# OpenTallas tools/qwen_missing/link_phy_gen.py: ot_qfd_serdes_112g_x12_phy_s597 hard-macro ABSTRACT (licensed PHY IP; FDI side only)
VERSION 5.7 ;
BUSBITCHARS "[]" ;
DIVIDERCHAR "/" ;
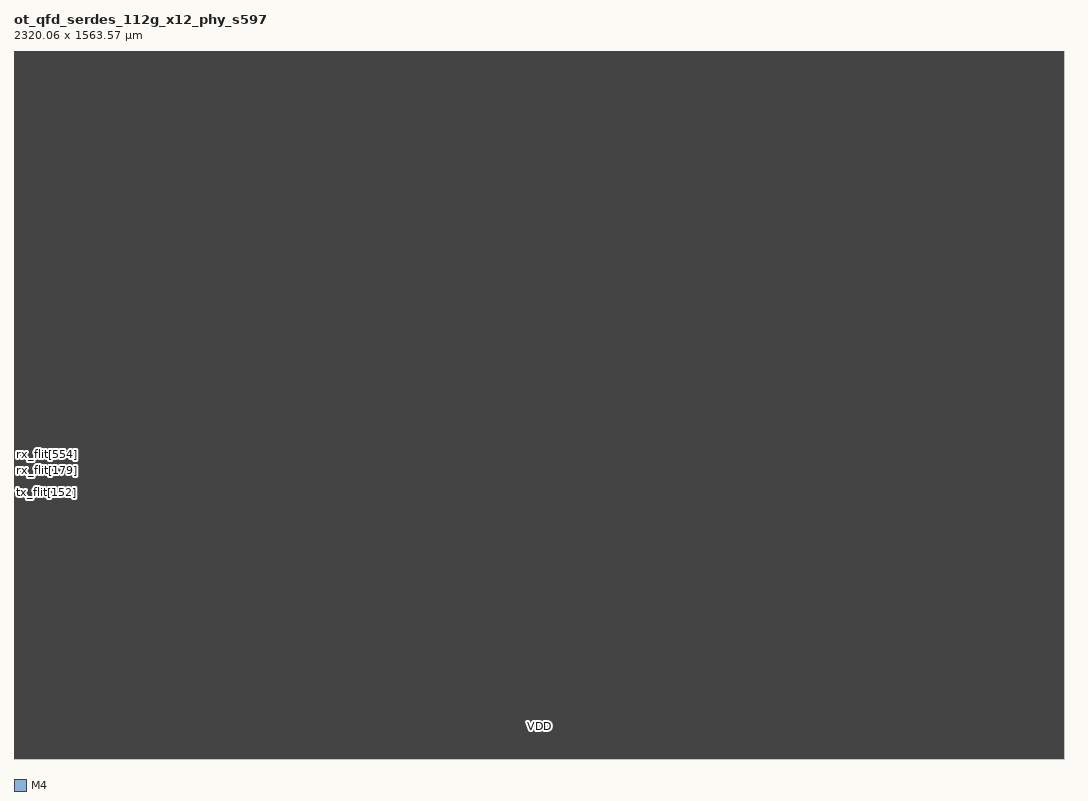
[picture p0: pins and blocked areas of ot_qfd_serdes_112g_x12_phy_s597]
MACRO ot_qfd_serdes_112g_x12_phy_s597
  FOREIGN ot_qfd_serdes_112g_x12_phy_s597 0 0 ;
  SYMMETRY X Y ;
  SIZE 2320.056 BY 1563.570 ;
  CLASS BLOCK ;
  PIN clk
    DIRECTION INPUT ;
    USE CLOCK ;
    SHAPE ABUTMENT ;
    PORT
      LAYER M4 ;
      RECT 0 600.000 0.192 600.024 ;
    END
  END clk
  PIN rst_n
    DIRECTION INPUT ;
    USE SIGNAL ;
    SHAPE ABUTMENT ;
    PORT
      LAYER M4 ;
      RECT 0 600.048 0.192 600.072 ;
    END
  END rst_n
  PIN tx_up
    DIRECTION OUTPUT ;
    USE SIGNAL ;
    SHAPE ABUTMENT ;
    PORT
      LAYER M4 ;
      RECT 0 600.096 0.192 600.120 ;
    END
  END tx_up
  PIN tx_v
    DIRECTION INPUT ;
    USE SIGNAL ;
    SHAPE ABUTMENT ;
    PORT
      LAYER M4 ;
      RECT 0 600.144 0.192 600.168 ;
    END
  END tx_v
  PIN tx_flit[0]
    DIRECTION INPUT ;
    USE SIGNAL ;
    SHAPE ABUTMENT ;
    PORT
      LAYER M4 ;
      RECT 0 600.192 0.192 600.216 ;
    END
  END tx_flit[0]
  PIN tx_flit[1]
    DIRECTION INPUT ;
    USE SIGNAL ;
    SHAPE ABUTMENT ;
    PORT
      LAYER M4 ;
      RECT 0 600.240 0.192 600.264 ;
    END
  END tx_flit[1]
  PIN tx_flit[2]
    DIRECTION INPUT ;
    USE SIGNAL ;
    SHAPE ABUTMENT ;
    PORT
      LAYER M4 ;
      RECT 0 600.288 0.192 600.312 ;
    END
  END tx_flit[2]
  PIN tx_flit[3]
    DIRECTION INPUT ;
    USE SIGNAL ;
    SHAPE ABUTMENT ;
    PORT
      LAYER M4 ;
      RECT 0 600.336 0.192 600.360 ;
    END
  END tx_flit[3]
  PIN tx_flit[4]
    DIRECTION INPUT ;
    USE SIGNAL ;
    SHAPE ABUTMENT ;
    PORT
      LAYER M4 ;
      RECT 0 600.384 0.192 600.408 ;
    END
  END tx_flit[4]
  PIN tx_flit[5]
    DIRECTION INPUT ;
    USE SIGNAL ;
    SHAPE ABUTMENT ;
    PORT
      LAYER M4 ;
      RECT 0 600.432 0.192 600.456 ;
    END
  END tx_flit[5]
  PIN tx_flit[6]
    DIRECTION INPUT ;
    USE SIGNAL ;
    SHAPE ABUTMENT ;
    PORT
      LAYER M4 ;
      RECT 0 600.480 0.192 600.504 ;
    END
  END tx_flit[6]
  PIN tx_flit[7]
    DIRECTION INPUT ;
    USE SIGNAL ;
    SHAPE ABUTMENT ;
    PORT
      LAYER M4 ;
      RECT 0 600.528 0.192 600.552 ;
    END
  END tx_flit[7]
  PIN tx_flit[8]
    DIRECTION INPUT ;
    USE SIGNAL ;
    SHAPE ABUTMENT ;
    PORT
      LAYER M4 ;
      RECT 0 600.576 0.192 600.600 ;
    END
  END tx_flit[8]
  PIN tx_flit[9]
    DIRECTION INPUT ;
    USE SIGNAL ;
    SHAPE ABUTMENT ;
    PORT
      LAYER M4 ;
      RECT 0 600.624 0.192 600.648 ;
    END
  END tx_flit[9]
  PIN tx_flit[10]
    DIRECTION INPUT ;
    USE SIGNAL ;
    SHAPE ABUTMENT ;
    PORT
      LAYER M4 ;
      RECT 0 600.672 0.192 600.696 ;
    END
  END tx_flit[10]
  PIN tx_flit[11]
    DIRECTION INPUT ;
    USE SIGNAL ;
    SHAPE ABUTMENT ;
    PORT
      LAYER M4 ;
      RECT 0 600.720 0.192 600.744 ;
    END
  END tx_flit[11]
  PIN tx_flit[12]
    DIRECTION INPUT ;
    USE SIGNAL ;
    SHAPE ABUTMENT ;
    PORT
      LAYER M4 ;
      RECT 0 600.768 0.192 600.792 ;
    END
  END tx_flit[12]
  PIN tx_flit[13]
    DIRECTION INPUT ;
    USE SIGNAL ;
    SHAPE ABUTMENT ;
    PORT
      LAYER M4 ;
      RECT 0 600.816 0.192 600.840 ;
    END
  END tx_flit[13]
  PIN tx_flit[14]
    DIRECTION INPUT ;
    USE SIGNAL ;
    SHAPE ABUTMENT ;
    PORT
      LAYER M4 ;
      RECT 0 600.864 0.192 600.888 ;
    END
  END tx_flit[14]
  PIN tx_flit[15]
    DIRECTION INPUT ;
    USE SIGNAL ;
    SHAPE ABUTMENT ;
    PORT
      LAYER M4 ;
      RECT 0 600.912 0.192 600.936 ;
    END
  END tx_flit[15]
  PIN tx_flit[16]
    DIRECTION INPUT ;
    USE SIGNAL ;
    SHAPE ABUTMENT ;
    PORT
      LAYER M4 ;
      RECT 0 600.960 0.192 600.984 ;
    END
  END tx_flit[16]
  PIN tx_flit[17]
    DIRECTION INPUT ;
    USE SIGNAL ;
    SHAPE ABUTMENT ;
    PORT
      LAYER M4 ;
      RECT 0 601.008 0.192 601.032 ;
    END
  END tx_flit[17]
  PIN tx_flit[18]
    DIRECTION INPUT ;
    USE SIGNAL ;
    SHAPE ABUTMENT ;
    PORT
      LAYER M4 ;
      RECT 0 601.056 0.192 601.080 ;
    END
  END tx_flit[18]
  PIN tx_flit[19]
    DIRECTION INPUT ;
    USE SIGNAL ;
    SHAPE ABUTMENT ;
    PORT
      LAYER M4 ;
      RECT 0 601.104 0.192 601.128 ;
    END
  END tx_flit[19]
  PIN tx_flit[20]
    DIRECTION INPUT ;
    USE SIGNAL ;
    SHAPE ABUTMENT ;
    PORT
      LAYER M4 ;
      RECT 0 601.152 0.192 601.176 ;
    END
  END tx_flit[20]
  PIN tx_flit[21]
    DIRECTION INPUT ;
    USE SIGNAL ;
    SHAPE ABUTMENT ;
    PORT
      LAYER M4 ;
      RECT 0 601.200 0.192 601.224 ;
    END
  END tx_flit[21]
  PIN tx_flit[22]
    DIRECTION INPUT ;
    USE SIGNAL ;
    SHAPE ABUTMENT ;
    PORT
      LAYER M4 ;
      RECT 0 601.248 0.192 601.272 ;
    END
  END tx_flit[22]
  PIN tx_flit[23]
    DIRECTION INPUT ;
    USE SIGNAL ;
    SHAPE ABUTMENT ;
    PORT
      LAYER M4 ;
      RECT 0 601.296 0.192 601.320 ;
    END
  END tx_flit[23]
  PIN tx_flit[24]
    DIRECTION INPUT ;
    USE SIGNAL ;
    SHAPE ABUTMENT ;
    PORT
      LAYER M4 ;
      RECT 0 601.344 0.192 601.368 ;
    END
  END tx_flit[24]
  PIN tx_flit[25]
    DIRECTION INPUT ;
    USE SIGNAL ;
    SHAPE ABUTMENT ;
    PORT
      LAYER M4 ;
      RECT 0 601.392 0.192 601.416 ;
    END
  END tx_flit[25]
  PIN tx_flit[26]
    DIRECTION INPUT ;
    USE SIGNAL ;
    SHAPE ABUTMENT ;
    PORT
      LAYER M4 ;
      RECT 0 601.440 0.192 601.464 ;
    END
  END tx_flit[26]
  PIN tx_flit[27]
    DIRECTION INPUT ;
    USE SIGNAL ;
    SHAPE ABUTMENT ;
    PORT
      LAYER M4 ;
      RECT 0 601.488 0.192 601.512 ;
    END
  END tx_flit[27]
  PIN tx_flit[28]
    DIRECTION INPUT ;
    USE SIGNAL ;
    SHAPE ABUTMENT ;
    PORT
      LAYER M4 ;
      RECT 0 601.536 0.192 601.560 ;
    END
  END tx_flit[28]
  PIN tx_flit[29]
    DIRECTION INPUT ;
    USE SIGNAL ;
    SHAPE ABUTMENT ;
    PORT
      LAYER M4 ;
      RECT 0 601.584 0.192 601.608 ;
    END
  END tx_flit[29]
  PIN tx_flit[30]
    DIRECTION INPUT ;
    USE SIGNAL ;
    SHAPE ABUTMENT ;
    PORT
      LAYER M4 ;
      RECT 0 601.632 0.192 601.656 ;
    END
  END tx_flit[30]
  PIN tx_flit[31]
    DIRECTION INPUT ;
    USE SIGNAL ;
    SHAPE ABUTMENT ;
    PORT
      LAYER M4 ;
      RECT 0 601.680 0.192 601.704 ;
    END
  END tx_flit[31]
  PIN tx_flit[32]
    DIRECTION INPUT ;
    USE SIGNAL ;
    SHAPE ABUTMENT ;
    PORT
      LAYER M4 ;
      RECT 0 601.728 0.192 601.752 ;
    END
  END tx_flit[32]
  PIN tx_flit[33]
    DIRECTION INPUT ;
    USE SIGNAL ;
    SHAPE ABUTMENT ;
    PORT
      LAYER M4 ;
      RECT 0 601.776 0.192 601.800 ;
    END
  END tx_flit[33]
  PIN tx_flit[34]
    DIRECTION INPUT ;
    USE SIGNAL ;
    SHAPE ABUTMENT ;
    PORT
      LAYER M4 ;
      RECT 0 601.824 0.192 601.848 ;
    END
  END tx_flit[34]
  PIN tx_flit[35]
    DIRECTION INPUT ;
    USE SIGNAL ;
    SHAPE ABUTMENT ;
    PORT
      LAYER M4 ;
      RECT 0 601.872 0.192 601.896 ;
    END
  END tx_flit[35]
  PIN tx_flit[36]
    DIRECTION INPUT ;
    USE SIGNAL ;
    SHAPE ABUTMENT ;
    PORT
      LAYER M4 ;
      RECT 0 601.920 0.192 601.944 ;
    END
  END tx_flit[36]
  PIN tx_flit[37]
    DIRECTION INPUT ;
    USE SIGNAL ;
    SHAPE ABUTMENT ;
    PORT
      LAYER M4 ;
      RECT 0 601.968 0.192 601.992 ;
    END
  END tx_flit[37]
  PIN tx_flit[38]
    DIRECTION INPUT ;
    USE SIGNAL ;
    SHAPE ABUTMENT ;
    PORT
      LAYER M4 ;
      RECT 0 602.016 0.192 602.040 ;
    END
  END tx_flit[38]
  PIN tx_flit[39]
    DIRECTION INPUT ;
    USE SIGNAL ;
    SHAPE ABUTMENT ;
    PORT
      LAYER M4 ;
      RECT 0 602.064 0.192 602.088 ;
    END
  END tx_flit[39]
  PIN tx_flit[40]
    DIRECTION INPUT ;
    USE SIGNAL ;
    SHAPE ABUTMENT ;
    PORT
      LAYER M4 ;
      RECT 0 602.112 0.192 602.136 ;
    END
  END tx_flit[40]
  PIN tx_flit[41]
    DIRECTION INPUT ;
    USE SIGNAL ;
    SHAPE ABUTMENT ;
    PORT
      LAYER M4 ;
      RECT 0 602.160 0.192 602.184 ;
    END
  END tx_flit[41]
  PIN tx_flit[42]
    DIRECTION INPUT ;
    USE SIGNAL ;
    SHAPE ABUTMENT ;
    PORT
      LAYER M4 ;
      RECT 0 602.208 0.192 602.232 ;
    END
  END tx_flit[42]
  PIN tx_flit[43]
    DIRECTION INPUT ;
    USE SIGNAL ;
    SHAPE ABUTMENT ;
    PORT
      LAYER M4 ;
      RECT 0 602.256 0.192 602.280 ;
    END
  END tx_flit[43]
  PIN tx_flit[44]
    DIRECTION INPUT ;
    USE SIGNAL ;
    SHAPE ABUTMENT ;
    PORT
      LAYER M4 ;
      RECT 0 602.304 0.192 602.328 ;
    END
  END tx_flit[44]
  PIN tx_flit[45]
    DIRECTION INPUT ;
    USE SIGNAL ;
    SHAPE ABUTMENT ;
    PORT
      LAYER M4 ;
      RECT 0 602.352 0.192 602.376 ;
    END
  END tx_flit[45]
  PIN tx_flit[46]
    DIRECTION INPUT ;
    USE SIGNAL ;
    SHAPE ABUTMENT ;
    PORT
      LAYER M4 ;
      RECT 0 602.400 0.192 602.424 ;
    END
  END tx_flit[46]
  PIN tx_flit[47]
    DIRECTION INPUT ;
    USE SIGNAL ;
    SHAPE ABUTMENT ;
    PORT
      LAYER M4 ;
      RECT 0 602.448 0.192 602.472 ;
    END
  END tx_flit[47]
  PIN tx_flit[48]
    DIRECTION INPUT ;
    USE SIGNAL ;
    SHAPE ABUTMENT ;
    PORT
      LAYER M4 ;
      RECT 0 602.496 0.192 602.520 ;
    END
  END tx_flit[48]
  PIN tx_flit[49]
    DIRECTION INPUT ;
    USE SIGNAL ;
    SHAPE ABUTMENT ;
    PORT
      LAYER M4 ;
      RECT 0 602.544 0.192 602.568 ;
    END
  END tx_flit[49]
  PIN tx_flit[50]
    DIRECTION INPUT ;
    USE SIGNAL ;
    SHAPE ABUTMENT ;
    PORT
      LAYER M4 ;
      RECT 0 602.592 0.192 602.616 ;
    END
  END tx_flit[50]
  PIN tx_flit[51]
    DIRECTION INPUT ;
    USE SIGNAL ;
    SHAPE ABUTMENT ;
    PORT
      LAYER M4 ;
      RECT 0 602.640 0.192 602.664 ;
    END
  END tx_flit[51]
  PIN tx_flit[52]
    DIRECTION INPUT ;
    USE SIGNAL ;
    SHAPE ABUTMENT ;
    PORT
      LAYER M4 ;
      RECT 0 602.688 0.192 602.712 ;
    END
  END tx_flit[52]
  PIN tx_flit[53]
    DIRECTION INPUT ;
    USE SIGNAL ;
    SHAPE ABUTMENT ;
    PORT
      LAYER M4 ;
      RECT 0 602.736 0.192 602.760 ;
    END
  END tx_flit[53]
  PIN tx_flit[54]
    DIRECTION INPUT ;
    USE SIGNAL ;
    SHAPE ABUTMENT ;
    PORT
      LAYER M4 ;
      RECT 0 602.784 0.192 602.808 ;
    END
  END tx_flit[54]
  PIN tx_flit[55]
    DIRECTION INPUT ;
    USE SIGNAL ;
    SHAPE ABUTMENT ;
    PORT
      LAYER M4 ;
      RECT 0 602.832 0.192 602.856 ;
    END
  END tx_flit[55]
  PIN tx_flit[56]
    DIRECTION INPUT ;
    USE SIGNAL ;
    SHAPE ABUTMENT ;
    PORT
      LAYER M4 ;
      RECT 0 602.880 0.192 602.904 ;
    END
  END tx_flit[56]
  PIN tx_flit[57]
    DIRECTION INPUT ;
    USE SIGNAL ;
    SHAPE ABUTMENT ;
    PORT
      LAYER M4 ;
      RECT 0 602.928 0.192 602.952 ;
    END
  END tx_flit[57]
  PIN tx_flit[58]
    DIRECTION INPUT ;
    USE SIGNAL ;
    SHAPE ABUTMENT ;
    PORT
      LAYER M4 ;
      RECT 0 602.976 0.192 603.000 ;
    END
  END tx_flit[58]
  PIN tx_flit[59]
    DIRECTION INPUT ;
    USE SIGNAL ;
    SHAPE ABUTMENT ;
    PORT
      LAYER M4 ;
      RECT 0 603.024 0.192 603.048 ;
    END
  END tx_flit[59]
  PIN tx_flit[60]
    DIRECTION INPUT ;
    USE SIGNAL ;
    SHAPE ABUTMENT ;
    PORT
      LAYER M4 ;
      RECT 0 603.072 0.192 603.096 ;
    END
  END tx_flit[60]
  PIN tx_flit[61]
    DIRECTION INPUT ;
    USE SIGNAL ;
    SHAPE ABUTMENT ;
    PORT
      LAYER M4 ;
      RECT 0 603.120 0.192 603.144 ;
    END
  END tx_flit[61]
  PIN tx_flit[62]
    DIRECTION INPUT ;
    USE SIGNAL ;
    SHAPE ABUTMENT ;
    PORT
      LAYER M4 ;
      RECT 0 603.168 0.192 603.192 ;
    END
  END tx_flit[62]
  PIN tx_flit[63]
    DIRECTION INPUT ;
    USE SIGNAL ;
    SHAPE ABUTMENT ;
    PORT
      LAYER M4 ;
      RECT 0 603.216 0.192 603.240 ;
    END
  END tx_flit[63]
  PIN tx_flit[64]
    DIRECTION INPUT ;
    USE SIGNAL ;
    SHAPE ABUTMENT ;
    PORT
      LAYER M4 ;
      RECT 0 603.264 0.192 603.288 ;
    END
  END tx_flit[64]
  PIN tx_flit[65]
    DIRECTION INPUT ;
    USE SIGNAL ;
    SHAPE ABUTMENT ;
    PORT
      LAYER M4 ;
      RECT 0 603.312 0.192 603.336 ;
    END
  END tx_flit[65]
  PIN tx_flit[66]
    DIRECTION INPUT ;
    USE SIGNAL ;
    SHAPE ABUTMENT ;
    PORT
      LAYER M4 ;
      RECT 0 603.360 0.192 603.384 ;
    END
  END tx_flit[66]
  PIN tx_flit[67]
    DIRECTION INPUT ;
    USE SIGNAL ;
    SHAPE ABUTMENT ;
    PORT
      LAYER M4 ;
      RECT 0 603.408 0.192 603.432 ;
    END
  END tx_flit[67]
  PIN tx_flit[68]
    DIRECTION INPUT ;
    USE SIGNAL ;
    SHAPE ABUTMENT ;
    PORT
      LAYER M4 ;
      RECT 0 603.456 0.192 603.480 ;
    END
  END tx_flit[68]
  PIN tx_flit[69]
    DIRECTION INPUT ;
    USE SIGNAL ;
    SHAPE ABUTMENT ;
    PORT
      LAYER M4 ;
      RECT 0 603.504 0.192 603.528 ;
    END
  END tx_flit[69]
  PIN tx_flit[70]
    DIRECTION INPUT ;
    USE SIGNAL ;
    SHAPE ABUTMENT ;
    PORT
      LAYER M4 ;
      RECT 0 603.552 0.192 603.576 ;
    END
  END tx_flit[70]
  PIN tx_flit[71]
    DIRECTION INPUT ;
    USE SIGNAL ;
    SHAPE ABUTMENT ;
    PORT
      LAYER M4 ;
      RECT 0 603.600 0.192 603.624 ;
    END
  END tx_flit[71]
  PIN tx_flit[72]
    DIRECTION INPUT ;
    USE SIGNAL ;
    SHAPE ABUTMENT ;
    PORT
      LAYER M4 ;
      RECT 0 603.648 0.192 603.672 ;
    END
  END tx_flit[72]
  PIN tx_flit[73]
    DIRECTION INPUT ;
    USE SIGNAL ;
    SHAPE ABUTMENT ;
    PORT
      LAYER M4 ;
      RECT 0 603.696 0.192 603.720 ;
    END
  END tx_flit[73]
  PIN tx_flit[74]
    DIRECTION INPUT ;
    USE SIGNAL ;
    SHAPE ABUTMENT ;
    PORT
      LAYER M4 ;
      RECT 0 603.744 0.192 603.768 ;
    END
  END tx_flit[74]
  PIN tx_flit[75]
    DIRECTION INPUT ;
    USE SIGNAL ;
    SHAPE ABUTMENT ;
    PORT
      LAYER M4 ;
      RECT 0 603.792 0.192 603.816 ;
    END
  END tx_flit[75]
  PIN tx_flit[76]
    DIRECTION INPUT ;
    USE SIGNAL ;
    SHAPE ABUTMENT ;
    PORT
      LAYER M4 ;
      RECT 0 603.840 0.192 603.864 ;
    END
  END tx_flit[76]
  PIN tx_flit[77]
    DIRECTION INPUT ;
    USE SIGNAL ;
    SHAPE ABUTMENT ;
    PORT
      LAYER M4 ;
      RECT 0 603.888 0.192 603.912 ;
    END
  END tx_flit[77]
  PIN tx_flit[78]
    DIRECTION INPUT ;
    USE SIGNAL ;
    SHAPE ABUTMENT ;
    PORT
      LAYER M4 ;
      RECT 0 603.936 0.192 603.960 ;
    END
  END tx_flit[78]
  PIN tx_flit[79]
    DIRECTION INPUT ;
    USE SIGNAL ;
    SHAPE ABUTMENT ;
    PORT
      LAYER M4 ;
      RECT 0 603.984 0.192 604.008 ;
    END
  END tx_flit[79]
  PIN tx_flit[80]
    DIRECTION INPUT ;
    USE SIGNAL ;
    SHAPE ABUTMENT ;
    PORT
      LAYER M4 ;
      RECT 0 604.032 0.192 604.056 ;
    END
  END tx_flit[80]
  PIN tx_flit[81]
    DIRECTION INPUT ;
    USE SIGNAL ;
    SHAPE ABUTMENT ;
    PORT
      LAYER M4 ;
      RECT 0 604.080 0.192 604.104 ;
    END
  END tx_flit[81]
  PIN tx_flit[82]
    DIRECTION INPUT ;
    USE SIGNAL ;
    SHAPE ABUTMENT ;
    PORT
      LAYER M4 ;
      RECT 0 604.128 0.192 604.152 ;
    END
  END tx_flit[82]
  PIN tx_flit[83]
    DIRECTION INPUT ;
    USE SIGNAL ;
    SHAPE ABUTMENT ;
    PORT
      LAYER M4 ;
      RECT 0 604.176 0.192 604.200 ;
    END
  END tx_flit[83]
  PIN tx_flit[84]
    DIRECTION INPUT ;
    USE SIGNAL ;
    SHAPE ABUTMENT ;
    PORT
      LAYER M4 ;
      RECT 0 604.224 0.192 604.248 ;
    END
  END tx_flit[84]
  PIN tx_flit[85]
    DIRECTION INPUT ;
    USE SIGNAL ;
    SHAPE ABUTMENT ;
    PORT
      LAYER M4 ;
      RECT 0 604.272 0.192 604.296 ;
    END
  END tx_flit[85]
  PIN tx_flit[86]
    DIRECTION INPUT ;
    USE SIGNAL ;
    SHAPE ABUTMENT ;
    PORT
      LAYER M4 ;
      RECT 0 604.320 0.192 604.344 ;
    END
  END tx_flit[86]
  PIN tx_flit[87]
    DIRECTION INPUT ;
    USE SIGNAL ;
    SHAPE ABUTMENT ;
    PORT
      LAYER M4 ;
      RECT 0 604.368 0.192 604.392 ;
    END
  END tx_flit[87]
  PIN tx_flit[88]
    DIRECTION INPUT ;
    USE SIGNAL ;
    SHAPE ABUTMENT ;
    PORT
      LAYER M4 ;
      RECT 0 604.416 0.192 604.440 ;
    END
  END tx_flit[88]
  PIN tx_flit[89]
    DIRECTION INPUT ;
    USE SIGNAL ;
    SHAPE ABUTMENT ;
    PORT
      LAYER M4 ;
      RECT 0 604.464 0.192 604.488 ;
    END
  END tx_flit[89]
  PIN tx_flit[90]
    DIRECTION INPUT ;
    USE SIGNAL ;
    SHAPE ABUTMENT ;
    PORT
      LAYER M4 ;
      RECT 0 604.512 0.192 604.536 ;
    END
  END tx_flit[90]
  PIN tx_flit[91]
    DIRECTION INPUT ;
    USE SIGNAL ;
    SHAPE ABUTMENT ;
    PORT
      LAYER M4 ;
      RECT 0 604.560 0.192 604.584 ;
    END
  END tx_flit[91]
  PIN tx_flit[92]
    DIRECTION INPUT ;
    USE SIGNAL ;
    SHAPE ABUTMENT ;
    PORT
      LAYER M4 ;
      RECT 0 604.608 0.192 604.632 ;
    END
  END tx_flit[92]
  PIN tx_flit[93]
    DIRECTION INPUT ;
    USE SIGNAL ;
    SHAPE ABUTMENT ;
    PORT
      LAYER M4 ;
      RECT 0 604.656 0.192 604.680 ;
    END
  END tx_flit[93]
  PIN tx_flit[94]
    DIRECTION INPUT ;
    USE SIGNAL ;
    SHAPE ABUTMENT ;
    PORT
      LAYER M4 ;
      RECT 0 604.704 0.192 604.728 ;
    END
  END tx_flit[94]
  PIN tx_flit[95]
    DIRECTION INPUT ;
    USE SIGNAL ;
    SHAPE ABUTMENT ;
    PORT
      LAYER M4 ;
      RECT 0 604.752 0.192 604.776 ;
    END
  END tx_flit[95]
  PIN tx_flit[96]
    DIRECTION INPUT ;
    USE SIGNAL ;
    SHAPE ABUTMENT ;
    PORT
      LAYER M4 ;
      RECT 0 604.800 0.192 604.824 ;
    END
  END tx_flit[96]
  PIN tx_flit[97]
    DIRECTION INPUT ;
    USE SIGNAL ;
    SHAPE ABUTMENT ;
    PORT
      LAYER M4 ;
      RECT 0 604.848 0.192 604.872 ;
    END
  END tx_flit[97]
  PIN tx_flit[98]
    DIRECTION INPUT ;
    USE SIGNAL ;
    SHAPE ABUTMENT ;
    PORT
      LAYER M4 ;
      RECT 0 604.896 0.192 604.920 ;
    END
  END tx_flit[98]
  PIN tx_flit[99]
    DIRECTION INPUT ;
    USE SIGNAL ;
    SHAPE ABUTMENT ;
    PORT
      LAYER M4 ;
      RECT 0 604.944 0.192 604.968 ;
    END
  END tx_flit[99]
  PIN tx_flit[100]
    DIRECTION INPUT ;
    USE SIGNAL ;
    SHAPE ABUTMENT ;
    PORT
      LAYER M4 ;
      RECT 0 604.992 0.192 605.016 ;
    END
  END tx_flit[100]
  PIN tx_flit[101]
    DIRECTION INPUT ;
    USE SIGNAL ;
    SHAPE ABUTMENT ;
    PORT
      LAYER M4 ;
      RECT 0 605.040 0.192 605.064 ;
    END
  END tx_flit[101]
  PIN tx_flit[102]
    DIRECTION INPUT ;
    USE SIGNAL ;
    SHAPE ABUTMENT ;
    PORT
      LAYER M4 ;
      RECT 0 605.088 0.192 605.112 ;
    END
  END tx_flit[102]
  PIN tx_flit[103]
    DIRECTION INPUT ;
    USE SIGNAL ;
    SHAPE ABUTMENT ;
    PORT
      LAYER M4 ;
      RECT 0 605.136 0.192 605.160 ;
    END
  END tx_flit[103]
  PIN tx_flit[104]
    DIRECTION INPUT ;
    USE SIGNAL ;
    SHAPE ABUTMENT ;
    PORT
      LAYER M4 ;
      RECT 0 605.184 0.192 605.208 ;
    END
  END tx_flit[104]
  PIN tx_flit[105]
    DIRECTION INPUT ;
    USE SIGNAL ;
    SHAPE ABUTMENT ;
    PORT
      LAYER M4 ;
      RECT 0 605.232 0.192 605.256 ;
    END
  END tx_flit[105]
  PIN tx_flit[106]
    DIRECTION INPUT ;
    USE SIGNAL ;
    SHAPE ABUTMENT ;
    PORT
      LAYER M4 ;
      RECT 0 605.280 0.192 605.304 ;
    END
  END tx_flit[106]
  PIN tx_flit[107]
    DIRECTION INPUT ;
    USE SIGNAL ;
    SHAPE ABUTMENT ;
    PORT
      LAYER M4 ;
      RECT 0 605.328 0.192 605.352 ;
    END
  END tx_flit[107]
  PIN tx_flit[108]
    DIRECTION INPUT ;
    USE SIGNAL ;
    SHAPE ABUTMENT ;
    PORT
      LAYER M4 ;
      RECT 0 605.376 0.192 605.400 ;
    END
  END tx_flit[108]
  PIN tx_flit[109]
    DIRECTION INPUT ;
    USE SIGNAL ;
    SHAPE ABUTMENT ;
    PORT
      LAYER M4 ;
      RECT 0 605.424 0.192 605.448 ;
    END
  END tx_flit[109]
  PIN tx_flit[110]
    DIRECTION INPUT ;
    USE SIGNAL ;
    SHAPE ABUTMENT ;
    PORT
      LAYER M4 ;
      RECT 0 605.472 0.192 605.496 ;
    END
  END tx_flit[110]
  PIN tx_flit[111]
    DIRECTION INPUT ;
    USE SIGNAL ;
    SHAPE ABUTMENT ;
    PORT
      LAYER M4 ;
      RECT 0 605.520 0.192 605.544 ;
    END
  END tx_flit[111]
  PIN tx_flit[112]
    DIRECTION INPUT ;
    USE SIGNAL ;
    SHAPE ABUTMENT ;
    PORT
      LAYER M4 ;
      RECT 0 605.568 0.192 605.592 ;
    END
  END tx_flit[112]
  PIN tx_flit[113]
    DIRECTION INPUT ;
    USE SIGNAL ;
    SHAPE ABUTMENT ;
    PORT
      LAYER M4 ;
      RECT 0 605.616 0.192 605.640 ;
    END
  END tx_flit[113]
  PIN tx_flit[114]
    DIRECTION INPUT ;
    USE SIGNAL ;
    SHAPE ABUTMENT ;
    PORT
      LAYER M4 ;
      RECT 0 605.664 0.192 605.688 ;
    END
  END tx_flit[114]
  PIN tx_flit[115]
    DIRECTION INPUT ;
    USE SIGNAL ;
    SHAPE ABUTMENT ;
    PORT
      LAYER M4 ;
      RECT 0 605.712 0.192 605.736 ;
    END
  END tx_flit[115]
  PIN tx_flit[116]
    DIRECTION INPUT ;
    USE SIGNAL ;
    SHAPE ABUTMENT ;
    PORT
      LAYER M4 ;
      RECT 0 605.760 0.192 605.784 ;
    END
  END tx_flit[116]
  PIN tx_flit[117]
    DIRECTION INPUT ;
    USE SIGNAL ;
    SHAPE ABUTMENT ;
    PORT
      LAYER M4 ;
      RECT 0 605.808 0.192 605.832 ;
    END
  END tx_flit[117]
  PIN tx_flit[118]
    DIRECTION INPUT ;
    USE SIGNAL ;
    SHAPE ABUTMENT ;
    PORT
      LAYER M4 ;
      RECT 0 605.856 0.192 605.880 ;
    END
  END tx_flit[118]
  PIN tx_flit[119]
    DIRECTION INPUT ;
    USE SIGNAL ;
    SHAPE ABUTMENT ;
    PORT
      LAYER M4 ;
      RECT 0 605.904 0.192 605.928 ;
    END
  END tx_flit[119]
  PIN tx_flit[120]
    DIRECTION INPUT ;
    USE SIGNAL ;
    SHAPE ABUTMENT ;
    PORT
      LAYER M4 ;
      RECT 0 605.952 0.192 605.976 ;
    END
  END tx_flit[120]
  PIN tx_flit[121]
    DIRECTION INPUT ;
    USE SIGNAL ;
    SHAPE ABUTMENT ;
    PORT
      LAYER M4 ;
      RECT 0 606.000 0.192 606.024 ;
    END
  END tx_flit[121]
  PIN tx_flit[122]
    DIRECTION INPUT ;
    USE SIGNAL ;
    SHAPE ABUTMENT ;
    PORT
      LAYER M4 ;
      RECT 0 606.048 0.192 606.072 ;
    END
  END tx_flit[122]
  PIN tx_flit[123]
    DIRECTION INPUT ;
    USE SIGNAL ;
    SHAPE ABUTMENT ;
    PORT
      LAYER M4 ;
      RECT 0 606.096 0.192 606.120 ;
    END
  END tx_flit[123]
  PIN tx_flit[124]
    DIRECTION INPUT ;
    USE SIGNAL ;
    SHAPE ABUTMENT ;
    PORT
      LAYER M4 ;
      RECT 0 606.144 0.192 606.168 ;
    END
  END tx_flit[124]
  PIN tx_flit[125]
    DIRECTION INPUT ;
    USE SIGNAL ;
    SHAPE ABUTMENT ;
    PORT
      LAYER M4 ;
      RECT 0 606.192 0.192 606.216 ;
    END
  END tx_flit[125]
  PIN tx_flit[126]
    DIRECTION INPUT ;
    USE SIGNAL ;
    SHAPE ABUTMENT ;
    PORT
      LAYER M4 ;
      RECT 0 606.240 0.192 606.264 ;
    END
  END tx_flit[126]
  PIN tx_flit[127]
    DIRECTION INPUT ;
    USE SIGNAL ;
    SHAPE ABUTMENT ;
    PORT
      LAYER M4 ;
      RECT 0 606.288 0.192 606.312 ;
    END
  END tx_flit[127]
  PIN tx_flit[128]
    DIRECTION INPUT ;
    USE SIGNAL ;
    SHAPE ABUTMENT ;
    PORT
      LAYER M4 ;
      RECT 0 606.336 0.192 606.360 ;
    END
  END tx_flit[128]
  PIN tx_flit[129]
    DIRECTION INPUT ;
    USE SIGNAL ;
    SHAPE ABUTMENT ;
    PORT
      LAYER M4 ;
      RECT 0 606.384 0.192 606.408 ;
    END
  END tx_flit[129]
  PIN tx_flit[130]
    DIRECTION INPUT ;
    USE SIGNAL ;
    SHAPE ABUTMENT ;
    PORT
      LAYER M4 ;
      RECT 0 606.432 0.192 606.456 ;
    END
  END tx_flit[130]
  PIN tx_flit[131]
    DIRECTION INPUT ;
    USE SIGNAL ;
    SHAPE ABUTMENT ;
    PORT
      LAYER M4 ;
      RECT 0 606.480 0.192 606.504 ;
    END
  END tx_flit[131]
  PIN tx_flit[132]
    DIRECTION INPUT ;
    USE SIGNAL ;
    SHAPE ABUTMENT ;
    PORT
      LAYER M4 ;
      RECT 0 606.528 0.192 606.552 ;
    END
  END tx_flit[132]
  PIN tx_flit[133]
    DIRECTION INPUT ;
    USE SIGNAL ;
    SHAPE ABUTMENT ;
    PORT
      LAYER M4 ;
      RECT 0 606.576 0.192 606.600 ;
    END
  END tx_flit[133]
  PIN tx_flit[134]
    DIRECTION INPUT ;
    USE SIGNAL ;
    SHAPE ABUTMENT ;
    PORT
      LAYER M4 ;
      RECT 0 606.624 0.192 606.648 ;
    END
  END tx_flit[134]
  PIN tx_flit[135]
    DIRECTION INPUT ;
    USE SIGNAL ;
    SHAPE ABUTMENT ;
    PORT
      LAYER M4 ;
      RECT 0 606.672 0.192 606.696 ;
    END
  END tx_flit[135]
  PIN tx_flit[136]
    DIRECTION INPUT ;
    USE SIGNAL ;
    SHAPE ABUTMENT ;
    PORT
      LAYER M4 ;
      RECT 0 606.720 0.192 606.744 ;
    END
  END tx_flit[136]
  PIN tx_flit[137]
    DIRECTION INPUT ;
    USE SIGNAL ;
    SHAPE ABUTMENT ;
    PORT
      LAYER M4 ;
      RECT 0 606.768 0.192 606.792 ;
    END
  END tx_flit[137]
  PIN tx_flit[138]
    DIRECTION INPUT ;
    USE SIGNAL ;
    SHAPE ABUTMENT ;
    PORT
      LAYER M4 ;
      RECT 0 606.816 0.192 606.840 ;
    END
  END tx_flit[138]
  PIN tx_flit[139]
    DIRECTION INPUT ;
    USE SIGNAL ;
    SHAPE ABUTMENT ;
    PORT
      LAYER M4 ;
      RECT 0 606.864 0.192 606.888 ;
    END
  END tx_flit[139]
  PIN tx_flit[140]
    DIRECTION INPUT ;
    USE SIGNAL ;
    SHAPE ABUTMENT ;
    PORT
      LAYER M4 ;
      RECT 0 606.912 0.192 606.936 ;
    END
  END tx_flit[140]
  PIN tx_flit[141]
    DIRECTION INPUT ;
    USE SIGNAL ;
    SHAPE ABUTMENT ;
    PORT
      LAYER M4 ;
      RECT 0 606.960 0.192 606.984 ;
    END
  END tx_flit[141]
  PIN tx_flit[142]
    DIRECTION INPUT ;
    USE SIGNAL ;
    SHAPE ABUTMENT ;
    PORT
      LAYER M4 ;
      RECT 0 607.008 0.192 607.032 ;
    END
  END tx_flit[142]
  PIN tx_flit[143]
    DIRECTION INPUT ;
    USE SIGNAL ;
    SHAPE ABUTMENT ;
    PORT
      LAYER M4 ;
      RECT 0 607.056 0.192 607.080 ;
    END
  END tx_flit[143]
  PIN tx_flit[144]
    DIRECTION INPUT ;
    USE SIGNAL ;
    SHAPE ABUTMENT ;
    PORT
      LAYER M4 ;
      RECT 0 607.104 0.192 607.128 ;
    END
  END tx_flit[144]
  PIN tx_flit[145]
    DIRECTION INPUT ;
    USE SIGNAL ;
    SHAPE ABUTMENT ;
    PORT
      LAYER M4 ;
      RECT 0 607.152 0.192 607.176 ;
    END
  END tx_flit[145]
  PIN tx_flit[146]
    DIRECTION INPUT ;
    USE SIGNAL ;
    SHAPE ABUTMENT ;
    PORT
      LAYER M4 ;
      RECT 0 607.200 0.192 607.224 ;
    END
  END tx_flit[146]
  PIN tx_flit[147]
    DIRECTION INPUT ;
    USE SIGNAL ;
    SHAPE ABUTMENT ;
    PORT
      LAYER M4 ;
      RECT 0 607.248 0.192 607.272 ;
    END
  END tx_flit[147]
  PIN tx_flit[148]
    DIRECTION INPUT ;
    USE SIGNAL ;
    SHAPE ABUTMENT ;
    PORT
      LAYER M4 ;
      RECT 0 607.296 0.192 607.320 ;
    END
  END tx_flit[148]
  PIN tx_flit[149]
    DIRECTION INPUT ;
    USE SIGNAL ;
    SHAPE ABUTMENT ;
    PORT
      LAYER M4 ;
      RECT 0 607.344 0.192 607.368 ;
    END
  END tx_flit[149]
  PIN tx_flit[150]
    DIRECTION INPUT ;
    USE SIGNAL ;
    SHAPE ABUTMENT ;
    PORT
      LAYER M4 ;
      RECT 0 607.392 0.192 607.416 ;
    END
  END tx_flit[150]
  PIN tx_flit[151]
    DIRECTION INPUT ;
    USE SIGNAL ;
    SHAPE ABUTMENT ;
    PORT
      LAYER M4 ;
      RECT 0 607.440 0.192 607.464 ;
    END
  END tx_flit[151]
  PIN tx_flit[152]
    DIRECTION INPUT ;
    USE SIGNAL ;
    SHAPE ABUTMENT ;
    PORT
      LAYER M4 ;
      RECT 0 607.488 0.192 607.512 ;
    END
  END tx_flit[152]
  PIN tx_flit[153]
    DIRECTION INPUT ;
    USE SIGNAL ;
    SHAPE ABUTMENT ;
    PORT
      LAYER M4 ;
      RECT 0 607.536 0.192 607.560 ;
    END
  END tx_flit[153]
  PIN tx_flit[154]
    DIRECTION INPUT ;
    USE SIGNAL ;
    SHAPE ABUTMENT ;
    PORT
      LAYER M4 ;
      RECT 0 607.584 0.192 607.608 ;
    END
  END tx_flit[154]
  PIN tx_flit[155]
    DIRECTION INPUT ;
    USE SIGNAL ;
    SHAPE ABUTMENT ;
    PORT
      LAYER M4 ;
      RECT 0 607.632 0.192 607.656 ;
    END
  END tx_flit[155]
  PIN tx_flit[156]
    DIRECTION INPUT ;
    USE SIGNAL ;
    SHAPE ABUTMENT ;
    PORT
      LAYER M4 ;
      RECT 0 607.680 0.192 607.704 ;
    END
  END tx_flit[156]
  PIN tx_flit[157]
    DIRECTION INPUT ;
    USE SIGNAL ;
    SHAPE ABUTMENT ;
    PORT
      LAYER M4 ;
      RECT 0 607.728 0.192 607.752 ;
    END
  END tx_flit[157]
  PIN tx_flit[158]
    DIRECTION INPUT ;
    USE SIGNAL ;
    SHAPE ABUTMENT ;
    PORT
      LAYER M4 ;
      RECT 0 607.776 0.192 607.800 ;
    END
  END tx_flit[158]
  PIN tx_flit[159]
    DIRECTION INPUT ;
    USE SIGNAL ;
    SHAPE ABUTMENT ;
    PORT
      LAYER M4 ;
      RECT 0 607.824 0.192 607.848 ;
    END
  END tx_flit[159]
  PIN tx_flit[160]
    DIRECTION INPUT ;
    USE SIGNAL ;
    SHAPE ABUTMENT ;
    PORT
      LAYER M4 ;
      RECT 0 607.872 0.192 607.896 ;
    END
  END tx_flit[160]
  PIN tx_flit[161]
    DIRECTION INPUT ;
    USE SIGNAL ;
    SHAPE ABUTMENT ;
    PORT
      LAYER M4 ;
      RECT 0 607.920 0.192 607.944 ;
    END
  END tx_flit[161]
  PIN tx_flit[162]
    DIRECTION INPUT ;
    USE SIGNAL ;
    SHAPE ABUTMENT ;
    PORT
      LAYER M4 ;
      RECT 0 607.968 0.192 607.992 ;
    END
  END tx_flit[162]
  PIN tx_flit[163]
    DIRECTION INPUT ;
    USE SIGNAL ;
    SHAPE ABUTMENT ;
    PORT
      LAYER M4 ;
      RECT 0 608.016 0.192 608.040 ;
    END
  END tx_flit[163]
  PIN tx_flit[164]
    DIRECTION INPUT ;
    USE SIGNAL ;
    SHAPE ABUTMENT ;
    PORT
      LAYER M4 ;
      RECT 0 608.064 0.192 608.088 ;
    END
  END tx_flit[164]
  PIN tx_flit[165]
    DIRECTION INPUT ;
    USE SIGNAL ;
    SHAPE ABUTMENT ;
    PORT
      LAYER M4 ;
      RECT 0 608.112 0.192 608.136 ;
    END
  END tx_flit[165]
  PIN tx_flit[166]
    DIRECTION INPUT ;
    USE SIGNAL ;
    SHAPE ABUTMENT ;
    PORT
      LAYER M4 ;
      RECT 0 608.160 0.192 608.184 ;
    END
  END tx_flit[166]
  PIN tx_flit[167]
    DIRECTION INPUT ;
    USE SIGNAL ;
    SHAPE ABUTMENT ;
    PORT
      LAYER M4 ;
      RECT 0 608.208 0.192 608.232 ;
    END
  END tx_flit[167]
  PIN tx_flit[168]
    DIRECTION INPUT ;
    USE SIGNAL ;
    SHAPE ABUTMENT ;
    PORT
      LAYER M4 ;
      RECT 0 608.256 0.192 608.280 ;
    END
  END tx_flit[168]
  PIN tx_flit[169]
    DIRECTION INPUT ;
    USE SIGNAL ;
    SHAPE ABUTMENT ;
    PORT
      LAYER M4 ;
      RECT 0 608.304 0.192 608.328 ;
    END
  END tx_flit[169]
  PIN tx_flit[170]
    DIRECTION INPUT ;
    USE SIGNAL ;
    SHAPE ABUTMENT ;
    PORT
      LAYER M4 ;
      RECT 0 608.352 0.192 608.376 ;
    END
  END tx_flit[170]
  PIN tx_flit[171]
    DIRECTION INPUT ;
    USE SIGNAL ;
    SHAPE ABUTMENT ;
    PORT
      LAYER M4 ;
      RECT 0 608.400 0.192 608.424 ;
    END
  END tx_flit[171]
  PIN tx_flit[172]
    DIRECTION INPUT ;
    USE SIGNAL ;
    SHAPE ABUTMENT ;
    PORT
      LAYER M4 ;
      RECT 0 608.448 0.192 608.472 ;
    END
  END tx_flit[172]
  PIN tx_flit[173]
    DIRECTION INPUT ;
    USE SIGNAL ;
    SHAPE ABUTMENT ;
    PORT
      LAYER M4 ;
      RECT 0 608.496 0.192 608.520 ;
    END
  END tx_flit[173]
  PIN tx_flit[174]
    DIRECTION INPUT ;
    USE SIGNAL ;
    SHAPE ABUTMENT ;
    PORT
      LAYER M4 ;
      RECT 0 608.544 0.192 608.568 ;
    END
  END tx_flit[174]
  PIN tx_flit[175]
    DIRECTION INPUT ;
    USE SIGNAL ;
    SHAPE ABUTMENT ;
    PORT
      LAYER M4 ;
      RECT 0 608.592 0.192 608.616 ;
    END
  END tx_flit[175]
  PIN tx_flit[176]
    DIRECTION INPUT ;
    USE SIGNAL ;
    SHAPE ABUTMENT ;
    PORT
      LAYER M4 ;
      RECT 0 608.640 0.192 608.664 ;
    END
  END tx_flit[176]
  PIN tx_flit[177]
    DIRECTION INPUT ;
    USE SIGNAL ;
    SHAPE ABUTMENT ;
    PORT
      LAYER M4 ;
      RECT 0 608.688 0.192 608.712 ;
    END
  END tx_flit[177]
  PIN tx_flit[178]
    DIRECTION INPUT ;
    USE SIGNAL ;
    SHAPE ABUTMENT ;
    PORT
      LAYER M4 ;
      RECT 0 608.736 0.192 608.760 ;
    END
  END tx_flit[178]
  PIN tx_flit[179]
    DIRECTION INPUT ;
    USE SIGNAL ;
    SHAPE ABUTMENT ;
    PORT
      LAYER M4 ;
      RECT 0 608.784 0.192 608.808 ;
    END
  END tx_flit[179]
  PIN tx_flit[180]
    DIRECTION INPUT ;
    USE SIGNAL ;
    SHAPE ABUTMENT ;
    PORT
      LAYER M4 ;
      RECT 0 608.832 0.192 608.856 ;
    END
  END tx_flit[180]
  PIN tx_flit[181]
    DIRECTION INPUT ;
    USE SIGNAL ;
    SHAPE ABUTMENT ;
    PORT
      LAYER M4 ;
      RECT 0 608.880 0.192 608.904 ;
    END
  END tx_flit[181]
  PIN tx_flit[182]
    DIRECTION INPUT ;
    USE SIGNAL ;
    SHAPE ABUTMENT ;
    PORT
      LAYER M4 ;
      RECT 0 608.928 0.192 608.952 ;
    END
  END tx_flit[182]
  PIN tx_flit[183]
    DIRECTION INPUT ;
    USE SIGNAL ;
    SHAPE ABUTMENT ;
    PORT
      LAYER M4 ;
      RECT 0 608.976 0.192 609.000 ;
    END
  END tx_flit[183]
  PIN tx_flit[184]
    DIRECTION INPUT ;
    USE SIGNAL ;
    SHAPE ABUTMENT ;
    PORT
      LAYER M4 ;
      RECT 0 609.024 0.192 609.048 ;
    END
  END tx_flit[184]
  PIN tx_flit[185]
    DIRECTION INPUT ;
    USE SIGNAL ;
    SHAPE ABUTMENT ;
    PORT
      LAYER M4 ;
      RECT 0 609.072 0.192 609.096 ;
    END
  END tx_flit[185]
  PIN tx_flit[186]
    DIRECTION INPUT ;
    USE SIGNAL ;
    SHAPE ABUTMENT ;
    PORT
      LAYER M4 ;
      RECT 0 609.120 0.192 609.144 ;
    END
  END tx_flit[186]
  PIN tx_flit[187]
    DIRECTION INPUT ;
    USE SIGNAL ;
    SHAPE ABUTMENT ;
    PORT
      LAYER M4 ;
      RECT 0 609.168 0.192 609.192 ;
    END
  END tx_flit[187]
  PIN tx_flit[188]
    DIRECTION INPUT ;
    USE SIGNAL ;
    SHAPE ABUTMENT ;
    PORT
      LAYER M4 ;
      RECT 0 609.216 0.192 609.240 ;
    END
  END tx_flit[188]
  PIN tx_flit[189]
    DIRECTION INPUT ;
    USE SIGNAL ;
    SHAPE ABUTMENT ;
    PORT
      LAYER M4 ;
      RECT 0 609.264 0.192 609.288 ;
    END
  END tx_flit[189]
  PIN tx_flit[190]
    DIRECTION INPUT ;
    USE SIGNAL ;
    SHAPE ABUTMENT ;
    PORT
      LAYER M4 ;
      RECT 0 609.312 0.192 609.336 ;
    END
  END tx_flit[190]
  PIN tx_flit[191]
    DIRECTION INPUT ;
    USE SIGNAL ;
    SHAPE ABUTMENT ;
    PORT
      LAYER M4 ;
      RECT 0 609.360 0.192 609.384 ;
    END
  END tx_flit[191]
  PIN tx_flit[192]
    DIRECTION INPUT ;
    USE SIGNAL ;
    SHAPE ABUTMENT ;
    PORT
      LAYER M4 ;
      RECT 0 609.408 0.192 609.432 ;
    END
  END tx_flit[192]
  PIN tx_flit[193]
    DIRECTION INPUT ;
    USE SIGNAL ;
    SHAPE ABUTMENT ;
    PORT
      LAYER M4 ;
      RECT 0 609.456 0.192 609.480 ;
    END
  END tx_flit[193]
  PIN tx_flit[194]
    DIRECTION INPUT ;
    USE SIGNAL ;
    SHAPE ABUTMENT ;
    PORT
      LAYER M4 ;
      RECT 0 609.504 0.192 609.528 ;
    END
  END tx_flit[194]
  PIN tx_flit[195]
    DIRECTION INPUT ;
    USE SIGNAL ;
    SHAPE ABUTMENT ;
    PORT
      LAYER M4 ;
      RECT 0 609.552 0.192 609.576 ;
    END
  END tx_flit[195]
  PIN tx_flit[196]
    DIRECTION INPUT ;
    USE SIGNAL ;
    SHAPE ABUTMENT ;
    PORT
      LAYER M4 ;
      RECT 0 609.600 0.192 609.624 ;
    END
  END tx_flit[196]
  PIN tx_flit[197]
    DIRECTION INPUT ;
    USE SIGNAL ;
    SHAPE ABUTMENT ;
    PORT
      LAYER M4 ;
      RECT 0 609.648 0.192 609.672 ;
    END
  END tx_flit[197]
  PIN tx_flit[198]
    DIRECTION INPUT ;
    USE SIGNAL ;
    SHAPE ABUTMENT ;
    PORT
      LAYER M4 ;
      RECT 0 609.696 0.192 609.720 ;
    END
  END tx_flit[198]
  PIN tx_flit[199]
    DIRECTION INPUT ;
    USE SIGNAL ;
    SHAPE ABUTMENT ;
    PORT
      LAYER M4 ;
      RECT 0 609.744 0.192 609.768 ;
    END
  END tx_flit[199]
  PIN tx_flit[200]
    DIRECTION INPUT ;
    USE SIGNAL ;
    SHAPE ABUTMENT ;
    PORT
      LAYER M4 ;
      RECT 0 609.792 0.192 609.816 ;
    END
  END tx_flit[200]
  PIN tx_flit[201]
    DIRECTION INPUT ;
    USE SIGNAL ;
    SHAPE ABUTMENT ;
    PORT
      LAYER M4 ;
      RECT 0 609.840 0.192 609.864 ;
    END
  END tx_flit[201]
  PIN tx_flit[202]
    DIRECTION INPUT ;
    USE SIGNAL ;
    SHAPE ABUTMENT ;
    PORT
      LAYER M4 ;
      RECT 0 609.888 0.192 609.912 ;
    END
  END tx_flit[202]
  PIN tx_flit[203]
    DIRECTION INPUT ;
    USE SIGNAL ;
    SHAPE ABUTMENT ;
    PORT
      LAYER M4 ;
      RECT 0 609.936 0.192 609.960 ;
    END
  END tx_flit[203]
  PIN tx_flit[204]
    DIRECTION INPUT ;
    USE SIGNAL ;
    SHAPE ABUTMENT ;
    PORT
      LAYER M4 ;
      RECT 0 609.984 0.192 610.008 ;
    END
  END tx_flit[204]
  PIN tx_flit[205]
    DIRECTION INPUT ;
    USE SIGNAL ;
    SHAPE ABUTMENT ;
    PORT
      LAYER M4 ;
      RECT 0 610.032 0.192 610.056 ;
    END
  END tx_flit[205]
  PIN tx_flit[206]
    DIRECTION INPUT ;
    USE SIGNAL ;
    SHAPE ABUTMENT ;
    PORT
      LAYER M4 ;
      RECT 0 610.080 0.192 610.104 ;
    END
  END tx_flit[206]
  PIN tx_flit[207]
    DIRECTION INPUT ;
    USE SIGNAL ;
    SHAPE ABUTMENT ;
    PORT
      LAYER M4 ;
      RECT 0 610.128 0.192 610.152 ;
    END
  END tx_flit[207]
  PIN tx_flit[208]
    DIRECTION INPUT ;
    USE SIGNAL ;
    SHAPE ABUTMENT ;
    PORT
      LAYER M4 ;
      RECT 0 610.176 0.192 610.200 ;
    END
  END tx_flit[208]
  PIN tx_flit[209]
    DIRECTION INPUT ;
    USE SIGNAL ;
    SHAPE ABUTMENT ;
    PORT
      LAYER M4 ;
      RECT 0 610.224 0.192 610.248 ;
    END
  END tx_flit[209]
  PIN tx_flit[210]
    DIRECTION INPUT ;
    USE SIGNAL ;
    SHAPE ABUTMENT ;
    PORT
      LAYER M4 ;
      RECT 0 610.272 0.192 610.296 ;
    END
  END tx_flit[210]
  PIN tx_flit[211]
    DIRECTION INPUT ;
    USE SIGNAL ;
    SHAPE ABUTMENT ;
    PORT
      LAYER M4 ;
      RECT 0 610.320 0.192 610.344 ;
    END
  END tx_flit[211]
  PIN tx_flit[212]
    DIRECTION INPUT ;
    USE SIGNAL ;
    SHAPE ABUTMENT ;
    PORT
      LAYER M4 ;
      RECT 0 610.368 0.192 610.392 ;
    END
  END tx_flit[212]
  PIN tx_flit[213]
    DIRECTION INPUT ;
    USE SIGNAL ;
    SHAPE ABUTMENT ;
    PORT
      LAYER M4 ;
      RECT 0 610.416 0.192 610.440 ;
    END
  END tx_flit[213]
  PIN tx_flit[214]
    DIRECTION INPUT ;
    USE SIGNAL ;
    SHAPE ABUTMENT ;
    PORT
      LAYER M4 ;
      RECT 0 610.464 0.192 610.488 ;
    END
  END tx_flit[214]
  PIN tx_flit[215]
    DIRECTION INPUT ;
    USE SIGNAL ;
    SHAPE ABUTMENT ;
    PORT
      LAYER M4 ;
      RECT 0 610.512 0.192 610.536 ;
    END
  END tx_flit[215]
  PIN tx_flit[216]
    DIRECTION INPUT ;
    USE SIGNAL ;
    SHAPE ABUTMENT ;
    PORT
      LAYER M4 ;
      RECT 0 610.560 0.192 610.584 ;
    END
  END tx_flit[216]
  PIN tx_flit[217]
    DIRECTION INPUT ;
    USE SIGNAL ;
    SHAPE ABUTMENT ;
    PORT
      LAYER M4 ;
      RECT 0 610.608 0.192 610.632 ;
    END
  END tx_flit[217]
  PIN tx_flit[218]
    DIRECTION INPUT ;
    USE SIGNAL ;
    SHAPE ABUTMENT ;
    PORT
      LAYER M4 ;
      RECT 0 610.656 0.192 610.680 ;
    END
  END tx_flit[218]
  PIN tx_flit[219]
    DIRECTION INPUT ;
    USE SIGNAL ;
    SHAPE ABUTMENT ;
    PORT
      LAYER M4 ;
      RECT 0 610.704 0.192 610.728 ;
    END
  END tx_flit[219]
  PIN tx_flit[220]
    DIRECTION INPUT ;
    USE SIGNAL ;
    SHAPE ABUTMENT ;
    PORT
      LAYER M4 ;
      RECT 0 610.752 0.192 610.776 ;
    END
  END tx_flit[220]
  PIN tx_flit[221]
    DIRECTION INPUT ;
    USE SIGNAL ;
    SHAPE ABUTMENT ;
    PORT
      LAYER M4 ;
      RECT 0 610.800 0.192 610.824 ;
    END
  END tx_flit[221]
  PIN tx_flit[222]
    DIRECTION INPUT ;
    USE SIGNAL ;
    SHAPE ABUTMENT ;
    PORT
      LAYER M4 ;
      RECT 0 610.848 0.192 610.872 ;
    END
  END tx_flit[222]
  PIN tx_flit[223]
    DIRECTION INPUT ;
    USE SIGNAL ;
    SHAPE ABUTMENT ;
    PORT
      LAYER M4 ;
      RECT 0 610.896 0.192 610.920 ;
    END
  END tx_flit[223]
  PIN tx_flit[224]
    DIRECTION INPUT ;
    USE SIGNAL ;
    SHAPE ABUTMENT ;
    PORT
      LAYER M4 ;
      RECT 0 610.944 0.192 610.968 ;
    END
  END tx_flit[224]
  PIN tx_flit[225]
    DIRECTION INPUT ;
    USE SIGNAL ;
    SHAPE ABUTMENT ;
    PORT
      LAYER M4 ;
      RECT 0 610.992 0.192 611.016 ;
    END
  END tx_flit[225]
  PIN tx_flit[226]
    DIRECTION INPUT ;
    USE SIGNAL ;
    SHAPE ABUTMENT ;
    PORT
      LAYER M4 ;
      RECT 0 611.040 0.192 611.064 ;
    END
  END tx_flit[226]
  PIN tx_flit[227]
    DIRECTION INPUT ;
    USE SIGNAL ;
    SHAPE ABUTMENT ;
    PORT
      LAYER M4 ;
      RECT 0 611.088 0.192 611.112 ;
    END
  END tx_flit[227]
  PIN tx_flit[228]
    DIRECTION INPUT ;
    USE SIGNAL ;
    SHAPE ABUTMENT ;
    PORT
      LAYER M4 ;
      RECT 0 611.136 0.192 611.160 ;
    END
  END tx_flit[228]
  PIN tx_flit[229]
    DIRECTION INPUT ;
    USE SIGNAL ;
    SHAPE ABUTMENT ;
    PORT
      LAYER M4 ;
      RECT 0 611.184 0.192 611.208 ;
    END
  END tx_flit[229]
  PIN tx_flit[230]
    DIRECTION INPUT ;
    USE SIGNAL ;
    SHAPE ABUTMENT ;
    PORT
      LAYER M4 ;
      RECT 0 611.232 0.192 611.256 ;
    END
  END tx_flit[230]
  PIN tx_flit[231]
    DIRECTION INPUT ;
    USE SIGNAL ;
    SHAPE ABUTMENT ;
    PORT
      LAYER M4 ;
      RECT 0 611.280 0.192 611.304 ;
    END
  END tx_flit[231]
  PIN tx_flit[232]
    DIRECTION INPUT ;
    USE SIGNAL ;
    SHAPE ABUTMENT ;
    PORT
      LAYER M4 ;
      RECT 0 611.328 0.192 611.352 ;
    END
  END tx_flit[232]
  PIN tx_flit[233]
    DIRECTION INPUT ;
    USE SIGNAL ;
    SHAPE ABUTMENT ;
    PORT
      LAYER M4 ;
      RECT 0 611.376 0.192 611.400 ;
    END
  END tx_flit[233]
  PIN tx_flit[234]
    DIRECTION INPUT ;
    USE SIGNAL ;
    SHAPE ABUTMENT ;
    PORT
      LAYER M4 ;
      RECT 0 611.424 0.192 611.448 ;
    END
  END tx_flit[234]
  PIN tx_flit[235]
    DIRECTION INPUT ;
    USE SIGNAL ;
    SHAPE ABUTMENT ;
    PORT
      LAYER M4 ;
      RECT 0 611.472 0.192 611.496 ;
    END
  END tx_flit[235]
  PIN tx_flit[236]
    DIRECTION INPUT ;
    USE SIGNAL ;
    SHAPE ABUTMENT ;
    PORT
      LAYER M4 ;
      RECT 0 611.520 0.192 611.544 ;
    END
  END tx_flit[236]
  PIN tx_flit[237]
    DIRECTION INPUT ;
    USE SIGNAL ;
    SHAPE ABUTMENT ;
    PORT
      LAYER M4 ;
      RECT 0 611.568 0.192 611.592 ;
    END
  END tx_flit[237]
  PIN tx_flit[238]
    DIRECTION INPUT ;
    USE SIGNAL ;
    SHAPE ABUTMENT ;
    PORT
      LAYER M4 ;
      RECT 0 611.616 0.192 611.640 ;
    END
  END tx_flit[238]
  PIN tx_flit[239]
    DIRECTION INPUT ;
    USE SIGNAL ;
    SHAPE ABUTMENT ;
    PORT
      LAYER M4 ;
      RECT 0 611.664 0.192 611.688 ;
    END
  END tx_flit[239]
  PIN tx_flit[240]
    DIRECTION INPUT ;
    USE SIGNAL ;
    SHAPE ABUTMENT ;
    PORT
      LAYER M4 ;
      RECT 0 611.712 0.192 611.736 ;
    END
  END tx_flit[240]
  PIN tx_flit[241]
    DIRECTION INPUT ;
    USE SIGNAL ;
    SHAPE ABUTMENT ;
    PORT
      LAYER M4 ;
      RECT 0 611.760 0.192 611.784 ;
    END
  END tx_flit[241]
  PIN tx_flit[242]
    DIRECTION INPUT ;
    USE SIGNAL ;
    SHAPE ABUTMENT ;
    PORT
      LAYER M4 ;
      RECT 0 611.808 0.192 611.832 ;
    END
  END tx_flit[242]
  PIN tx_flit[243]
    DIRECTION INPUT ;
    USE SIGNAL ;
    SHAPE ABUTMENT ;
    PORT
      LAYER M4 ;
      RECT 0 611.856 0.192 611.880 ;
    END
  END tx_flit[243]
  PIN tx_flit[244]
    DIRECTION INPUT ;
    USE SIGNAL ;
    SHAPE ABUTMENT ;
    PORT
      LAYER M4 ;
      RECT 0 611.904 0.192 611.928 ;
    END
  END tx_flit[244]
  PIN tx_flit[245]
    DIRECTION INPUT ;
    USE SIGNAL ;
    SHAPE ABUTMENT ;
    PORT
      LAYER M4 ;
      RECT 0 611.952 0.192 611.976 ;
    END
  END tx_flit[245]
  PIN tx_flit[246]
    DIRECTION INPUT ;
    USE SIGNAL ;
    SHAPE ABUTMENT ;
    PORT
      LAYER M4 ;
      RECT 0 612.000 0.192 612.024 ;
    END
  END tx_flit[246]
  PIN tx_flit[247]
    DIRECTION INPUT ;
    USE SIGNAL ;
    SHAPE ABUTMENT ;
    PORT
      LAYER M4 ;
      RECT 0 612.048 0.192 612.072 ;
    END
  END tx_flit[247]
  PIN tx_flit[248]
    DIRECTION INPUT ;
    USE SIGNAL ;
    SHAPE ABUTMENT ;
    PORT
      LAYER M4 ;
      RECT 0 612.096 0.192 612.120 ;
    END
  END tx_flit[248]
  PIN tx_flit[249]
    DIRECTION INPUT ;
    USE SIGNAL ;
    SHAPE ABUTMENT ;
    PORT
      LAYER M4 ;
      RECT 0 612.144 0.192 612.168 ;
    END
  END tx_flit[249]
  PIN tx_flit[250]
    DIRECTION INPUT ;
    USE SIGNAL ;
    SHAPE ABUTMENT ;
    PORT
      LAYER M4 ;
      RECT 0 612.192 0.192 612.216 ;
    END
  END tx_flit[250]
  PIN tx_flit[251]
    DIRECTION INPUT ;
    USE SIGNAL ;
    SHAPE ABUTMENT ;
    PORT
      LAYER M4 ;
      RECT 0 612.240 0.192 612.264 ;
    END
  END tx_flit[251]
  PIN tx_flit[252]
    DIRECTION INPUT ;
    USE SIGNAL ;
    SHAPE ABUTMENT ;
    PORT
      LAYER M4 ;
      RECT 0 612.288 0.192 612.312 ;
    END
  END tx_flit[252]
  PIN tx_flit[253]
    DIRECTION INPUT ;
    USE SIGNAL ;
    SHAPE ABUTMENT ;
    PORT
      LAYER M4 ;
      RECT 0 612.336 0.192 612.360 ;
    END
  END tx_flit[253]
  PIN tx_flit[254]
    DIRECTION INPUT ;
    USE SIGNAL ;
    SHAPE ABUTMENT ;
    PORT
      LAYER M4 ;
      RECT 0 612.384 0.192 612.408 ;
    END
  END tx_flit[254]
  PIN tx_flit[255]
    DIRECTION INPUT ;
    USE SIGNAL ;
    SHAPE ABUTMENT ;
    PORT
      LAYER M4 ;
      RECT 0 612.432 0.192 612.456 ;
    END
  END tx_flit[255]
  PIN tx_flit[256]
    DIRECTION INPUT ;
    USE SIGNAL ;
    SHAPE ABUTMENT ;
    PORT
      LAYER M4 ;
      RECT 0 612.480 0.192 612.504 ;
    END
  END tx_flit[256]
  PIN tx_flit[257]
    DIRECTION INPUT ;
    USE SIGNAL ;
    SHAPE ABUTMENT ;
    PORT
      LAYER M4 ;
      RECT 0 612.528 0.192 612.552 ;
    END
  END tx_flit[257]
  PIN tx_flit[258]
    DIRECTION INPUT ;
    USE SIGNAL ;
    SHAPE ABUTMENT ;
    PORT
      LAYER M4 ;
      RECT 0 612.576 0.192 612.600 ;
    END
  END tx_flit[258]
  PIN tx_flit[259]
    DIRECTION INPUT ;
    USE SIGNAL ;
    SHAPE ABUTMENT ;
    PORT
      LAYER M4 ;
      RECT 0 612.624 0.192 612.648 ;
    END
  END tx_flit[259]
  PIN tx_flit[260]
    DIRECTION INPUT ;
    USE SIGNAL ;
    SHAPE ABUTMENT ;
    PORT
      LAYER M4 ;
      RECT 0 612.672 0.192 612.696 ;
    END
  END tx_flit[260]
  PIN tx_flit[261]
    DIRECTION INPUT ;
    USE SIGNAL ;
    SHAPE ABUTMENT ;
    PORT
      LAYER M4 ;
      RECT 0 612.720 0.192 612.744 ;
    END
  END tx_flit[261]
  PIN tx_flit[262]
    DIRECTION INPUT ;
    USE SIGNAL ;
    SHAPE ABUTMENT ;
    PORT
      LAYER M4 ;
      RECT 0 612.768 0.192 612.792 ;
    END
  END tx_flit[262]
  PIN tx_flit[263]
    DIRECTION INPUT ;
    USE SIGNAL ;
    SHAPE ABUTMENT ;
    PORT
      LAYER M4 ;
      RECT 0 612.816 0.192 612.840 ;
    END
  END tx_flit[263]
  PIN tx_flit[264]
    DIRECTION INPUT ;
    USE SIGNAL ;
    SHAPE ABUTMENT ;
    PORT
      LAYER M4 ;
      RECT 0 612.864 0.192 612.888 ;
    END
  END tx_flit[264]
  PIN tx_flit[265]
    DIRECTION INPUT ;
    USE SIGNAL ;
    SHAPE ABUTMENT ;
    PORT
      LAYER M4 ;
      RECT 0 612.912 0.192 612.936 ;
    END
  END tx_flit[265]
  PIN tx_flit[266]
    DIRECTION INPUT ;
    USE SIGNAL ;
    SHAPE ABUTMENT ;
    PORT
      LAYER M4 ;
      RECT 0 612.960 0.192 612.984 ;
    END
  END tx_flit[266]
  PIN tx_flit[267]
    DIRECTION INPUT ;
    USE SIGNAL ;
    SHAPE ABUTMENT ;
    PORT
      LAYER M4 ;
      RECT 0 613.008 0.192 613.032 ;
    END
  END tx_flit[267]
  PIN tx_flit[268]
    DIRECTION INPUT ;
    USE SIGNAL ;
    SHAPE ABUTMENT ;
    PORT
      LAYER M4 ;
      RECT 0 613.056 0.192 613.080 ;
    END
  END tx_flit[268]
  PIN tx_flit[269]
    DIRECTION INPUT ;
    USE SIGNAL ;
    SHAPE ABUTMENT ;
    PORT
      LAYER M4 ;
      RECT 0 613.104 0.192 613.128 ;
    END
  END tx_flit[269]
  PIN tx_flit[270]
    DIRECTION INPUT ;
    USE SIGNAL ;
    SHAPE ABUTMENT ;
    PORT
      LAYER M4 ;
      RECT 0 613.152 0.192 613.176 ;
    END
  END tx_flit[270]
  PIN tx_flit[271]
    DIRECTION INPUT ;
    USE SIGNAL ;
    SHAPE ABUTMENT ;
    PORT
      LAYER M4 ;
      RECT 0 613.200 0.192 613.224 ;
    END
  END tx_flit[271]
  PIN tx_flit[272]
    DIRECTION INPUT ;
    USE SIGNAL ;
    SHAPE ABUTMENT ;
    PORT
      LAYER M4 ;
      RECT 0 613.248 0.192 613.272 ;
    END
  END tx_flit[272]
  PIN tx_flit[273]
    DIRECTION INPUT ;
    USE SIGNAL ;
    SHAPE ABUTMENT ;
    PORT
      LAYER M4 ;
      RECT 0 613.296 0.192 613.320 ;
    END
  END tx_flit[273]
  PIN tx_flit[274]
    DIRECTION INPUT ;
    USE SIGNAL ;
    SHAPE ABUTMENT ;
    PORT
      LAYER M4 ;
      RECT 0 613.344 0.192 613.368 ;
    END
  END tx_flit[274]
  PIN tx_flit[275]
    DIRECTION INPUT ;
    USE SIGNAL ;
    SHAPE ABUTMENT ;
    PORT
      LAYER M4 ;
      RECT 0 613.392 0.192 613.416 ;
    END
  END tx_flit[275]
  PIN tx_flit[276]
    DIRECTION INPUT ;
    USE SIGNAL ;
    SHAPE ABUTMENT ;
    PORT
      LAYER M4 ;
      RECT 0 613.440 0.192 613.464 ;
    END
  END tx_flit[276]
  PIN tx_flit[277]
    DIRECTION INPUT ;
    USE SIGNAL ;
    SHAPE ABUTMENT ;
    PORT
      LAYER M4 ;
      RECT 0 613.488 0.192 613.512 ;
    END
  END tx_flit[277]
  PIN tx_flit[278]
    DIRECTION INPUT ;
    USE SIGNAL ;
    SHAPE ABUTMENT ;
    PORT
      LAYER M4 ;
      RECT 0 613.536 0.192 613.560 ;
    END
  END tx_flit[278]
  PIN tx_flit[279]
    DIRECTION INPUT ;
    USE SIGNAL ;
    SHAPE ABUTMENT ;
    PORT
      LAYER M4 ;
      RECT 0 613.584 0.192 613.608 ;
    END
  END tx_flit[279]
  PIN tx_flit[280]
    DIRECTION INPUT ;
    USE SIGNAL ;
    SHAPE ABUTMENT ;
    PORT
      LAYER M4 ;
      RECT 0 613.632 0.192 613.656 ;
    END
  END tx_flit[280]
  PIN tx_flit[281]
    DIRECTION INPUT ;
    USE SIGNAL ;
    SHAPE ABUTMENT ;
    PORT
      LAYER M4 ;
      RECT 0 613.680 0.192 613.704 ;
    END
  END tx_flit[281]
  PIN tx_flit[282]
    DIRECTION INPUT ;
    USE SIGNAL ;
    SHAPE ABUTMENT ;
    PORT
      LAYER M4 ;
      RECT 0 613.728 0.192 613.752 ;
    END
  END tx_flit[282]
  PIN tx_flit[283]
    DIRECTION INPUT ;
    USE SIGNAL ;
    SHAPE ABUTMENT ;
    PORT
      LAYER M4 ;
      RECT 0 613.776 0.192 613.800 ;
    END
  END tx_flit[283]
  PIN tx_flit[284]
    DIRECTION INPUT ;
    USE SIGNAL ;
    SHAPE ABUTMENT ;
    PORT
      LAYER M4 ;
      RECT 0 613.824 0.192 613.848 ;
    END
  END tx_flit[284]
  PIN tx_flit[285]
    DIRECTION INPUT ;
    USE SIGNAL ;
    SHAPE ABUTMENT ;
    PORT
      LAYER M4 ;
      RECT 0 613.872 0.192 613.896 ;
    END
  END tx_flit[285]
  PIN tx_flit[286]
    DIRECTION INPUT ;
    USE SIGNAL ;
    SHAPE ABUTMENT ;
    PORT
      LAYER M4 ;
      RECT 0 613.920 0.192 613.944 ;
    END
  END tx_flit[286]
  PIN tx_flit[287]
    DIRECTION INPUT ;
    USE SIGNAL ;
    SHAPE ABUTMENT ;
    PORT
      LAYER M4 ;
      RECT 0 613.968 0.192 613.992 ;
    END
  END tx_flit[287]
  PIN tx_flit[288]
    DIRECTION INPUT ;
    USE SIGNAL ;
    SHAPE ABUTMENT ;
    PORT
      LAYER M4 ;
      RECT 0 614.016 0.192 614.040 ;
    END
  END tx_flit[288]
  PIN tx_flit[289]
    DIRECTION INPUT ;
    USE SIGNAL ;
    SHAPE ABUTMENT ;
    PORT
      LAYER M4 ;
      RECT 0 614.064 0.192 614.088 ;
    END
  END tx_flit[289]
  PIN tx_flit[290]
    DIRECTION INPUT ;
    USE SIGNAL ;
    SHAPE ABUTMENT ;
    PORT
      LAYER M4 ;
      RECT 0 614.112 0.192 614.136 ;
    END
  END tx_flit[290]
  PIN tx_flit[291]
    DIRECTION INPUT ;
    USE SIGNAL ;
    SHAPE ABUTMENT ;
    PORT
      LAYER M4 ;
      RECT 0 614.160 0.192 614.184 ;
    END
  END tx_flit[291]
  PIN tx_flit[292]
    DIRECTION INPUT ;
    USE SIGNAL ;
    SHAPE ABUTMENT ;
    PORT
      LAYER M4 ;
      RECT 0 614.208 0.192 614.232 ;
    END
  END tx_flit[292]
  PIN tx_flit[293]
    DIRECTION INPUT ;
    USE SIGNAL ;
    SHAPE ABUTMENT ;
    PORT
      LAYER M4 ;
      RECT 0 614.256 0.192 614.280 ;
    END
  END tx_flit[293]
  PIN tx_flit[294]
    DIRECTION INPUT ;
    USE SIGNAL ;
    SHAPE ABUTMENT ;
    PORT
      LAYER M4 ;
      RECT 0 614.304 0.192 614.328 ;
    END
  END tx_flit[294]
  PIN tx_flit[295]
    DIRECTION INPUT ;
    USE SIGNAL ;
    SHAPE ABUTMENT ;
    PORT
      LAYER M4 ;
      RECT 0 614.352 0.192 614.376 ;
    END
  END tx_flit[295]
  PIN tx_flit[296]
    DIRECTION INPUT ;
    USE SIGNAL ;
    SHAPE ABUTMENT ;
    PORT
      LAYER M4 ;
      RECT 0 614.400 0.192 614.424 ;
    END
  END tx_flit[296]
  PIN tx_flit[297]
    DIRECTION INPUT ;
    USE SIGNAL ;
    SHAPE ABUTMENT ;
    PORT
      LAYER M4 ;
      RECT 0 614.448 0.192 614.472 ;
    END
  END tx_flit[297]
  PIN tx_flit[298]
    DIRECTION INPUT ;
    USE SIGNAL ;
    SHAPE ABUTMENT ;
    PORT
      LAYER M4 ;
      RECT 0 614.496 0.192 614.520 ;
    END
  END tx_flit[298]
  PIN tx_flit[299]
    DIRECTION INPUT ;
    USE SIGNAL ;
    SHAPE ABUTMENT ;
    PORT
      LAYER M4 ;
      RECT 0 614.544 0.192 614.568 ;
    END
  END tx_flit[299]
  PIN tx_flit[300]
    DIRECTION INPUT ;
    USE SIGNAL ;
    SHAPE ABUTMENT ;
    PORT
      LAYER M4 ;
      RECT 0 614.592 0.192 614.616 ;
    END
  END tx_flit[300]
  PIN tx_flit[301]
    DIRECTION INPUT ;
    USE SIGNAL ;
    SHAPE ABUTMENT ;
    PORT
      LAYER M4 ;
      RECT 0 614.640 0.192 614.664 ;
    END
  END tx_flit[301]
  PIN tx_flit[302]
    DIRECTION INPUT ;
    USE SIGNAL ;
    SHAPE ABUTMENT ;
    PORT
      LAYER M4 ;
      RECT 0 614.688 0.192 614.712 ;
    END
  END tx_flit[302]
  PIN tx_flit[303]
    DIRECTION INPUT ;
    USE SIGNAL ;
    SHAPE ABUTMENT ;
    PORT
      LAYER M4 ;
      RECT 0 614.736 0.192 614.760 ;
    END
  END tx_flit[303]
  PIN tx_flit[304]
    DIRECTION INPUT ;
    USE SIGNAL ;
    SHAPE ABUTMENT ;
    PORT
      LAYER M4 ;
      RECT 0 614.784 0.192 614.808 ;
    END
  END tx_flit[304]
  PIN tx_flit[305]
    DIRECTION INPUT ;
    USE SIGNAL ;
    SHAPE ABUTMENT ;
    PORT
      LAYER M4 ;
      RECT 0 614.832 0.192 614.856 ;
    END
  END tx_flit[305]
  PIN tx_flit[306]
    DIRECTION INPUT ;
    USE SIGNAL ;
    SHAPE ABUTMENT ;
    PORT
      LAYER M4 ;
      RECT 0 614.880 0.192 614.904 ;
    END
  END tx_flit[306]
  PIN tx_flit[307]
    DIRECTION INPUT ;
    USE SIGNAL ;
    SHAPE ABUTMENT ;
    PORT
      LAYER M4 ;
      RECT 0 614.928 0.192 614.952 ;
    END
  END tx_flit[307]
  PIN tx_flit[308]
    DIRECTION INPUT ;
    USE SIGNAL ;
    SHAPE ABUTMENT ;
    PORT
      LAYER M4 ;
      RECT 0 614.976 0.192 615.000 ;
    END
  END tx_flit[308]
  PIN tx_flit[309]
    DIRECTION INPUT ;
    USE SIGNAL ;
    SHAPE ABUTMENT ;
    PORT
      LAYER M4 ;
      RECT 0 615.024 0.192 615.048 ;
    END
  END tx_flit[309]
  PIN tx_flit[310]
    DIRECTION INPUT ;
    USE SIGNAL ;
    SHAPE ABUTMENT ;
    PORT
      LAYER M4 ;
      RECT 0 615.072 0.192 615.096 ;
    END
  END tx_flit[310]
  PIN tx_flit[311]
    DIRECTION INPUT ;
    USE SIGNAL ;
    SHAPE ABUTMENT ;
    PORT
      LAYER M4 ;
      RECT 0 615.120 0.192 615.144 ;
    END
  END tx_flit[311]
  PIN tx_flit[312]
    DIRECTION INPUT ;
    USE SIGNAL ;
    SHAPE ABUTMENT ;
    PORT
      LAYER M4 ;
      RECT 0 615.168 0.192 615.192 ;
    END
  END tx_flit[312]
  PIN tx_flit[313]
    DIRECTION INPUT ;
    USE SIGNAL ;
    SHAPE ABUTMENT ;
    PORT
      LAYER M4 ;
      RECT 0 615.216 0.192 615.240 ;
    END
  END tx_flit[313]
  PIN tx_flit[314]
    DIRECTION INPUT ;
    USE SIGNAL ;
    SHAPE ABUTMENT ;
    PORT
      LAYER M4 ;
      RECT 0 615.264 0.192 615.288 ;
    END
  END tx_flit[314]
  PIN tx_flit[315]
    DIRECTION INPUT ;
    USE SIGNAL ;
    SHAPE ABUTMENT ;
    PORT
      LAYER M4 ;
      RECT 0 615.312 0.192 615.336 ;
    END
  END tx_flit[315]
  PIN tx_flit[316]
    DIRECTION INPUT ;
    USE SIGNAL ;
    SHAPE ABUTMENT ;
    PORT
      LAYER M4 ;
      RECT 0 615.360 0.192 615.384 ;
    END
  END tx_flit[316]
  PIN tx_flit[317]
    DIRECTION INPUT ;
    USE SIGNAL ;
    SHAPE ABUTMENT ;
    PORT
      LAYER M4 ;
      RECT 0 615.408 0.192 615.432 ;
    END
  END tx_flit[317]
  PIN tx_flit[318]
    DIRECTION INPUT ;
    USE SIGNAL ;
    SHAPE ABUTMENT ;
    PORT
      LAYER M4 ;
      RECT 0 615.456 0.192 615.480 ;
    END
  END tx_flit[318]
  PIN tx_flit[319]
    DIRECTION INPUT ;
    USE SIGNAL ;
    SHAPE ABUTMENT ;
    PORT
      LAYER M4 ;
      RECT 0 615.504 0.192 615.528 ;
    END
  END tx_flit[319]
  PIN tx_flit[320]
    DIRECTION INPUT ;
    USE SIGNAL ;
    SHAPE ABUTMENT ;
    PORT
      LAYER M4 ;
      RECT 0 615.552 0.192 615.576 ;
    END
  END tx_flit[320]
  PIN tx_flit[321]
    DIRECTION INPUT ;
    USE SIGNAL ;
    SHAPE ABUTMENT ;
    PORT
      LAYER M4 ;
      RECT 0 615.600 0.192 615.624 ;
    END
  END tx_flit[321]
  PIN tx_flit[322]
    DIRECTION INPUT ;
    USE SIGNAL ;
    SHAPE ABUTMENT ;
    PORT
      LAYER M4 ;
      RECT 0 615.648 0.192 615.672 ;
    END
  END tx_flit[322]
  PIN tx_flit[323]
    DIRECTION INPUT ;
    USE SIGNAL ;
    SHAPE ABUTMENT ;
    PORT
      LAYER M4 ;
      RECT 0 615.696 0.192 615.720 ;
    END
  END tx_flit[323]
  PIN tx_flit[324]
    DIRECTION INPUT ;
    USE SIGNAL ;
    SHAPE ABUTMENT ;
    PORT
      LAYER M4 ;
      RECT 0 615.744 0.192 615.768 ;
    END
  END tx_flit[324]
  PIN tx_flit[325]
    DIRECTION INPUT ;
    USE SIGNAL ;
    SHAPE ABUTMENT ;
    PORT
      LAYER M4 ;
      RECT 0 615.792 0.192 615.816 ;
    END
  END tx_flit[325]
  PIN tx_flit[326]
    DIRECTION INPUT ;
    USE SIGNAL ;
    SHAPE ABUTMENT ;
    PORT
      LAYER M4 ;
      RECT 0 615.840 0.192 615.864 ;
    END
  END tx_flit[326]
  PIN tx_flit[327]
    DIRECTION INPUT ;
    USE SIGNAL ;
    SHAPE ABUTMENT ;
    PORT
      LAYER M4 ;
      RECT 0 615.888 0.192 615.912 ;
    END
  END tx_flit[327]
  PIN tx_flit[328]
    DIRECTION INPUT ;
    USE SIGNAL ;
    SHAPE ABUTMENT ;
    PORT
      LAYER M4 ;
      RECT 0 615.936 0.192 615.960 ;
    END
  END tx_flit[328]
  PIN tx_flit[329]
    DIRECTION INPUT ;
    USE SIGNAL ;
    SHAPE ABUTMENT ;
    PORT
      LAYER M4 ;
      RECT 0 615.984 0.192 616.008 ;
    END
  END tx_flit[329]
  PIN tx_flit[330]
    DIRECTION INPUT ;
    USE SIGNAL ;
    SHAPE ABUTMENT ;
    PORT
      LAYER M4 ;
      RECT 0 616.032 0.192 616.056 ;
    END
  END tx_flit[330]
  PIN tx_flit[331]
    DIRECTION INPUT ;
    USE SIGNAL ;
    SHAPE ABUTMENT ;
    PORT
      LAYER M4 ;
      RECT 0 616.080 0.192 616.104 ;
    END
  END tx_flit[331]
  PIN tx_flit[332]
    DIRECTION INPUT ;
    USE SIGNAL ;
    SHAPE ABUTMENT ;
    PORT
      LAYER M4 ;
      RECT 0 616.128 0.192 616.152 ;
    END
  END tx_flit[332]
  PIN tx_flit[333]
    DIRECTION INPUT ;
    USE SIGNAL ;
    SHAPE ABUTMENT ;
    PORT
      LAYER M4 ;
      RECT 0 616.176 0.192 616.200 ;
    END
  END tx_flit[333]
  PIN tx_flit[334]
    DIRECTION INPUT ;
    USE SIGNAL ;
    SHAPE ABUTMENT ;
    PORT
      LAYER M4 ;
      RECT 0 616.224 0.192 616.248 ;
    END
  END tx_flit[334]
  PIN tx_flit[335]
    DIRECTION INPUT ;
    USE SIGNAL ;
    SHAPE ABUTMENT ;
    PORT
      LAYER M4 ;
      RECT 0 616.272 0.192 616.296 ;
    END
  END tx_flit[335]
  PIN tx_flit[336]
    DIRECTION INPUT ;
    USE SIGNAL ;
    SHAPE ABUTMENT ;
    PORT
      LAYER M4 ;
      RECT 0 616.320 0.192 616.344 ;
    END
  END tx_flit[336]
  PIN tx_flit[337]
    DIRECTION INPUT ;
    USE SIGNAL ;
    SHAPE ABUTMENT ;
    PORT
      LAYER M4 ;
      RECT 0 616.368 0.192 616.392 ;
    END
  END tx_flit[337]
  PIN tx_flit[338]
    DIRECTION INPUT ;
    USE SIGNAL ;
    SHAPE ABUTMENT ;
    PORT
      LAYER M4 ;
      RECT 0 616.416 0.192 616.440 ;
    END
  END tx_flit[338]
  PIN tx_flit[339]
    DIRECTION INPUT ;
    USE SIGNAL ;
    SHAPE ABUTMENT ;
    PORT
      LAYER M4 ;
      RECT 0 616.464 0.192 616.488 ;
    END
  END tx_flit[339]
  PIN tx_flit[340]
    DIRECTION INPUT ;
    USE SIGNAL ;
    SHAPE ABUTMENT ;
    PORT
      LAYER M4 ;
      RECT 0 616.512 0.192 616.536 ;
    END
  END tx_flit[340]
  PIN tx_flit[341]
    DIRECTION INPUT ;
    USE SIGNAL ;
    SHAPE ABUTMENT ;
    PORT
      LAYER M4 ;
      RECT 0 616.560 0.192 616.584 ;
    END
  END tx_flit[341]
  PIN tx_flit[342]
    DIRECTION INPUT ;
    USE SIGNAL ;
    SHAPE ABUTMENT ;
    PORT
      LAYER M4 ;
      RECT 0 616.608 0.192 616.632 ;
    END
  END tx_flit[342]
  PIN tx_flit[343]
    DIRECTION INPUT ;
    USE SIGNAL ;
    SHAPE ABUTMENT ;
    PORT
      LAYER M4 ;
      RECT 0 616.656 0.192 616.680 ;
    END
  END tx_flit[343]
  PIN tx_flit[344]
    DIRECTION INPUT ;
    USE SIGNAL ;
    SHAPE ABUTMENT ;
    PORT
      LAYER M4 ;
      RECT 0 616.704 0.192 616.728 ;
    END
  END tx_flit[344]
  PIN tx_flit[345]
    DIRECTION INPUT ;
    USE SIGNAL ;
    SHAPE ABUTMENT ;
    PORT
      LAYER M4 ;
      RECT 0 616.752 0.192 616.776 ;
    END
  END tx_flit[345]
  PIN tx_flit[346]
    DIRECTION INPUT ;
    USE SIGNAL ;
    SHAPE ABUTMENT ;
    PORT
      LAYER M4 ;
      RECT 0 616.800 0.192 616.824 ;
    END
  END tx_flit[346]
  PIN tx_flit[347]
    DIRECTION INPUT ;
    USE SIGNAL ;
    SHAPE ABUTMENT ;
    PORT
      LAYER M4 ;
      RECT 0 616.848 0.192 616.872 ;
    END
  END tx_flit[347]
  PIN tx_flit[348]
    DIRECTION INPUT ;
    USE SIGNAL ;
    SHAPE ABUTMENT ;
    PORT
      LAYER M4 ;
      RECT 0 616.896 0.192 616.920 ;
    END
  END tx_flit[348]
  PIN tx_flit[349]
    DIRECTION INPUT ;
    USE SIGNAL ;
    SHAPE ABUTMENT ;
    PORT
      LAYER M4 ;
      RECT 0 616.944 0.192 616.968 ;
    END
  END tx_flit[349]
  PIN tx_flit[350]
    DIRECTION INPUT ;
    USE SIGNAL ;
    SHAPE ABUTMENT ;
    PORT
      LAYER M4 ;
      RECT 0 616.992 0.192 617.016 ;
    END
  END tx_flit[350]
  PIN tx_flit[351]
    DIRECTION INPUT ;
    USE SIGNAL ;
    SHAPE ABUTMENT ;
    PORT
      LAYER M4 ;
      RECT 0 617.040 0.192 617.064 ;
    END
  END tx_flit[351]
  PIN tx_flit[352]
    DIRECTION INPUT ;
    USE SIGNAL ;
    SHAPE ABUTMENT ;
    PORT
      LAYER M4 ;
      RECT 0 617.088 0.192 617.112 ;
    END
  END tx_flit[352]
  PIN tx_flit[353]
    DIRECTION INPUT ;
    USE SIGNAL ;
    SHAPE ABUTMENT ;
    PORT
      LAYER M4 ;
      RECT 0 617.136 0.192 617.160 ;
    END
  END tx_flit[353]
  PIN tx_flit[354]
    DIRECTION INPUT ;
    USE SIGNAL ;
    SHAPE ABUTMENT ;
    PORT
      LAYER M4 ;
      RECT 0 617.184 0.192 617.208 ;
    END
  END tx_flit[354]
  PIN tx_flit[355]
    DIRECTION INPUT ;
    USE SIGNAL ;
    SHAPE ABUTMENT ;
    PORT
      LAYER M4 ;
      RECT 0 617.232 0.192 617.256 ;
    END
  END tx_flit[355]
  PIN tx_flit[356]
    DIRECTION INPUT ;
    USE SIGNAL ;
    SHAPE ABUTMENT ;
    PORT
      LAYER M4 ;
      RECT 0 617.280 0.192 617.304 ;
    END
  END tx_flit[356]
  PIN tx_flit[357]
    DIRECTION INPUT ;
    USE SIGNAL ;
    SHAPE ABUTMENT ;
    PORT
      LAYER M4 ;
      RECT 0 617.328 0.192 617.352 ;
    END
  END tx_flit[357]
  PIN tx_flit[358]
    DIRECTION INPUT ;
    USE SIGNAL ;
    SHAPE ABUTMENT ;
    PORT
      LAYER M4 ;
      RECT 0 617.376 0.192 617.400 ;
    END
  END tx_flit[358]
  PIN tx_flit[359]
    DIRECTION INPUT ;
    USE SIGNAL ;
    SHAPE ABUTMENT ;
    PORT
      LAYER M4 ;
      RECT 0 617.424 0.192 617.448 ;
    END
  END tx_flit[359]
  PIN tx_flit[360]
    DIRECTION INPUT ;
    USE SIGNAL ;
    SHAPE ABUTMENT ;
    PORT
      LAYER M4 ;
      RECT 0 617.472 0.192 617.496 ;
    END
  END tx_flit[360]
  PIN tx_flit[361]
    DIRECTION INPUT ;
    USE SIGNAL ;
    SHAPE ABUTMENT ;
    PORT
      LAYER M4 ;
      RECT 0 617.520 0.192 617.544 ;
    END
  END tx_flit[361]
  PIN tx_flit[362]
    DIRECTION INPUT ;
    USE SIGNAL ;
    SHAPE ABUTMENT ;
    PORT
      LAYER M4 ;
      RECT 0 617.568 0.192 617.592 ;
    END
  END tx_flit[362]
  PIN tx_flit[363]
    DIRECTION INPUT ;
    USE SIGNAL ;
    SHAPE ABUTMENT ;
    PORT
      LAYER M4 ;
      RECT 0 617.616 0.192 617.640 ;
    END
  END tx_flit[363]
  PIN tx_flit[364]
    DIRECTION INPUT ;
    USE SIGNAL ;
    SHAPE ABUTMENT ;
    PORT
      LAYER M4 ;
      RECT 0 617.664 0.192 617.688 ;
    END
  END tx_flit[364]
  PIN tx_flit[365]
    DIRECTION INPUT ;
    USE SIGNAL ;
    SHAPE ABUTMENT ;
    PORT
      LAYER M4 ;
      RECT 0 617.712 0.192 617.736 ;
    END
  END tx_flit[365]
  PIN tx_flit[366]
    DIRECTION INPUT ;
    USE SIGNAL ;
    SHAPE ABUTMENT ;
    PORT
      LAYER M4 ;
      RECT 0 617.760 0.192 617.784 ;
    END
  END tx_flit[366]
  PIN tx_flit[367]
    DIRECTION INPUT ;
    USE SIGNAL ;
    SHAPE ABUTMENT ;
    PORT
      LAYER M4 ;
      RECT 0 617.808 0.192 617.832 ;
    END
  END tx_flit[367]
  PIN tx_flit[368]
    DIRECTION INPUT ;
    USE SIGNAL ;
    SHAPE ABUTMENT ;
    PORT
      LAYER M4 ;
      RECT 0 617.856 0.192 617.880 ;
    END
  END tx_flit[368]
  PIN tx_flit[369]
    DIRECTION INPUT ;
    USE SIGNAL ;
    SHAPE ABUTMENT ;
    PORT
      LAYER M4 ;
      RECT 0 617.904 0.192 617.928 ;
    END
  END tx_flit[369]
  PIN tx_flit[370]
    DIRECTION INPUT ;
    USE SIGNAL ;
    SHAPE ABUTMENT ;
    PORT
      LAYER M4 ;
      RECT 0 617.952 0.192 617.976 ;
    END
  END tx_flit[370]
  PIN tx_flit[371]
    DIRECTION INPUT ;
    USE SIGNAL ;
    SHAPE ABUTMENT ;
    PORT
      LAYER M4 ;
      RECT 0 618.000 0.192 618.024 ;
    END
  END tx_flit[371]
  PIN tx_flit[372]
    DIRECTION INPUT ;
    USE SIGNAL ;
    SHAPE ABUTMENT ;
    PORT
      LAYER M4 ;
      RECT 0 618.048 0.192 618.072 ;
    END
  END tx_flit[372]
  PIN tx_flit[373]
    DIRECTION INPUT ;
    USE SIGNAL ;
    SHAPE ABUTMENT ;
    PORT
      LAYER M4 ;
      RECT 0 618.096 0.192 618.120 ;
    END
  END tx_flit[373]
  PIN tx_flit[374]
    DIRECTION INPUT ;
    USE SIGNAL ;
    SHAPE ABUTMENT ;
    PORT
      LAYER M4 ;
      RECT 0 618.144 0.192 618.168 ;
    END
  END tx_flit[374]
  PIN tx_flit[375]
    DIRECTION INPUT ;
    USE SIGNAL ;
    SHAPE ABUTMENT ;
    PORT
      LAYER M4 ;
      RECT 0 618.192 0.192 618.216 ;
    END
  END tx_flit[375]
  PIN tx_flit[376]
    DIRECTION INPUT ;
    USE SIGNAL ;
    SHAPE ABUTMENT ;
    PORT
      LAYER M4 ;
      RECT 0 618.240 0.192 618.264 ;
    END
  END tx_flit[376]
  PIN tx_flit[377]
    DIRECTION INPUT ;
    USE SIGNAL ;
    SHAPE ABUTMENT ;
    PORT
      LAYER M4 ;
      RECT 0 618.288 0.192 618.312 ;
    END
  END tx_flit[377]
  PIN tx_flit[378]
    DIRECTION INPUT ;
    USE SIGNAL ;
    SHAPE ABUTMENT ;
    PORT
      LAYER M4 ;
      RECT 0 618.336 0.192 618.360 ;
    END
  END tx_flit[378]
  PIN tx_flit[379]
    DIRECTION INPUT ;
    USE SIGNAL ;
    SHAPE ABUTMENT ;
    PORT
      LAYER M4 ;
      RECT 0 618.384 0.192 618.408 ;
    END
  END tx_flit[379]
  PIN tx_flit[380]
    DIRECTION INPUT ;
    USE SIGNAL ;
    SHAPE ABUTMENT ;
    PORT
      LAYER M4 ;
      RECT 0 618.432 0.192 618.456 ;
    END
  END tx_flit[380]
  PIN tx_flit[381]
    DIRECTION INPUT ;
    USE SIGNAL ;
    SHAPE ABUTMENT ;
    PORT
      LAYER M4 ;
      RECT 0 618.480 0.192 618.504 ;
    END
  END tx_flit[381]
  PIN tx_flit[382]
    DIRECTION INPUT ;
    USE SIGNAL ;
    SHAPE ABUTMENT ;
    PORT
      LAYER M4 ;
      RECT 0 618.528 0.192 618.552 ;
    END
  END tx_flit[382]
  PIN tx_flit[383]
    DIRECTION INPUT ;
    USE SIGNAL ;
    SHAPE ABUTMENT ;
    PORT
      LAYER M4 ;
      RECT 0 618.576 0.192 618.600 ;
    END
  END tx_flit[383]
  PIN tx_flit[384]
    DIRECTION INPUT ;
    USE SIGNAL ;
    SHAPE ABUTMENT ;
    PORT
      LAYER M4 ;
      RECT 0 618.624 0.192 618.648 ;
    END
  END tx_flit[384]
  PIN tx_flit[385]
    DIRECTION INPUT ;
    USE SIGNAL ;
    SHAPE ABUTMENT ;
    PORT
      LAYER M4 ;
      RECT 0 618.672 0.192 618.696 ;
    END
  END tx_flit[385]
  PIN tx_flit[386]
    DIRECTION INPUT ;
    USE SIGNAL ;
    SHAPE ABUTMENT ;
    PORT
      LAYER M4 ;
      RECT 0 618.720 0.192 618.744 ;
    END
  END tx_flit[386]
  PIN tx_flit[387]
    DIRECTION INPUT ;
    USE SIGNAL ;
    SHAPE ABUTMENT ;
    PORT
      LAYER M4 ;
      RECT 0 618.768 0.192 618.792 ;
    END
  END tx_flit[387]
  PIN tx_flit[388]
    DIRECTION INPUT ;
    USE SIGNAL ;
    SHAPE ABUTMENT ;
    PORT
      LAYER M4 ;
      RECT 0 618.816 0.192 618.840 ;
    END
  END tx_flit[388]
  PIN tx_flit[389]
    DIRECTION INPUT ;
    USE SIGNAL ;
    SHAPE ABUTMENT ;
    PORT
      LAYER M4 ;
      RECT 0 618.864 0.192 618.888 ;
    END
  END tx_flit[389]
  PIN tx_flit[390]
    DIRECTION INPUT ;
    USE SIGNAL ;
    SHAPE ABUTMENT ;
    PORT
      LAYER M4 ;
      RECT 0 618.912 0.192 618.936 ;
    END
  END tx_flit[390]
  PIN tx_flit[391]
    DIRECTION INPUT ;
    USE SIGNAL ;
    SHAPE ABUTMENT ;
    PORT
      LAYER M4 ;
      RECT 0 618.960 0.192 618.984 ;
    END
  END tx_flit[391]
  PIN tx_flit[392]
    DIRECTION INPUT ;
    USE SIGNAL ;
    SHAPE ABUTMENT ;
    PORT
      LAYER M4 ;
      RECT 0 619.008 0.192 619.032 ;
    END
  END tx_flit[392]
  PIN tx_flit[393]
    DIRECTION INPUT ;
    USE SIGNAL ;
    SHAPE ABUTMENT ;
    PORT
      LAYER M4 ;
      RECT 0 619.056 0.192 619.080 ;
    END
  END tx_flit[393]
  PIN tx_flit[394]
    DIRECTION INPUT ;
    USE SIGNAL ;
    SHAPE ABUTMENT ;
    PORT
      LAYER M4 ;
      RECT 0 619.104 0.192 619.128 ;
    END
  END tx_flit[394]
  PIN tx_flit[395]
    DIRECTION INPUT ;
    USE SIGNAL ;
    SHAPE ABUTMENT ;
    PORT
      LAYER M4 ;
      RECT 0 619.152 0.192 619.176 ;
    END
  END tx_flit[395]
  PIN tx_flit[396]
    DIRECTION INPUT ;
    USE SIGNAL ;
    SHAPE ABUTMENT ;
    PORT
      LAYER M4 ;
      RECT 0 619.200 0.192 619.224 ;
    END
  END tx_flit[396]
  PIN tx_flit[397]
    DIRECTION INPUT ;
    USE SIGNAL ;
    SHAPE ABUTMENT ;
    PORT
      LAYER M4 ;
      RECT 0 619.248 0.192 619.272 ;
    END
  END tx_flit[397]
  PIN tx_flit[398]
    DIRECTION INPUT ;
    USE SIGNAL ;
    SHAPE ABUTMENT ;
    PORT
      LAYER M4 ;
      RECT 0 619.296 0.192 619.320 ;
    END
  END tx_flit[398]
  PIN tx_flit[399]
    DIRECTION INPUT ;
    USE SIGNAL ;
    SHAPE ABUTMENT ;
    PORT
      LAYER M4 ;
      RECT 0 619.344 0.192 619.368 ;
    END
  END tx_flit[399]
  PIN tx_flit[400]
    DIRECTION INPUT ;
    USE SIGNAL ;
    SHAPE ABUTMENT ;
    PORT
      LAYER M4 ;
      RECT 0 619.392 0.192 619.416 ;
    END
  END tx_flit[400]
  PIN tx_flit[401]
    DIRECTION INPUT ;
    USE SIGNAL ;
    SHAPE ABUTMENT ;
    PORT
      LAYER M4 ;
      RECT 0 619.440 0.192 619.464 ;
    END
  END tx_flit[401]
  PIN tx_flit[402]
    DIRECTION INPUT ;
    USE SIGNAL ;
    SHAPE ABUTMENT ;
    PORT
      LAYER M4 ;
      RECT 0 619.488 0.192 619.512 ;
    END
  END tx_flit[402]
  PIN tx_flit[403]
    DIRECTION INPUT ;
    USE SIGNAL ;
    SHAPE ABUTMENT ;
    PORT
      LAYER M4 ;
      RECT 0 619.536 0.192 619.560 ;
    END
  END tx_flit[403]
  PIN tx_flit[404]
    DIRECTION INPUT ;
    USE SIGNAL ;
    SHAPE ABUTMENT ;
    PORT
      LAYER M4 ;
      RECT 0 619.584 0.192 619.608 ;
    END
  END tx_flit[404]
  PIN tx_flit[405]
    DIRECTION INPUT ;
    USE SIGNAL ;
    SHAPE ABUTMENT ;
    PORT
      LAYER M4 ;
      RECT 0 619.632 0.192 619.656 ;
    END
  END tx_flit[405]
  PIN tx_flit[406]
    DIRECTION INPUT ;
    USE SIGNAL ;
    SHAPE ABUTMENT ;
    PORT
      LAYER M4 ;
      RECT 0 619.680 0.192 619.704 ;
    END
  END tx_flit[406]
  PIN tx_flit[407]
    DIRECTION INPUT ;
    USE SIGNAL ;
    SHAPE ABUTMENT ;
    PORT
      LAYER M4 ;
      RECT 0 619.728 0.192 619.752 ;
    END
  END tx_flit[407]
  PIN tx_flit[408]
    DIRECTION INPUT ;
    USE SIGNAL ;
    SHAPE ABUTMENT ;
    PORT
      LAYER M4 ;
      RECT 0 619.776 0.192 619.800 ;
    END
  END tx_flit[408]
  PIN tx_flit[409]
    DIRECTION INPUT ;
    USE SIGNAL ;
    SHAPE ABUTMENT ;
    PORT
      LAYER M4 ;
      RECT 0 619.824 0.192 619.848 ;
    END
  END tx_flit[409]
  PIN tx_flit[410]
    DIRECTION INPUT ;
    USE SIGNAL ;
    SHAPE ABUTMENT ;
    PORT
      LAYER M4 ;
      RECT 0 619.872 0.192 619.896 ;
    END
  END tx_flit[410]
  PIN tx_flit[411]
    DIRECTION INPUT ;
    USE SIGNAL ;
    SHAPE ABUTMENT ;
    PORT
      LAYER M4 ;
      RECT 0 619.920 0.192 619.944 ;
    END
  END tx_flit[411]
  PIN tx_flit[412]
    DIRECTION INPUT ;
    USE SIGNAL ;
    SHAPE ABUTMENT ;
    PORT
      LAYER M4 ;
      RECT 0 619.968 0.192 619.992 ;
    END
  END tx_flit[412]
  PIN tx_flit[413]
    DIRECTION INPUT ;
    USE SIGNAL ;
    SHAPE ABUTMENT ;
    PORT
      LAYER M4 ;
      RECT 0 620.016 0.192 620.040 ;
    END
  END tx_flit[413]
  PIN tx_flit[414]
    DIRECTION INPUT ;
    USE SIGNAL ;
    SHAPE ABUTMENT ;
    PORT
      LAYER M4 ;
      RECT 0 620.064 0.192 620.088 ;
    END
  END tx_flit[414]
  PIN tx_flit[415]
    DIRECTION INPUT ;
    USE SIGNAL ;
    SHAPE ABUTMENT ;
    PORT
      LAYER M4 ;
      RECT 0 620.112 0.192 620.136 ;
    END
  END tx_flit[415]
  PIN tx_flit[416]
    DIRECTION INPUT ;
    USE SIGNAL ;
    SHAPE ABUTMENT ;
    PORT
      LAYER M4 ;
      RECT 0 620.160 0.192 620.184 ;
    END
  END tx_flit[416]
  PIN tx_flit[417]
    DIRECTION INPUT ;
    USE SIGNAL ;
    SHAPE ABUTMENT ;
    PORT
      LAYER M4 ;
      RECT 0 620.208 0.192 620.232 ;
    END
  END tx_flit[417]
  PIN tx_flit[418]
    DIRECTION INPUT ;
    USE SIGNAL ;
    SHAPE ABUTMENT ;
    PORT
      LAYER M4 ;
      RECT 0 620.256 0.192 620.280 ;
    END
  END tx_flit[418]
  PIN tx_flit[419]
    DIRECTION INPUT ;
    USE SIGNAL ;
    SHAPE ABUTMENT ;
    PORT
      LAYER M4 ;
      RECT 0 620.304 0.192 620.328 ;
    END
  END tx_flit[419]
  PIN tx_flit[420]
    DIRECTION INPUT ;
    USE SIGNAL ;
    SHAPE ABUTMENT ;
    PORT
      LAYER M4 ;
      RECT 0 620.352 0.192 620.376 ;
    END
  END tx_flit[420]
  PIN tx_flit[421]
    DIRECTION INPUT ;
    USE SIGNAL ;
    SHAPE ABUTMENT ;
    PORT
      LAYER M4 ;
      RECT 0 620.400 0.192 620.424 ;
    END
  END tx_flit[421]
  PIN tx_flit[422]
    DIRECTION INPUT ;
    USE SIGNAL ;
    SHAPE ABUTMENT ;
    PORT
      LAYER M4 ;
      RECT 0 620.448 0.192 620.472 ;
    END
  END tx_flit[422]
  PIN tx_flit[423]
    DIRECTION INPUT ;
    USE SIGNAL ;
    SHAPE ABUTMENT ;
    PORT
      LAYER M4 ;
      RECT 0 620.496 0.192 620.520 ;
    END
  END tx_flit[423]
  PIN tx_flit[424]
    DIRECTION INPUT ;
    USE SIGNAL ;
    SHAPE ABUTMENT ;
    PORT
      LAYER M4 ;
      RECT 0 620.544 0.192 620.568 ;
    END
  END tx_flit[424]
  PIN tx_flit[425]
    DIRECTION INPUT ;
    USE SIGNAL ;
    SHAPE ABUTMENT ;
    PORT
      LAYER M4 ;
      RECT 0 620.592 0.192 620.616 ;
    END
  END tx_flit[425]
  PIN tx_flit[426]
    DIRECTION INPUT ;
    USE SIGNAL ;
    SHAPE ABUTMENT ;
    PORT
      LAYER M4 ;
      RECT 0 620.640 0.192 620.664 ;
    END
  END tx_flit[426]
  PIN tx_flit[427]
    DIRECTION INPUT ;
    USE SIGNAL ;
    SHAPE ABUTMENT ;
    PORT
      LAYER M4 ;
      RECT 0 620.688 0.192 620.712 ;
    END
  END tx_flit[427]
  PIN tx_flit[428]
    DIRECTION INPUT ;
    USE SIGNAL ;
    SHAPE ABUTMENT ;
    PORT
      LAYER M4 ;
      RECT 0 620.736 0.192 620.760 ;
    END
  END tx_flit[428]
  PIN tx_flit[429]
    DIRECTION INPUT ;
    USE SIGNAL ;
    SHAPE ABUTMENT ;
    PORT
      LAYER M4 ;
      RECT 0 620.784 0.192 620.808 ;
    END
  END tx_flit[429]
  PIN tx_flit[430]
    DIRECTION INPUT ;
    USE SIGNAL ;
    SHAPE ABUTMENT ;
    PORT
      LAYER M4 ;
      RECT 0 620.832 0.192 620.856 ;
    END
  END tx_flit[430]
  PIN tx_flit[431]
    DIRECTION INPUT ;
    USE SIGNAL ;
    SHAPE ABUTMENT ;
    PORT
      LAYER M4 ;
      RECT 0 620.880 0.192 620.904 ;
    END
  END tx_flit[431]
  PIN tx_flit[432]
    DIRECTION INPUT ;
    USE SIGNAL ;
    SHAPE ABUTMENT ;
    PORT
      LAYER M4 ;
      RECT 0 620.928 0.192 620.952 ;
    END
  END tx_flit[432]
  PIN tx_flit[433]
    DIRECTION INPUT ;
    USE SIGNAL ;
    SHAPE ABUTMENT ;
    PORT
      LAYER M4 ;
      RECT 0 620.976 0.192 621.000 ;
    END
  END tx_flit[433]
  PIN tx_flit[434]
    DIRECTION INPUT ;
    USE SIGNAL ;
    SHAPE ABUTMENT ;
    PORT
      LAYER M4 ;
      RECT 0 621.024 0.192 621.048 ;
    END
  END tx_flit[434]
  PIN tx_flit[435]
    DIRECTION INPUT ;
    USE SIGNAL ;
    SHAPE ABUTMENT ;
    PORT
      LAYER M4 ;
      RECT 0 621.072 0.192 621.096 ;
    END
  END tx_flit[435]
  PIN tx_flit[436]
    DIRECTION INPUT ;
    USE SIGNAL ;
    SHAPE ABUTMENT ;
    PORT
      LAYER M4 ;
      RECT 0 621.120 0.192 621.144 ;
    END
  END tx_flit[436]
  PIN tx_flit[437]
    DIRECTION INPUT ;
    USE SIGNAL ;
    SHAPE ABUTMENT ;
    PORT
      LAYER M4 ;
      RECT 0 621.168 0.192 621.192 ;
    END
  END tx_flit[437]
  PIN tx_flit[438]
    DIRECTION INPUT ;
    USE SIGNAL ;
    SHAPE ABUTMENT ;
    PORT
      LAYER M4 ;
      RECT 0 621.216 0.192 621.240 ;
    END
  END tx_flit[438]
  PIN tx_flit[439]
    DIRECTION INPUT ;
    USE SIGNAL ;
    SHAPE ABUTMENT ;
    PORT
      LAYER M4 ;
      RECT 0 621.264 0.192 621.288 ;
    END
  END tx_flit[439]
  PIN tx_flit[440]
    DIRECTION INPUT ;
    USE SIGNAL ;
    SHAPE ABUTMENT ;
    PORT
      LAYER M4 ;
      RECT 0 621.312 0.192 621.336 ;
    END
  END tx_flit[440]
  PIN tx_flit[441]
    DIRECTION INPUT ;
    USE SIGNAL ;
    SHAPE ABUTMENT ;
    PORT
      LAYER M4 ;
      RECT 0 621.360 0.192 621.384 ;
    END
  END tx_flit[441]
  PIN tx_flit[442]
    DIRECTION INPUT ;
    USE SIGNAL ;
    SHAPE ABUTMENT ;
    PORT
      LAYER M4 ;
      RECT 0 621.408 0.192 621.432 ;
    END
  END tx_flit[442]
  PIN tx_flit[443]
    DIRECTION INPUT ;
    USE SIGNAL ;
    SHAPE ABUTMENT ;
    PORT
      LAYER M4 ;
      RECT 0 621.456 0.192 621.480 ;
    END
  END tx_flit[443]
  PIN tx_flit[444]
    DIRECTION INPUT ;
    USE SIGNAL ;
    SHAPE ABUTMENT ;
    PORT
      LAYER M4 ;
      RECT 0 621.504 0.192 621.528 ;
    END
  END tx_flit[444]
  PIN tx_flit[445]
    DIRECTION INPUT ;
    USE SIGNAL ;
    SHAPE ABUTMENT ;
    PORT
      LAYER M4 ;
      RECT 0 621.552 0.192 621.576 ;
    END
  END tx_flit[445]
  PIN tx_flit[446]
    DIRECTION INPUT ;
    USE SIGNAL ;
    SHAPE ABUTMENT ;
    PORT
      LAYER M4 ;
      RECT 0 621.600 0.192 621.624 ;
    END
  END tx_flit[446]
  PIN tx_flit[447]
    DIRECTION INPUT ;
    USE SIGNAL ;
    SHAPE ABUTMENT ;
    PORT
      LAYER M4 ;
      RECT 0 621.648 0.192 621.672 ;
    END
  END tx_flit[447]
  PIN tx_flit[448]
    DIRECTION INPUT ;
    USE SIGNAL ;
    SHAPE ABUTMENT ;
    PORT
      LAYER M4 ;
      RECT 0 621.696 0.192 621.720 ;
    END
  END tx_flit[448]
  PIN tx_flit[449]
    DIRECTION INPUT ;
    USE SIGNAL ;
    SHAPE ABUTMENT ;
    PORT
      LAYER M4 ;
      RECT 0 621.744 0.192 621.768 ;
    END
  END tx_flit[449]
  PIN tx_flit[450]
    DIRECTION INPUT ;
    USE SIGNAL ;
    SHAPE ABUTMENT ;
    PORT
      LAYER M4 ;
      RECT 0 621.792 0.192 621.816 ;
    END
  END tx_flit[450]
  PIN tx_flit[451]
    DIRECTION INPUT ;
    USE SIGNAL ;
    SHAPE ABUTMENT ;
    PORT
      LAYER M4 ;
      RECT 0 621.840 0.192 621.864 ;
    END
  END tx_flit[451]
  PIN tx_flit[452]
    DIRECTION INPUT ;
    USE SIGNAL ;
    SHAPE ABUTMENT ;
    PORT
      LAYER M4 ;
      RECT 0 621.888 0.192 621.912 ;
    END
  END tx_flit[452]
  PIN tx_flit[453]
    DIRECTION INPUT ;
    USE SIGNAL ;
    SHAPE ABUTMENT ;
    PORT
      LAYER M4 ;
      RECT 0 621.936 0.192 621.960 ;
    END
  END tx_flit[453]
  PIN tx_flit[454]
    DIRECTION INPUT ;
    USE SIGNAL ;
    SHAPE ABUTMENT ;
    PORT
      LAYER M4 ;
      RECT 0 621.984 0.192 622.008 ;
    END
  END tx_flit[454]
  PIN tx_flit[455]
    DIRECTION INPUT ;
    USE SIGNAL ;
    SHAPE ABUTMENT ;
    PORT
      LAYER M4 ;
      RECT 0 622.032 0.192 622.056 ;
    END
  END tx_flit[455]
  PIN tx_flit[456]
    DIRECTION INPUT ;
    USE SIGNAL ;
    SHAPE ABUTMENT ;
    PORT
      LAYER M4 ;
      RECT 0 622.080 0.192 622.104 ;
    END
  END tx_flit[456]
  PIN tx_flit[457]
    DIRECTION INPUT ;
    USE SIGNAL ;
    SHAPE ABUTMENT ;
    PORT
      LAYER M4 ;
      RECT 0 622.128 0.192 622.152 ;
    END
  END tx_flit[457]
  PIN tx_flit[458]
    DIRECTION INPUT ;
    USE SIGNAL ;
    SHAPE ABUTMENT ;
    PORT
      LAYER M4 ;
      RECT 0 622.176 0.192 622.200 ;
    END
  END tx_flit[458]
  PIN tx_flit[459]
    DIRECTION INPUT ;
    USE SIGNAL ;
    SHAPE ABUTMENT ;
    PORT
      LAYER M4 ;
      RECT 0 622.224 0.192 622.248 ;
    END
  END tx_flit[459]
  PIN tx_flit[460]
    DIRECTION INPUT ;
    USE SIGNAL ;
    SHAPE ABUTMENT ;
    PORT
      LAYER M4 ;
      RECT 0 622.272 0.192 622.296 ;
    END
  END tx_flit[460]
  PIN tx_flit[461]
    DIRECTION INPUT ;
    USE SIGNAL ;
    SHAPE ABUTMENT ;
    PORT
      LAYER M4 ;
      RECT 0 622.320 0.192 622.344 ;
    END
  END tx_flit[461]
  PIN tx_flit[462]
    DIRECTION INPUT ;
    USE SIGNAL ;
    SHAPE ABUTMENT ;
    PORT
      LAYER M4 ;
      RECT 0 622.368 0.192 622.392 ;
    END
  END tx_flit[462]
  PIN tx_flit[463]
    DIRECTION INPUT ;
    USE SIGNAL ;
    SHAPE ABUTMENT ;
    PORT
      LAYER M4 ;
      RECT 0 622.416 0.192 622.440 ;
    END
  END tx_flit[463]
  PIN tx_flit[464]
    DIRECTION INPUT ;
    USE SIGNAL ;
    SHAPE ABUTMENT ;
    PORT
      LAYER M4 ;
      RECT 0 622.464 0.192 622.488 ;
    END
  END tx_flit[464]
  PIN tx_flit[465]
    DIRECTION INPUT ;
    USE SIGNAL ;
    SHAPE ABUTMENT ;
    PORT
      LAYER M4 ;
      RECT 0 622.512 0.192 622.536 ;
    END
  END tx_flit[465]
  PIN tx_flit[466]
    DIRECTION INPUT ;
    USE SIGNAL ;
    SHAPE ABUTMENT ;
    PORT
      LAYER M4 ;
      RECT 0 622.560 0.192 622.584 ;
    END
  END tx_flit[466]
  PIN tx_flit[467]
    DIRECTION INPUT ;
    USE SIGNAL ;
    SHAPE ABUTMENT ;
    PORT
      LAYER M4 ;
      RECT 0 622.608 0.192 622.632 ;
    END
  END tx_flit[467]
  PIN tx_flit[468]
    DIRECTION INPUT ;
    USE SIGNAL ;
    SHAPE ABUTMENT ;
    PORT
      LAYER M4 ;
      RECT 0 622.656 0.192 622.680 ;
    END
  END tx_flit[468]
  PIN tx_flit[469]
    DIRECTION INPUT ;
    USE SIGNAL ;
    SHAPE ABUTMENT ;
    PORT
      LAYER M4 ;
      RECT 0 622.704 0.192 622.728 ;
    END
  END tx_flit[469]
  PIN tx_flit[470]
    DIRECTION INPUT ;
    USE SIGNAL ;
    SHAPE ABUTMENT ;
    PORT
      LAYER M4 ;
      RECT 0 622.752 0.192 622.776 ;
    END
  END tx_flit[470]
  PIN tx_flit[471]
    DIRECTION INPUT ;
    USE SIGNAL ;
    SHAPE ABUTMENT ;
    PORT
      LAYER M4 ;
      RECT 0 622.800 0.192 622.824 ;
    END
  END tx_flit[471]
  PIN tx_flit[472]
    DIRECTION INPUT ;
    USE SIGNAL ;
    SHAPE ABUTMENT ;
    PORT
      LAYER M4 ;
      RECT 0 622.848 0.192 622.872 ;
    END
  END tx_flit[472]
  PIN tx_flit[473]
    DIRECTION INPUT ;
    USE SIGNAL ;
    SHAPE ABUTMENT ;
    PORT
      LAYER M4 ;
      RECT 0 622.896 0.192 622.920 ;
    END
  END tx_flit[473]
  PIN tx_flit[474]
    DIRECTION INPUT ;
    USE SIGNAL ;
    SHAPE ABUTMENT ;
    PORT
      LAYER M4 ;
      RECT 0 622.944 0.192 622.968 ;
    END
  END tx_flit[474]
  PIN tx_flit[475]
    DIRECTION INPUT ;
    USE SIGNAL ;
    SHAPE ABUTMENT ;
    PORT
      LAYER M4 ;
      RECT 0 622.992 0.192 623.016 ;
    END
  END tx_flit[475]
  PIN tx_flit[476]
    DIRECTION INPUT ;
    USE SIGNAL ;
    SHAPE ABUTMENT ;
    PORT
      LAYER M4 ;
      RECT 0 623.040 0.192 623.064 ;
    END
  END tx_flit[476]
  PIN tx_flit[477]
    DIRECTION INPUT ;
    USE SIGNAL ;
    SHAPE ABUTMENT ;
    PORT
      LAYER M4 ;
      RECT 0 623.088 0.192 623.112 ;
    END
  END tx_flit[477]
  PIN tx_flit[478]
    DIRECTION INPUT ;
    USE SIGNAL ;
    SHAPE ABUTMENT ;
    PORT
      LAYER M4 ;
      RECT 0 623.136 0.192 623.160 ;
    END
  END tx_flit[478]
  PIN tx_flit[479]
    DIRECTION INPUT ;
    USE SIGNAL ;
    SHAPE ABUTMENT ;
    PORT
      LAYER M4 ;
      RECT 0 623.184 0.192 623.208 ;
    END
  END tx_flit[479]
  PIN tx_flit[480]
    DIRECTION INPUT ;
    USE SIGNAL ;
    SHAPE ABUTMENT ;
    PORT
      LAYER M4 ;
      RECT 0 623.232 0.192 623.256 ;
    END
  END tx_flit[480]
  PIN tx_flit[481]
    DIRECTION INPUT ;
    USE SIGNAL ;
    SHAPE ABUTMENT ;
    PORT
      LAYER M4 ;
      RECT 0 623.280 0.192 623.304 ;
    END
  END tx_flit[481]
  PIN tx_flit[482]
    DIRECTION INPUT ;
    USE SIGNAL ;
    SHAPE ABUTMENT ;
    PORT
      LAYER M4 ;
      RECT 0 623.328 0.192 623.352 ;
    END
  END tx_flit[482]
  PIN tx_flit[483]
    DIRECTION INPUT ;
    USE SIGNAL ;
    SHAPE ABUTMENT ;
    PORT
      LAYER M4 ;
      RECT 0 623.376 0.192 623.400 ;
    END
  END tx_flit[483]
  PIN tx_flit[484]
    DIRECTION INPUT ;
    USE SIGNAL ;
    SHAPE ABUTMENT ;
    PORT
      LAYER M4 ;
      RECT 0 623.424 0.192 623.448 ;
    END
  END tx_flit[484]
  PIN tx_flit[485]
    DIRECTION INPUT ;
    USE SIGNAL ;
    SHAPE ABUTMENT ;
    PORT
      LAYER M4 ;
      RECT 0 623.472 0.192 623.496 ;
    END
  END tx_flit[485]
  PIN tx_flit[486]
    DIRECTION INPUT ;
    USE SIGNAL ;
    SHAPE ABUTMENT ;
    PORT
      LAYER M4 ;
      RECT 0 623.520 0.192 623.544 ;
    END
  END tx_flit[486]
  PIN tx_flit[487]
    DIRECTION INPUT ;
    USE SIGNAL ;
    SHAPE ABUTMENT ;
    PORT
      LAYER M4 ;
      RECT 0 623.568 0.192 623.592 ;
    END
  END tx_flit[487]
  PIN tx_flit[488]
    DIRECTION INPUT ;
    USE SIGNAL ;
    SHAPE ABUTMENT ;
    PORT
      LAYER M4 ;
      RECT 0 623.616 0.192 623.640 ;
    END
  END tx_flit[488]
  PIN tx_flit[489]
    DIRECTION INPUT ;
    USE SIGNAL ;
    SHAPE ABUTMENT ;
    PORT
      LAYER M4 ;
      RECT 0 623.664 0.192 623.688 ;
    END
  END tx_flit[489]
  PIN tx_flit[490]
    DIRECTION INPUT ;
    USE SIGNAL ;
    SHAPE ABUTMENT ;
    PORT
      LAYER M4 ;
      RECT 0 623.712 0.192 623.736 ;
    END
  END tx_flit[490]
  PIN tx_flit[491]
    DIRECTION INPUT ;
    USE SIGNAL ;
    SHAPE ABUTMENT ;
    PORT
      LAYER M4 ;
      RECT 0 623.760 0.192 623.784 ;
    END
  END tx_flit[491]
  PIN tx_flit[492]
    DIRECTION INPUT ;
    USE SIGNAL ;
    SHAPE ABUTMENT ;
    PORT
      LAYER M4 ;
      RECT 0 623.808 0.192 623.832 ;
    END
  END tx_flit[492]
  PIN tx_flit[493]
    DIRECTION INPUT ;
    USE SIGNAL ;
    SHAPE ABUTMENT ;
    PORT
      LAYER M4 ;
      RECT 0 623.856 0.192 623.880 ;
    END
  END tx_flit[493]
  PIN tx_flit[494]
    DIRECTION INPUT ;
    USE SIGNAL ;
    SHAPE ABUTMENT ;
    PORT
      LAYER M4 ;
      RECT 0 623.904 0.192 623.928 ;
    END
  END tx_flit[494]
  PIN tx_flit[495]
    DIRECTION INPUT ;
    USE SIGNAL ;
    SHAPE ABUTMENT ;
    PORT
      LAYER M4 ;
      RECT 0 623.952 0.192 623.976 ;
    END
  END tx_flit[495]
  PIN tx_flit[496]
    DIRECTION INPUT ;
    USE SIGNAL ;
    SHAPE ABUTMENT ;
    PORT
      LAYER M4 ;
      RECT 0 624.000 0.192 624.024 ;
    END
  END tx_flit[496]
  PIN tx_flit[497]
    DIRECTION INPUT ;
    USE SIGNAL ;
    SHAPE ABUTMENT ;
    PORT
      LAYER M4 ;
      RECT 0 624.048 0.192 624.072 ;
    END
  END tx_flit[497]
  PIN tx_flit[498]
    DIRECTION INPUT ;
    USE SIGNAL ;
    SHAPE ABUTMENT ;
    PORT
      LAYER M4 ;
      RECT 0 624.096 0.192 624.120 ;
    END
  END tx_flit[498]
  PIN tx_flit[499]
    DIRECTION INPUT ;
    USE SIGNAL ;
    SHAPE ABUTMENT ;
    PORT
      LAYER M4 ;
      RECT 0 624.144 0.192 624.168 ;
    END
  END tx_flit[499]
  PIN tx_flit[500]
    DIRECTION INPUT ;
    USE SIGNAL ;
    SHAPE ABUTMENT ;
    PORT
      LAYER M4 ;
      RECT 0 624.192 0.192 624.216 ;
    END
  END tx_flit[500]
  PIN tx_flit[501]
    DIRECTION INPUT ;
    USE SIGNAL ;
    SHAPE ABUTMENT ;
    PORT
      LAYER M4 ;
      RECT 0 624.240 0.192 624.264 ;
    END
  END tx_flit[501]
  PIN tx_flit[502]
    DIRECTION INPUT ;
    USE SIGNAL ;
    SHAPE ABUTMENT ;
    PORT
      LAYER M4 ;
      RECT 0 624.288 0.192 624.312 ;
    END
  END tx_flit[502]
  PIN tx_flit[503]
    DIRECTION INPUT ;
    USE SIGNAL ;
    SHAPE ABUTMENT ;
    PORT
      LAYER M4 ;
      RECT 0 624.336 0.192 624.360 ;
    END
  END tx_flit[503]
  PIN tx_flit[504]
    DIRECTION INPUT ;
    USE SIGNAL ;
    SHAPE ABUTMENT ;
    PORT
      LAYER M4 ;
      RECT 0 624.384 0.192 624.408 ;
    END
  END tx_flit[504]
  PIN tx_flit[505]
    DIRECTION INPUT ;
    USE SIGNAL ;
    SHAPE ABUTMENT ;
    PORT
      LAYER M4 ;
      RECT 0 624.432 0.192 624.456 ;
    END
  END tx_flit[505]
  PIN tx_flit[506]
    DIRECTION INPUT ;
    USE SIGNAL ;
    SHAPE ABUTMENT ;
    PORT
      LAYER M4 ;
      RECT 0 624.480 0.192 624.504 ;
    END
  END tx_flit[506]
  PIN tx_flit[507]
    DIRECTION INPUT ;
    USE SIGNAL ;
    SHAPE ABUTMENT ;
    PORT
      LAYER M4 ;
      RECT 0 624.528 0.192 624.552 ;
    END
  END tx_flit[507]
  PIN tx_flit[508]
    DIRECTION INPUT ;
    USE SIGNAL ;
    SHAPE ABUTMENT ;
    PORT
      LAYER M4 ;
      RECT 0 624.576 0.192 624.600 ;
    END
  END tx_flit[508]
  PIN tx_flit[509]
    DIRECTION INPUT ;
    USE SIGNAL ;
    SHAPE ABUTMENT ;
    PORT
      LAYER M4 ;
      RECT 0 624.624 0.192 624.648 ;
    END
  END tx_flit[509]
  PIN tx_flit[510]
    DIRECTION INPUT ;
    USE SIGNAL ;
    SHAPE ABUTMENT ;
    PORT
      LAYER M4 ;
      RECT 0 624.672 0.192 624.696 ;
    END
  END tx_flit[510]
  PIN tx_flit[511]
    DIRECTION INPUT ;
    USE SIGNAL ;
    SHAPE ABUTMENT ;
    PORT
      LAYER M4 ;
      RECT 0 624.720 0.192 624.744 ;
    END
  END tx_flit[511]
  PIN tx_flit[512]
    DIRECTION INPUT ;
    USE SIGNAL ;
    SHAPE ABUTMENT ;
    PORT
      LAYER M4 ;
      RECT 0 624.768 0.192 624.792 ;
    END
  END tx_flit[512]
  PIN tx_flit[513]
    DIRECTION INPUT ;
    USE SIGNAL ;
    SHAPE ABUTMENT ;
    PORT
      LAYER M4 ;
      RECT 0 624.816 0.192 624.840 ;
    END
  END tx_flit[513]
  PIN tx_flit[514]
    DIRECTION INPUT ;
    USE SIGNAL ;
    SHAPE ABUTMENT ;
    PORT
      LAYER M4 ;
      RECT 0 624.864 0.192 624.888 ;
    END
  END tx_flit[514]
  PIN tx_flit[515]
    DIRECTION INPUT ;
    USE SIGNAL ;
    SHAPE ABUTMENT ;
    PORT
      LAYER M4 ;
      RECT 0 624.912 0.192 624.936 ;
    END
  END tx_flit[515]
  PIN tx_flit[516]
    DIRECTION INPUT ;
    USE SIGNAL ;
    SHAPE ABUTMENT ;
    PORT
      LAYER M4 ;
      RECT 0 624.960 0.192 624.984 ;
    END
  END tx_flit[516]
  PIN tx_flit[517]
    DIRECTION INPUT ;
    USE SIGNAL ;
    SHAPE ABUTMENT ;
    PORT
      LAYER M4 ;
      RECT 0 625.008 0.192 625.032 ;
    END
  END tx_flit[517]
  PIN tx_flit[518]
    DIRECTION INPUT ;
    USE SIGNAL ;
    SHAPE ABUTMENT ;
    PORT
      LAYER M4 ;
      RECT 0 625.056 0.192 625.080 ;
    END
  END tx_flit[518]
  PIN tx_flit[519]
    DIRECTION INPUT ;
    USE SIGNAL ;
    SHAPE ABUTMENT ;
    PORT
      LAYER M4 ;
      RECT 0 625.104 0.192 625.128 ;
    END
  END tx_flit[519]
  PIN tx_flit[520]
    DIRECTION INPUT ;
    USE SIGNAL ;
    SHAPE ABUTMENT ;
    PORT
      LAYER M4 ;
      RECT 0 625.152 0.192 625.176 ;
    END
  END tx_flit[520]
  PIN tx_flit[521]
    DIRECTION INPUT ;
    USE SIGNAL ;
    SHAPE ABUTMENT ;
    PORT
      LAYER M4 ;
      RECT 0 625.200 0.192 625.224 ;
    END
  END tx_flit[521]
  PIN tx_flit[522]
    DIRECTION INPUT ;
    USE SIGNAL ;
    SHAPE ABUTMENT ;
    PORT
      LAYER M4 ;
      RECT 0 625.248 0.192 625.272 ;
    END
  END tx_flit[522]
  PIN tx_flit[523]
    DIRECTION INPUT ;
    USE SIGNAL ;
    SHAPE ABUTMENT ;
    PORT
      LAYER M4 ;
      RECT 0 625.296 0.192 625.320 ;
    END
  END tx_flit[523]
  PIN tx_flit[524]
    DIRECTION INPUT ;
    USE SIGNAL ;
    SHAPE ABUTMENT ;
    PORT
      LAYER M4 ;
      RECT 0 625.344 0.192 625.368 ;
    END
  END tx_flit[524]
  PIN tx_flit[525]
    DIRECTION INPUT ;
    USE SIGNAL ;
    SHAPE ABUTMENT ;
    PORT
      LAYER M4 ;
      RECT 0 625.392 0.192 625.416 ;
    END
  END tx_flit[525]
  PIN tx_flit[526]
    DIRECTION INPUT ;
    USE SIGNAL ;
    SHAPE ABUTMENT ;
    PORT
      LAYER M4 ;
      RECT 0 625.440 0.192 625.464 ;
    END
  END tx_flit[526]
  PIN tx_flit[527]
    DIRECTION INPUT ;
    USE SIGNAL ;
    SHAPE ABUTMENT ;
    PORT
      LAYER M4 ;
      RECT 0 625.488 0.192 625.512 ;
    END
  END tx_flit[527]
  PIN tx_flit[528]
    DIRECTION INPUT ;
    USE SIGNAL ;
    SHAPE ABUTMENT ;
    PORT
      LAYER M4 ;
      RECT 0 625.536 0.192 625.560 ;
    END
  END tx_flit[528]
  PIN tx_flit[529]
    DIRECTION INPUT ;
    USE SIGNAL ;
    SHAPE ABUTMENT ;
    PORT
      LAYER M4 ;
      RECT 0 625.584 0.192 625.608 ;
    END
  END tx_flit[529]
  PIN tx_flit[530]
    DIRECTION INPUT ;
    USE SIGNAL ;
    SHAPE ABUTMENT ;
    PORT
      LAYER M4 ;
      RECT 0 625.632 0.192 625.656 ;
    END
  END tx_flit[530]
  PIN tx_flit[531]
    DIRECTION INPUT ;
    USE SIGNAL ;
    SHAPE ABUTMENT ;
    PORT
      LAYER M4 ;
      RECT 0 625.680 0.192 625.704 ;
    END
  END tx_flit[531]
  PIN tx_flit[532]
    DIRECTION INPUT ;
    USE SIGNAL ;
    SHAPE ABUTMENT ;
    PORT
      LAYER M4 ;
      RECT 0 625.728 0.192 625.752 ;
    END
  END tx_flit[532]
  PIN tx_flit[533]
    DIRECTION INPUT ;
    USE SIGNAL ;
    SHAPE ABUTMENT ;
    PORT
      LAYER M4 ;
      RECT 0 625.776 0.192 625.800 ;
    END
  END tx_flit[533]
  PIN tx_flit[534]
    DIRECTION INPUT ;
    USE SIGNAL ;
    SHAPE ABUTMENT ;
    PORT
      LAYER M4 ;
      RECT 0 625.824 0.192 625.848 ;
    END
  END tx_flit[534]
  PIN tx_flit[535]
    DIRECTION INPUT ;
    USE SIGNAL ;
    SHAPE ABUTMENT ;
    PORT
      LAYER M4 ;
      RECT 0 625.872 0.192 625.896 ;
    END
  END tx_flit[535]
  PIN tx_flit[536]
    DIRECTION INPUT ;
    USE SIGNAL ;
    SHAPE ABUTMENT ;
    PORT
      LAYER M4 ;
      RECT 0 625.920 0.192 625.944 ;
    END
  END tx_flit[536]
  PIN tx_flit[537]
    DIRECTION INPUT ;
    USE SIGNAL ;
    SHAPE ABUTMENT ;
    PORT
      LAYER M4 ;
      RECT 0 625.968 0.192 625.992 ;
    END
  END tx_flit[537]
  PIN tx_flit[538]
    DIRECTION INPUT ;
    USE SIGNAL ;
    SHAPE ABUTMENT ;
    PORT
      LAYER M4 ;
      RECT 0 626.016 0.192 626.040 ;
    END
  END tx_flit[538]
  PIN tx_flit[539]
    DIRECTION INPUT ;
    USE SIGNAL ;
    SHAPE ABUTMENT ;
    PORT
      LAYER M4 ;
      RECT 0 626.064 0.192 626.088 ;
    END
  END tx_flit[539]
  PIN tx_flit[540]
    DIRECTION INPUT ;
    USE SIGNAL ;
    SHAPE ABUTMENT ;
    PORT
      LAYER M4 ;
      RECT 0 626.112 0.192 626.136 ;
    END
  END tx_flit[540]
  PIN tx_flit[541]
    DIRECTION INPUT ;
    USE SIGNAL ;
    SHAPE ABUTMENT ;
    PORT
      LAYER M4 ;
      RECT 0 626.160 0.192 626.184 ;
    END
  END tx_flit[541]
  PIN tx_flit[542]
    DIRECTION INPUT ;
    USE SIGNAL ;
    SHAPE ABUTMENT ;
    PORT
      LAYER M4 ;
      RECT 0 626.208 0.192 626.232 ;
    END
  END tx_flit[542]
  PIN tx_flit[543]
    DIRECTION INPUT ;
    USE SIGNAL ;
    SHAPE ABUTMENT ;
    PORT
      LAYER M4 ;
      RECT 0 626.256 0.192 626.280 ;
    END
  END tx_flit[543]
  PIN tx_flit[544]
    DIRECTION INPUT ;
    USE SIGNAL ;
    SHAPE ABUTMENT ;
    PORT
      LAYER M4 ;
      RECT 0 626.304 0.192 626.328 ;
    END
  END tx_flit[544]
  PIN tx_flit[545]
    DIRECTION INPUT ;
    USE SIGNAL ;
    SHAPE ABUTMENT ;
    PORT
      LAYER M4 ;
      RECT 0 626.352 0.192 626.376 ;
    END
  END tx_flit[545]
  PIN tx_flit[546]
    DIRECTION INPUT ;
    USE SIGNAL ;
    SHAPE ABUTMENT ;
    PORT
      LAYER M4 ;
      RECT 0 626.400 0.192 626.424 ;
    END
  END tx_flit[546]
  PIN tx_flit[547]
    DIRECTION INPUT ;
    USE SIGNAL ;
    SHAPE ABUTMENT ;
    PORT
      LAYER M4 ;
      RECT 0 626.448 0.192 626.472 ;
    END
  END tx_flit[547]
  PIN tx_flit[548]
    DIRECTION INPUT ;
    USE SIGNAL ;
    SHAPE ABUTMENT ;
    PORT
      LAYER M4 ;
      RECT 0 626.496 0.192 626.520 ;
    END
  END tx_flit[548]
  PIN tx_flit[549]
    DIRECTION INPUT ;
    USE SIGNAL ;
    SHAPE ABUTMENT ;
    PORT
      LAYER M4 ;
      RECT 0 626.544 0.192 626.568 ;
    END
  END tx_flit[549]
  PIN tx_flit[550]
    DIRECTION INPUT ;
    USE SIGNAL ;
    SHAPE ABUTMENT ;
    PORT
      LAYER M4 ;
      RECT 0 626.592 0.192 626.616 ;
    END
  END tx_flit[550]
  PIN tx_flit[551]
    DIRECTION INPUT ;
    USE SIGNAL ;
    SHAPE ABUTMENT ;
    PORT
      LAYER M4 ;
      RECT 0 626.640 0.192 626.664 ;
    END
  END tx_flit[551]
  PIN tx_flit[552]
    DIRECTION INPUT ;
    USE SIGNAL ;
    SHAPE ABUTMENT ;
    PORT
      LAYER M4 ;
      RECT 0 626.688 0.192 626.712 ;
    END
  END tx_flit[552]
  PIN tx_flit[553]
    DIRECTION INPUT ;
    USE SIGNAL ;
    SHAPE ABUTMENT ;
    PORT
      LAYER M4 ;
      RECT 0 626.736 0.192 626.760 ;
    END
  END tx_flit[553]
  PIN tx_flit[554]
    DIRECTION INPUT ;
    USE SIGNAL ;
    SHAPE ABUTMENT ;
    PORT
      LAYER M4 ;
      RECT 0 626.784 0.192 626.808 ;
    END
  END tx_flit[554]
  PIN tx_flit[555]
    DIRECTION INPUT ;
    USE SIGNAL ;
    SHAPE ABUTMENT ;
    PORT
      LAYER M4 ;
      RECT 0 626.832 0.192 626.856 ;
    END
  END tx_flit[555]
  PIN tx_flit[556]
    DIRECTION INPUT ;
    USE SIGNAL ;
    SHAPE ABUTMENT ;
    PORT
      LAYER M4 ;
      RECT 0 626.880 0.192 626.904 ;
    END
  END tx_flit[556]
  PIN tx_flit[557]
    DIRECTION INPUT ;
    USE SIGNAL ;
    SHAPE ABUTMENT ;
    PORT
      LAYER M4 ;
      RECT 0 626.928 0.192 626.952 ;
    END
  END tx_flit[557]
  PIN tx_flit[558]
    DIRECTION INPUT ;
    USE SIGNAL ;
    SHAPE ABUTMENT ;
    PORT
      LAYER M4 ;
      RECT 0 626.976 0.192 627.000 ;
    END
  END tx_flit[558]
  PIN tx_flit[559]
    DIRECTION INPUT ;
    USE SIGNAL ;
    SHAPE ABUTMENT ;
    PORT
      LAYER M4 ;
      RECT 0 627.024 0.192 627.048 ;
    END
  END tx_flit[559]
  PIN tx_flit[560]
    DIRECTION INPUT ;
    USE SIGNAL ;
    SHAPE ABUTMENT ;
    PORT
      LAYER M4 ;
      RECT 0 627.072 0.192 627.096 ;
    END
  END tx_flit[560]
  PIN tx_flit[561]
    DIRECTION INPUT ;
    USE SIGNAL ;
    SHAPE ABUTMENT ;
    PORT
      LAYER M4 ;
      RECT 0 627.120 0.192 627.144 ;
    END
  END tx_flit[561]
  PIN tx_flit[562]
    DIRECTION INPUT ;
    USE SIGNAL ;
    SHAPE ABUTMENT ;
    PORT
      LAYER M4 ;
      RECT 0 627.168 0.192 627.192 ;
    END
  END tx_flit[562]
  PIN tx_flit[563]
    DIRECTION INPUT ;
    USE SIGNAL ;
    SHAPE ABUTMENT ;
    PORT
      LAYER M4 ;
      RECT 0 627.216 0.192 627.240 ;
    END
  END tx_flit[563]
  PIN tx_flit[564]
    DIRECTION INPUT ;
    USE SIGNAL ;
    SHAPE ABUTMENT ;
    PORT
      LAYER M4 ;
      RECT 0 627.264 0.192 627.288 ;
    END
  END tx_flit[564]
  PIN tx_flit[565]
    DIRECTION INPUT ;
    USE SIGNAL ;
    SHAPE ABUTMENT ;
    PORT
      LAYER M4 ;
      RECT 0 627.312 0.192 627.336 ;
    END
  END tx_flit[565]
  PIN tx_flit[566]
    DIRECTION INPUT ;
    USE SIGNAL ;
    SHAPE ABUTMENT ;
    PORT
      LAYER M4 ;
      RECT 0 627.360 0.192 627.384 ;
    END
  END tx_flit[566]
  PIN tx_flit[567]
    DIRECTION INPUT ;
    USE SIGNAL ;
    SHAPE ABUTMENT ;
    PORT
      LAYER M4 ;
      RECT 0 627.408 0.192 627.432 ;
    END
  END tx_flit[567]
  PIN tx_flit[568]
    DIRECTION INPUT ;
    USE SIGNAL ;
    SHAPE ABUTMENT ;
    PORT
      LAYER M4 ;
      RECT 0 627.456 0.192 627.480 ;
    END
  END tx_flit[568]
  PIN tx_flit[569]
    DIRECTION INPUT ;
    USE SIGNAL ;
    SHAPE ABUTMENT ;
    PORT
      LAYER M4 ;
      RECT 0 627.504 0.192 627.528 ;
    END
  END tx_flit[569]
  PIN tx_flit[570]
    DIRECTION INPUT ;
    USE SIGNAL ;
    SHAPE ABUTMENT ;
    PORT
      LAYER M4 ;
      RECT 0 627.552 0.192 627.576 ;
    END
  END tx_flit[570]
  PIN tx_flit[571]
    DIRECTION INPUT ;
    USE SIGNAL ;
    SHAPE ABUTMENT ;
    PORT
      LAYER M4 ;
      RECT 0 627.600 0.192 627.624 ;
    END
  END tx_flit[571]
  PIN tx_flit[572]
    DIRECTION INPUT ;
    USE SIGNAL ;
    SHAPE ABUTMENT ;
    PORT
      LAYER M4 ;
      RECT 0 627.648 0.192 627.672 ;
    END
  END tx_flit[572]
  PIN tx_flit[573]
    DIRECTION INPUT ;
    USE SIGNAL ;
    SHAPE ABUTMENT ;
    PORT
      LAYER M4 ;
      RECT 0 627.696 0.192 627.720 ;
    END
  END tx_flit[573]
  PIN tx_flit[574]
    DIRECTION INPUT ;
    USE SIGNAL ;
    SHAPE ABUTMENT ;
    PORT
      LAYER M4 ;
      RECT 0 627.744 0.192 627.768 ;
    END
  END tx_flit[574]
  PIN tx_flit[575]
    DIRECTION INPUT ;
    USE SIGNAL ;
    SHAPE ABUTMENT ;
    PORT
      LAYER M4 ;
      RECT 0 627.792 0.192 627.816 ;
    END
  END tx_flit[575]
  PIN tx_flit[576]
    DIRECTION INPUT ;
    USE SIGNAL ;
    SHAPE ABUTMENT ;
    PORT
      LAYER M4 ;
      RECT 0 627.840 0.192 627.864 ;
    END
  END tx_flit[576]
  PIN tx_flit[577]
    DIRECTION INPUT ;
    USE SIGNAL ;
    SHAPE ABUTMENT ;
    PORT
      LAYER M4 ;
      RECT 0 627.888 0.192 627.912 ;
    END
  END tx_flit[577]
  PIN tx_flit[578]
    DIRECTION INPUT ;
    USE SIGNAL ;
    SHAPE ABUTMENT ;
    PORT
      LAYER M4 ;
      RECT 0 627.936 0.192 627.960 ;
    END
  END tx_flit[578]
  PIN tx_flit[579]
    DIRECTION INPUT ;
    USE SIGNAL ;
    SHAPE ABUTMENT ;
    PORT
      LAYER M4 ;
      RECT 0 627.984 0.192 628.008 ;
    END
  END tx_flit[579]
  PIN tx_flit[580]
    DIRECTION INPUT ;
    USE SIGNAL ;
    SHAPE ABUTMENT ;
    PORT
      LAYER M4 ;
      RECT 0 628.032 0.192 628.056 ;
    END
  END tx_flit[580]
  PIN tx_flit[581]
    DIRECTION INPUT ;
    USE SIGNAL ;
    SHAPE ABUTMENT ;
    PORT
      LAYER M4 ;
      RECT 0 628.080 0.192 628.104 ;
    END
  END tx_flit[581]
  PIN tx_flit[582]
    DIRECTION INPUT ;
    USE SIGNAL ;
    SHAPE ABUTMENT ;
    PORT
      LAYER M4 ;
      RECT 0 628.128 0.192 628.152 ;
    END
  END tx_flit[582]
  PIN tx_flit[583]
    DIRECTION INPUT ;
    USE SIGNAL ;
    SHAPE ABUTMENT ;
    PORT
      LAYER M4 ;
      RECT 0 628.176 0.192 628.200 ;
    END
  END tx_flit[583]
  PIN tx_flit[584]
    DIRECTION INPUT ;
    USE SIGNAL ;
    SHAPE ABUTMENT ;
    PORT
      LAYER M4 ;
      RECT 0 628.224 0.192 628.248 ;
    END
  END tx_flit[584]
  PIN tx_flit[585]
    DIRECTION INPUT ;
    USE SIGNAL ;
    SHAPE ABUTMENT ;
    PORT
      LAYER M4 ;
      RECT 0 628.272 0.192 628.296 ;
    END
  END tx_flit[585]
  PIN tx_flit[586]
    DIRECTION INPUT ;
    USE SIGNAL ;
    SHAPE ABUTMENT ;
    PORT
      LAYER M4 ;
      RECT 0 628.320 0.192 628.344 ;
    END
  END tx_flit[586]
  PIN tx_flit[587]
    DIRECTION INPUT ;
    USE SIGNAL ;
    SHAPE ABUTMENT ;
    PORT
      LAYER M4 ;
      RECT 0 628.368 0.192 628.392 ;
    END
  END tx_flit[587]
  PIN tx_flit[588]
    DIRECTION INPUT ;
    USE SIGNAL ;
    SHAPE ABUTMENT ;
    PORT
      LAYER M4 ;
      RECT 0 628.416 0.192 628.440 ;
    END
  END tx_flit[588]
  PIN tx_flit[589]
    DIRECTION INPUT ;
    USE SIGNAL ;
    SHAPE ABUTMENT ;
    PORT
      LAYER M4 ;
      RECT 0 628.464 0.192 628.488 ;
    END
  END tx_flit[589]
  PIN tx_flit[590]
    DIRECTION INPUT ;
    USE SIGNAL ;
    SHAPE ABUTMENT ;
    PORT
      LAYER M4 ;
      RECT 0 628.512 0.192 628.536 ;
    END
  END tx_flit[590]
  PIN tx_flit[591]
    DIRECTION INPUT ;
    USE SIGNAL ;
    SHAPE ABUTMENT ;
    PORT
      LAYER M4 ;
      RECT 0 628.560 0.192 628.584 ;
    END
  END tx_flit[591]
  PIN tx_flit[592]
    DIRECTION INPUT ;
    USE SIGNAL ;
    SHAPE ABUTMENT ;
    PORT
      LAYER M4 ;
      RECT 0 628.608 0.192 628.632 ;
    END
  END tx_flit[592]
  PIN tx_flit[593]
    DIRECTION INPUT ;
    USE SIGNAL ;
    SHAPE ABUTMENT ;
    PORT
      LAYER M4 ;
      RECT 0 628.656 0.192 628.680 ;
    END
  END tx_flit[593]
  PIN tx_flit[594]
    DIRECTION INPUT ;
    USE SIGNAL ;
    SHAPE ABUTMENT ;
    PORT
      LAYER M4 ;
      RECT 0 628.704 0.192 628.728 ;
    END
  END tx_flit[594]
  PIN tx_flit[595]
    DIRECTION INPUT ;
    USE SIGNAL ;
    SHAPE ABUTMENT ;
    PORT
      LAYER M4 ;
      RECT 0 628.752 0.192 628.776 ;
    END
  END tx_flit[595]
  PIN tx_flit[596]
    DIRECTION INPUT ;
    USE SIGNAL ;
    SHAPE ABUTMENT ;
    PORT
      LAYER M4 ;
      RECT 0 628.800 0.192 628.824 ;
    END
  END tx_flit[596]
  PIN rx_v
    DIRECTION OUTPUT ;
    USE SIGNAL ;
    SHAPE ABUTMENT ;
    PORT
      LAYER M4 ;
      RECT 0 628.848 0.192 628.872 ;
    END
  END rx_v
  PIN rx_flit[0]
    DIRECTION OUTPUT ;
    USE SIGNAL ;
    SHAPE ABUTMENT ;
    PORT
      LAYER M4 ;
      RECT 0 628.896 0.192 628.920 ;
    END
  END rx_flit[0]
  PIN rx_flit[1]
    DIRECTION OUTPUT ;
    USE SIGNAL ;
    SHAPE ABUTMENT ;
    PORT
      LAYER M4 ;
      RECT 0 628.944 0.192 628.968 ;
    END
  END rx_flit[1]
  PIN rx_flit[2]
    DIRECTION OUTPUT ;
    USE SIGNAL ;
    SHAPE ABUTMENT ;
    PORT
      LAYER M4 ;
      RECT 0 628.992 0.192 629.016 ;
    END
  END rx_flit[2]
  PIN rx_flit[3]
    DIRECTION OUTPUT ;
    USE SIGNAL ;
    SHAPE ABUTMENT ;
    PORT
      LAYER M4 ;
      RECT 0 629.040 0.192 629.064 ;
    END
  END rx_flit[3]
  PIN rx_flit[4]
    DIRECTION OUTPUT ;
    USE SIGNAL ;
    SHAPE ABUTMENT ;
    PORT
      LAYER M4 ;
      RECT 0 629.088 0.192 629.112 ;
    END
  END rx_flit[4]
  PIN rx_flit[5]
    DIRECTION OUTPUT ;
    USE SIGNAL ;
    SHAPE ABUTMENT ;
    PORT
      LAYER M4 ;
      RECT 0 629.136 0.192 629.160 ;
    END
  END rx_flit[5]
  PIN rx_flit[6]
    DIRECTION OUTPUT ;
    USE SIGNAL ;
    SHAPE ABUTMENT ;
    PORT
      LAYER M4 ;
      RECT 0 629.184 0.192 629.208 ;
    END
  END rx_flit[6]
  PIN rx_flit[7]
    DIRECTION OUTPUT ;
    USE SIGNAL ;
    SHAPE ABUTMENT ;
    PORT
      LAYER M4 ;
      RECT 0 629.232 0.192 629.256 ;
    END
  END rx_flit[7]
  PIN rx_flit[8]
    DIRECTION OUTPUT ;
    USE SIGNAL ;
    SHAPE ABUTMENT ;
    PORT
      LAYER M4 ;
      RECT 0 629.280 0.192 629.304 ;
    END
  END rx_flit[8]
  PIN rx_flit[9]
    DIRECTION OUTPUT ;
    USE SIGNAL ;
    SHAPE ABUTMENT ;
    PORT
      LAYER M4 ;
      RECT 0 629.328 0.192 629.352 ;
    END
  END rx_flit[9]
  PIN rx_flit[10]
    DIRECTION OUTPUT ;
    USE SIGNAL ;
    SHAPE ABUTMENT ;
    PORT
      LAYER M4 ;
      RECT 0 629.376 0.192 629.400 ;
    END
  END rx_flit[10]
  PIN rx_flit[11]
    DIRECTION OUTPUT ;
    USE SIGNAL ;
    SHAPE ABUTMENT ;
    PORT
      LAYER M4 ;
      RECT 0 629.424 0.192 629.448 ;
    END
  END rx_flit[11]
  PIN rx_flit[12]
    DIRECTION OUTPUT ;
    USE SIGNAL ;
    SHAPE ABUTMENT ;
    PORT
      LAYER M4 ;
      RECT 0 629.472 0.192 629.496 ;
    END
  END rx_flit[12]
  PIN rx_flit[13]
    DIRECTION OUTPUT ;
    USE SIGNAL ;
    SHAPE ABUTMENT ;
    PORT
      LAYER M4 ;
      RECT 0 629.520 0.192 629.544 ;
    END
  END rx_flit[13]
  PIN rx_flit[14]
    DIRECTION OUTPUT ;
    USE SIGNAL ;
    SHAPE ABUTMENT ;
    PORT
      LAYER M4 ;
      RECT 0 629.568 0.192 629.592 ;
    END
  END rx_flit[14]
  PIN rx_flit[15]
    DIRECTION OUTPUT ;
    USE SIGNAL ;
    SHAPE ABUTMENT ;
    PORT
      LAYER M4 ;
      RECT 0 629.616 0.192 629.640 ;
    END
  END rx_flit[15]
  PIN rx_flit[16]
    DIRECTION OUTPUT ;
    USE SIGNAL ;
    SHAPE ABUTMENT ;
    PORT
      LAYER M4 ;
      RECT 0 629.664 0.192 629.688 ;
    END
  END rx_flit[16]
  PIN rx_flit[17]
    DIRECTION OUTPUT ;
    USE SIGNAL ;
    SHAPE ABUTMENT ;
    PORT
      LAYER M4 ;
      RECT 0 629.712 0.192 629.736 ;
    END
  END rx_flit[17]
  PIN rx_flit[18]
    DIRECTION OUTPUT ;
    USE SIGNAL ;
    SHAPE ABUTMENT ;
    PORT
      LAYER M4 ;
      RECT 0 629.760 0.192 629.784 ;
    END
  END rx_flit[18]
  PIN rx_flit[19]
    DIRECTION OUTPUT ;
    USE SIGNAL ;
    SHAPE ABUTMENT ;
    PORT
      LAYER M4 ;
      RECT 0 629.808 0.192 629.832 ;
    END
  END rx_flit[19]
  PIN rx_flit[20]
    DIRECTION OUTPUT ;
    USE SIGNAL ;
    SHAPE ABUTMENT ;
    PORT
      LAYER M4 ;
      RECT 0 629.856 0.192 629.880 ;
    END
  END rx_flit[20]
  PIN rx_flit[21]
    DIRECTION OUTPUT ;
    USE SIGNAL ;
    SHAPE ABUTMENT ;
    PORT
      LAYER M4 ;
      RECT 0 629.904 0.192 629.928 ;
    END
  END rx_flit[21]
  PIN rx_flit[22]
    DIRECTION OUTPUT ;
    USE SIGNAL ;
    SHAPE ABUTMENT ;
    PORT
      LAYER M4 ;
      RECT 0 629.952 0.192 629.976 ;
    END
  END rx_flit[22]
  PIN rx_flit[23]
    DIRECTION OUTPUT ;
    USE SIGNAL ;
    SHAPE ABUTMENT ;
    PORT
      LAYER M4 ;
      RECT 0 630.000 0.192 630.024 ;
    END
  END rx_flit[23]
  PIN rx_flit[24]
    DIRECTION OUTPUT ;
    USE SIGNAL ;
    SHAPE ABUTMENT ;
    PORT
      LAYER M4 ;
      RECT 0 630.048 0.192 630.072 ;
    END
  END rx_flit[24]
  PIN rx_flit[25]
    DIRECTION OUTPUT ;
    USE SIGNAL ;
    SHAPE ABUTMENT ;
    PORT
      LAYER M4 ;
      RECT 0 630.096 0.192 630.120 ;
    END
  END rx_flit[25]
  PIN rx_flit[26]
    DIRECTION OUTPUT ;
    USE SIGNAL ;
    SHAPE ABUTMENT ;
    PORT
      LAYER M4 ;
      RECT 0 630.144 0.192 630.168 ;
    END
  END rx_flit[26]
  PIN rx_flit[27]
    DIRECTION OUTPUT ;
    USE SIGNAL ;
    SHAPE ABUTMENT ;
    PORT
      LAYER M4 ;
      RECT 0 630.192 0.192 630.216 ;
    END
  END rx_flit[27]
  PIN rx_flit[28]
    DIRECTION OUTPUT ;
    USE SIGNAL ;
    SHAPE ABUTMENT ;
    PORT
      LAYER M4 ;
      RECT 0 630.240 0.192 630.264 ;
    END
  END rx_flit[28]
  PIN rx_flit[29]
    DIRECTION OUTPUT ;
    USE SIGNAL ;
    SHAPE ABUTMENT ;
    PORT
      LAYER M4 ;
      RECT 0 630.288 0.192 630.312 ;
    END
  END rx_flit[29]
  PIN rx_flit[30]
    DIRECTION OUTPUT ;
    USE SIGNAL ;
    SHAPE ABUTMENT ;
    PORT
      LAYER M4 ;
      RECT 0 630.336 0.192 630.360 ;
    END
  END rx_flit[30]
  PIN rx_flit[31]
    DIRECTION OUTPUT ;
    USE SIGNAL ;
    SHAPE ABUTMENT ;
    PORT
      LAYER M4 ;
      RECT 0 630.384 0.192 630.408 ;
    END
  END rx_flit[31]
  PIN rx_flit[32]
    DIRECTION OUTPUT ;
    USE SIGNAL ;
    SHAPE ABUTMENT ;
    PORT
      LAYER M4 ;
      RECT 0 630.432 0.192 630.456 ;
    END
  END rx_flit[32]
  PIN rx_flit[33]
    DIRECTION OUTPUT ;
    USE SIGNAL ;
    SHAPE ABUTMENT ;
    PORT
      LAYER M4 ;
      RECT 0 630.480 0.192 630.504 ;
    END
  END rx_flit[33]
  PIN rx_flit[34]
    DIRECTION OUTPUT ;
    USE SIGNAL ;
    SHAPE ABUTMENT ;
    PORT
      LAYER M4 ;
      RECT 0 630.528 0.192 630.552 ;
    END
  END rx_flit[34]
  PIN rx_flit[35]
    DIRECTION OUTPUT ;
    USE SIGNAL ;
    SHAPE ABUTMENT ;
    PORT
      LAYER M4 ;
      RECT 0 630.576 0.192 630.600 ;
    END
  END rx_flit[35]
  PIN rx_flit[36]
    DIRECTION OUTPUT ;
    USE SIGNAL ;
    SHAPE ABUTMENT ;
    PORT
      LAYER M4 ;
      RECT 0 630.624 0.192 630.648 ;
    END
  END rx_flit[36]
  PIN rx_flit[37]
    DIRECTION OUTPUT ;
    USE SIGNAL ;
    SHAPE ABUTMENT ;
    PORT
      LAYER M4 ;
      RECT 0 630.672 0.192 630.696 ;
    END
  END rx_flit[37]
  PIN rx_flit[38]
    DIRECTION OUTPUT ;
    USE SIGNAL ;
    SHAPE ABUTMENT ;
    PORT
      LAYER M4 ;
      RECT 0 630.720 0.192 630.744 ;
    END
  END rx_flit[38]
  PIN rx_flit[39]
    DIRECTION OUTPUT ;
    USE SIGNAL ;
    SHAPE ABUTMENT ;
    PORT
      LAYER M4 ;
      RECT 0 630.768 0.192 630.792 ;
    END
  END rx_flit[39]
  PIN rx_flit[40]
    DIRECTION OUTPUT ;
    USE SIGNAL ;
    SHAPE ABUTMENT ;
    PORT
      LAYER M4 ;
      RECT 0 630.816 0.192 630.840 ;
    END
  END rx_flit[40]
  PIN rx_flit[41]
    DIRECTION OUTPUT ;
    USE SIGNAL ;
    SHAPE ABUTMENT ;
    PORT
      LAYER M4 ;
      RECT 0 630.864 0.192 630.888 ;
    END
  END rx_flit[41]
  PIN rx_flit[42]
    DIRECTION OUTPUT ;
    USE SIGNAL ;
    SHAPE ABUTMENT ;
    PORT
      LAYER M4 ;
      RECT 0 630.912 0.192 630.936 ;
    END
  END rx_flit[42]
  PIN rx_flit[43]
    DIRECTION OUTPUT ;
    USE SIGNAL ;
    SHAPE ABUTMENT ;
    PORT
      LAYER M4 ;
      RECT 0 630.960 0.192 630.984 ;
    END
  END rx_flit[43]
  PIN rx_flit[44]
    DIRECTION OUTPUT ;
    USE SIGNAL ;
    SHAPE ABUTMENT ;
    PORT
      LAYER M4 ;
      RECT 0 631.008 0.192 631.032 ;
    END
  END rx_flit[44]
  PIN rx_flit[45]
    DIRECTION OUTPUT ;
    USE SIGNAL ;
    SHAPE ABUTMENT ;
    PORT
      LAYER M4 ;
      RECT 0 631.056 0.192 631.080 ;
    END
  END rx_flit[45]
  PIN rx_flit[46]
    DIRECTION OUTPUT ;
    USE SIGNAL ;
    SHAPE ABUTMENT ;
    PORT
      LAYER M4 ;
      RECT 0 631.104 0.192 631.128 ;
    END
  END rx_flit[46]
  PIN rx_flit[47]
    DIRECTION OUTPUT ;
    USE SIGNAL ;
    SHAPE ABUTMENT ;
    PORT
      LAYER M4 ;
      RECT 0 631.152 0.192 631.176 ;
    END
  END rx_flit[47]
  PIN rx_flit[48]
    DIRECTION OUTPUT ;
    USE SIGNAL ;
    SHAPE ABUTMENT ;
    PORT
      LAYER M4 ;
      RECT 0 631.200 0.192 631.224 ;
    END
  END rx_flit[48]
  PIN rx_flit[49]
    DIRECTION OUTPUT ;
    USE SIGNAL ;
    SHAPE ABUTMENT ;
    PORT
      LAYER M4 ;
      RECT 0 631.248 0.192 631.272 ;
    END
  END rx_flit[49]
  PIN rx_flit[50]
    DIRECTION OUTPUT ;
    USE SIGNAL ;
    SHAPE ABUTMENT ;
    PORT
      LAYER M4 ;
      RECT 0 631.296 0.192 631.320 ;
    END
  END rx_flit[50]
  PIN rx_flit[51]
    DIRECTION OUTPUT ;
    USE SIGNAL ;
    SHAPE ABUTMENT ;
    PORT
      LAYER M4 ;
      RECT 0 631.344 0.192 631.368 ;
    END
  END rx_flit[51]
  PIN rx_flit[52]
    DIRECTION OUTPUT ;
    USE SIGNAL ;
    SHAPE ABUTMENT ;
    PORT
      LAYER M4 ;
      RECT 0 631.392 0.192 631.416 ;
    END
  END rx_flit[52]
  PIN rx_flit[53]
    DIRECTION OUTPUT ;
    USE SIGNAL ;
    SHAPE ABUTMENT ;
    PORT
      LAYER M4 ;
      RECT 0 631.440 0.192 631.464 ;
    END
  END rx_flit[53]
  PIN rx_flit[54]
    DIRECTION OUTPUT ;
    USE SIGNAL ;
    SHAPE ABUTMENT ;
    PORT
      LAYER M4 ;
      RECT 0 631.488 0.192 631.512 ;
    END
  END rx_flit[54]
  PIN rx_flit[55]
    DIRECTION OUTPUT ;
    USE SIGNAL ;
    SHAPE ABUTMENT ;
    PORT
      LAYER M4 ;
      RECT 0 631.536 0.192 631.560 ;
    END
  END rx_flit[55]
  PIN rx_flit[56]
    DIRECTION OUTPUT ;
    USE SIGNAL ;
    SHAPE ABUTMENT ;
    PORT
      LAYER M4 ;
      RECT 0 631.584 0.192 631.608 ;
    END
  END rx_flit[56]
  PIN rx_flit[57]
    DIRECTION OUTPUT ;
    USE SIGNAL ;
    SHAPE ABUTMENT ;
    PORT
      LAYER M4 ;
      RECT 0 631.632 0.192 631.656 ;
    END
  END rx_flit[57]
  PIN rx_flit[58]
    DIRECTION OUTPUT ;
    USE SIGNAL ;
    SHAPE ABUTMENT ;
    PORT
      LAYER M4 ;
      RECT 0 631.680 0.192 631.704 ;
    END
  END rx_flit[58]
  PIN rx_flit[59]
    DIRECTION OUTPUT ;
    USE SIGNAL ;
    SHAPE ABUTMENT ;
    PORT
      LAYER M4 ;
      RECT 0 631.728 0.192 631.752 ;
    END
  END rx_flit[59]
  PIN rx_flit[60]
    DIRECTION OUTPUT ;
    USE SIGNAL ;
    SHAPE ABUTMENT ;
    PORT
      LAYER M4 ;
      RECT 0 631.776 0.192 631.800 ;
    END
  END rx_flit[60]
  PIN rx_flit[61]
    DIRECTION OUTPUT ;
    USE SIGNAL ;
    SHAPE ABUTMENT ;
    PORT
      LAYER M4 ;
      RECT 0 631.824 0.192 631.848 ;
    END
  END rx_flit[61]
  PIN rx_flit[62]
    DIRECTION OUTPUT ;
    USE SIGNAL ;
    SHAPE ABUTMENT ;
    PORT
      LAYER M4 ;
      RECT 0 631.872 0.192 631.896 ;
    END
  END rx_flit[62]
  PIN rx_flit[63]
    DIRECTION OUTPUT ;
    USE SIGNAL ;
    SHAPE ABUTMENT ;
    PORT
      LAYER M4 ;
      RECT 0 631.920 0.192 631.944 ;
    END
  END rx_flit[63]
  PIN rx_flit[64]
    DIRECTION OUTPUT ;
    USE SIGNAL ;
    SHAPE ABUTMENT ;
    PORT
      LAYER M4 ;
      RECT 0 631.968 0.192 631.992 ;
    END
  END rx_flit[64]
  PIN rx_flit[65]
    DIRECTION OUTPUT ;
    USE SIGNAL ;
    SHAPE ABUTMENT ;
    PORT
      LAYER M4 ;
      RECT 0 632.016 0.192 632.040 ;
    END
  END rx_flit[65]
  PIN rx_flit[66]
    DIRECTION OUTPUT ;
    USE SIGNAL ;
    SHAPE ABUTMENT ;
    PORT
      LAYER M4 ;
      RECT 0 632.064 0.192 632.088 ;
    END
  END rx_flit[66]
  PIN rx_flit[67]
    DIRECTION OUTPUT ;
    USE SIGNAL ;
    SHAPE ABUTMENT ;
    PORT
      LAYER M4 ;
      RECT 0 632.112 0.192 632.136 ;
    END
  END rx_flit[67]
  PIN rx_flit[68]
    DIRECTION OUTPUT ;
    USE SIGNAL ;
    SHAPE ABUTMENT ;
    PORT
      LAYER M4 ;
      RECT 0 632.160 0.192 632.184 ;
    END
  END rx_flit[68]
  PIN rx_flit[69]
    DIRECTION OUTPUT ;
    USE SIGNAL ;
    SHAPE ABUTMENT ;
    PORT
      LAYER M4 ;
      RECT 0 632.208 0.192 632.232 ;
    END
  END rx_flit[69]
  PIN rx_flit[70]
    DIRECTION OUTPUT ;
    USE SIGNAL ;
    SHAPE ABUTMENT ;
    PORT
      LAYER M4 ;
      RECT 0 632.256 0.192 632.280 ;
    END
  END rx_flit[70]
  PIN rx_flit[71]
    DIRECTION OUTPUT ;
    USE SIGNAL ;
    SHAPE ABUTMENT ;
    PORT
      LAYER M4 ;
      RECT 0 632.304 0.192 632.328 ;
    END
  END rx_flit[71]
  PIN rx_flit[72]
    DIRECTION OUTPUT ;
    USE SIGNAL ;
    SHAPE ABUTMENT ;
    PORT
      LAYER M4 ;
      RECT 0 632.352 0.192 632.376 ;
    END
  END rx_flit[72]
  PIN rx_flit[73]
    DIRECTION OUTPUT ;
    USE SIGNAL ;
    SHAPE ABUTMENT ;
    PORT
      LAYER M4 ;
      RECT 0 632.400 0.192 632.424 ;
    END
  END rx_flit[73]
  PIN rx_flit[74]
    DIRECTION OUTPUT ;
    USE SIGNAL ;
    SHAPE ABUTMENT ;
    PORT
      LAYER M4 ;
      RECT 0 632.448 0.192 632.472 ;
    END
  END rx_flit[74]
  PIN rx_flit[75]
    DIRECTION OUTPUT ;
    USE SIGNAL ;
    SHAPE ABUTMENT ;
    PORT
      LAYER M4 ;
      RECT 0 632.496 0.192 632.520 ;
    END
  END rx_flit[75]
  PIN rx_flit[76]
    DIRECTION OUTPUT ;
    USE SIGNAL ;
    SHAPE ABUTMENT ;
    PORT
      LAYER M4 ;
      RECT 0 632.544 0.192 632.568 ;
    END
  END rx_flit[76]
  PIN rx_flit[77]
    DIRECTION OUTPUT ;
    USE SIGNAL ;
    SHAPE ABUTMENT ;
    PORT
      LAYER M4 ;
      RECT 0 632.592 0.192 632.616 ;
    END
  END rx_flit[77]
  PIN rx_flit[78]
    DIRECTION OUTPUT ;
    USE SIGNAL ;
    SHAPE ABUTMENT ;
    PORT
      LAYER M4 ;
      RECT 0 632.640 0.192 632.664 ;
    END
  END rx_flit[78]
  PIN rx_flit[79]
    DIRECTION OUTPUT ;
    USE SIGNAL ;
    SHAPE ABUTMENT ;
    PORT
      LAYER M4 ;
      RECT 0 632.688 0.192 632.712 ;
    END
  END rx_flit[79]
  PIN rx_flit[80]
    DIRECTION OUTPUT ;
    USE SIGNAL ;
    SHAPE ABUTMENT ;
    PORT
      LAYER M4 ;
      RECT 0 632.736 0.192 632.760 ;
    END
  END rx_flit[80]
  PIN rx_flit[81]
    DIRECTION OUTPUT ;
    USE SIGNAL ;
    SHAPE ABUTMENT ;
    PORT
      LAYER M4 ;
      RECT 0 632.784 0.192 632.808 ;
    END
  END rx_flit[81]
  PIN rx_flit[82]
    DIRECTION OUTPUT ;
    USE SIGNAL ;
    SHAPE ABUTMENT ;
    PORT
      LAYER M4 ;
      RECT 0 632.832 0.192 632.856 ;
    END
  END rx_flit[82]
  PIN rx_flit[83]
    DIRECTION OUTPUT ;
    USE SIGNAL ;
    SHAPE ABUTMENT ;
    PORT
      LAYER M4 ;
      RECT 0 632.880 0.192 632.904 ;
    END
  END rx_flit[83]
  PIN rx_flit[84]
    DIRECTION OUTPUT ;
    USE SIGNAL ;
    SHAPE ABUTMENT ;
    PORT
      LAYER M4 ;
      RECT 0 632.928 0.192 632.952 ;
    END
  END rx_flit[84]
  PIN rx_flit[85]
    DIRECTION OUTPUT ;
    USE SIGNAL ;
    SHAPE ABUTMENT ;
    PORT
      LAYER M4 ;
      RECT 0 632.976 0.192 633.000 ;
    END
  END rx_flit[85]
  PIN rx_flit[86]
    DIRECTION OUTPUT ;
    USE SIGNAL ;
    SHAPE ABUTMENT ;
    PORT
      LAYER M4 ;
      RECT 0 633.024 0.192 633.048 ;
    END
  END rx_flit[86]
  PIN rx_flit[87]
    DIRECTION OUTPUT ;
    USE SIGNAL ;
    SHAPE ABUTMENT ;
    PORT
      LAYER M4 ;
      RECT 0 633.072 0.192 633.096 ;
    END
  END rx_flit[87]
  PIN rx_flit[88]
    DIRECTION OUTPUT ;
    USE SIGNAL ;
    SHAPE ABUTMENT ;
    PORT
      LAYER M4 ;
      RECT 0 633.120 0.192 633.144 ;
    END
  END rx_flit[88]
  PIN rx_flit[89]
    DIRECTION OUTPUT ;
    USE SIGNAL ;
    SHAPE ABUTMENT ;
    PORT
      LAYER M4 ;
      RECT 0 633.168 0.192 633.192 ;
    END
  END rx_flit[89]
  PIN rx_flit[90]
    DIRECTION OUTPUT ;
    USE SIGNAL ;
    SHAPE ABUTMENT ;
    PORT
      LAYER M4 ;
      RECT 0 633.216 0.192 633.240 ;
    END
  END rx_flit[90]
  PIN rx_flit[91]
    DIRECTION OUTPUT ;
    USE SIGNAL ;
    SHAPE ABUTMENT ;
    PORT
      LAYER M4 ;
      RECT 0 633.264 0.192 633.288 ;
    END
  END rx_flit[91]
  PIN rx_flit[92]
    DIRECTION OUTPUT ;
    USE SIGNAL ;
    SHAPE ABUTMENT ;
    PORT
      LAYER M4 ;
      RECT 0 633.312 0.192 633.336 ;
    END
  END rx_flit[92]
  PIN rx_flit[93]
    DIRECTION OUTPUT ;
    USE SIGNAL ;
    SHAPE ABUTMENT ;
    PORT
      LAYER M4 ;
      RECT 0 633.360 0.192 633.384 ;
    END
  END rx_flit[93]
  PIN rx_flit[94]
    DIRECTION OUTPUT ;
    USE SIGNAL ;
    SHAPE ABUTMENT ;
    PORT
      LAYER M4 ;
      RECT 0 633.408 0.192 633.432 ;
    END
  END rx_flit[94]
  PIN rx_flit[95]
    DIRECTION OUTPUT ;
    USE SIGNAL ;
    SHAPE ABUTMENT ;
    PORT
      LAYER M4 ;
      RECT 0 633.456 0.192 633.480 ;
    END
  END rx_flit[95]
  PIN rx_flit[96]
    DIRECTION OUTPUT ;
    USE SIGNAL ;
    SHAPE ABUTMENT ;
    PORT
      LAYER M4 ;
      RECT 0 633.504 0.192 633.528 ;
    END
  END rx_flit[96]
  PIN rx_flit[97]
    DIRECTION OUTPUT ;
    USE SIGNAL ;
    SHAPE ABUTMENT ;
    PORT
      LAYER M4 ;
      RECT 0 633.552 0.192 633.576 ;
    END
  END rx_flit[97]
  PIN rx_flit[98]
    DIRECTION OUTPUT ;
    USE SIGNAL ;
    SHAPE ABUTMENT ;
    PORT
      LAYER M4 ;
      RECT 0 633.600 0.192 633.624 ;
    END
  END rx_flit[98]
  PIN rx_flit[99]
    DIRECTION OUTPUT ;
    USE SIGNAL ;
    SHAPE ABUTMENT ;
    PORT
      LAYER M4 ;
      RECT 0 633.648 0.192 633.672 ;
    END
  END rx_flit[99]
  PIN rx_flit[100]
    DIRECTION OUTPUT ;
    USE SIGNAL ;
    SHAPE ABUTMENT ;
    PORT
      LAYER M4 ;
      RECT 0 633.696 0.192 633.720 ;
    END
  END rx_flit[100]
  PIN rx_flit[101]
    DIRECTION OUTPUT ;
    USE SIGNAL ;
    SHAPE ABUTMENT ;
    PORT
      LAYER M4 ;
      RECT 0 633.744 0.192 633.768 ;
    END
  END rx_flit[101]
  PIN rx_flit[102]
    DIRECTION OUTPUT ;
    USE SIGNAL ;
    SHAPE ABUTMENT ;
    PORT
      LAYER M4 ;
      RECT 0 633.792 0.192 633.816 ;
    END
  END rx_flit[102]
  PIN rx_flit[103]
    DIRECTION OUTPUT ;
    USE SIGNAL ;
    SHAPE ABUTMENT ;
    PORT
      LAYER M4 ;
      RECT 0 633.840 0.192 633.864 ;
    END
  END rx_flit[103]
  PIN rx_flit[104]
    DIRECTION OUTPUT ;
    USE SIGNAL ;
    SHAPE ABUTMENT ;
    PORT
      LAYER M4 ;
      RECT 0 633.888 0.192 633.912 ;
    END
  END rx_flit[104]
  PIN rx_flit[105]
    DIRECTION OUTPUT ;
    USE SIGNAL ;
    SHAPE ABUTMENT ;
    PORT
      LAYER M4 ;
      RECT 0 633.936 0.192 633.960 ;
    END
  END rx_flit[105]
  PIN rx_flit[106]
    DIRECTION OUTPUT ;
    USE SIGNAL ;
    SHAPE ABUTMENT ;
    PORT
      LAYER M4 ;
      RECT 0 633.984 0.192 634.008 ;
    END
  END rx_flit[106]
  PIN rx_flit[107]
    DIRECTION OUTPUT ;
    USE SIGNAL ;
    SHAPE ABUTMENT ;
    PORT
      LAYER M4 ;
      RECT 0 634.032 0.192 634.056 ;
    END
  END rx_flit[107]
  PIN rx_flit[108]
    DIRECTION OUTPUT ;
    USE SIGNAL ;
    SHAPE ABUTMENT ;
    PORT
      LAYER M4 ;
      RECT 0 634.080 0.192 634.104 ;
    END
  END rx_flit[108]
  PIN rx_flit[109]
    DIRECTION OUTPUT ;
    USE SIGNAL ;
    SHAPE ABUTMENT ;
    PORT
      LAYER M4 ;
      RECT 0 634.128 0.192 634.152 ;
    END
  END rx_flit[109]
  PIN rx_flit[110]
    DIRECTION OUTPUT ;
    USE SIGNAL ;
    SHAPE ABUTMENT ;
    PORT
      LAYER M4 ;
      RECT 0 634.176 0.192 634.200 ;
    END
  END rx_flit[110]
  PIN rx_flit[111]
    DIRECTION OUTPUT ;
    USE SIGNAL ;
    SHAPE ABUTMENT ;
    PORT
      LAYER M4 ;
      RECT 0 634.224 0.192 634.248 ;
    END
  END rx_flit[111]
  PIN rx_flit[112]
    DIRECTION OUTPUT ;
    USE SIGNAL ;
    SHAPE ABUTMENT ;
    PORT
      LAYER M4 ;
      RECT 0 634.272 0.192 634.296 ;
    END
  END rx_flit[112]
  PIN rx_flit[113]
    DIRECTION OUTPUT ;
    USE SIGNAL ;
    SHAPE ABUTMENT ;
    PORT
      LAYER M4 ;
      RECT 0 634.320 0.192 634.344 ;
    END
  END rx_flit[113]
  PIN rx_flit[114]
    DIRECTION OUTPUT ;
    USE SIGNAL ;
    SHAPE ABUTMENT ;
    PORT
      LAYER M4 ;
      RECT 0 634.368 0.192 634.392 ;
    END
  END rx_flit[114]
  PIN rx_flit[115]
    DIRECTION OUTPUT ;
    USE SIGNAL ;
    SHAPE ABUTMENT ;
    PORT
      LAYER M4 ;
      RECT 0 634.416 0.192 634.440 ;
    END
  END rx_flit[115]
  PIN rx_flit[116]
    DIRECTION OUTPUT ;
    USE SIGNAL ;
    SHAPE ABUTMENT ;
    PORT
      LAYER M4 ;
      RECT 0 634.464 0.192 634.488 ;
    END
  END rx_flit[116]
  PIN rx_flit[117]
    DIRECTION OUTPUT ;
    USE SIGNAL ;
    SHAPE ABUTMENT ;
    PORT
      LAYER M4 ;
      RECT 0 634.512 0.192 634.536 ;
    END
  END rx_flit[117]
  PIN rx_flit[118]
    DIRECTION OUTPUT ;
    USE SIGNAL ;
    SHAPE ABUTMENT ;
    PORT
      LAYER M4 ;
      RECT 0 634.560 0.192 634.584 ;
    END
  END rx_flit[118]
  PIN rx_flit[119]
    DIRECTION OUTPUT ;
    USE SIGNAL ;
    SHAPE ABUTMENT ;
    PORT
      LAYER M4 ;
      RECT 0 634.608 0.192 634.632 ;
    END
  END rx_flit[119]
  PIN rx_flit[120]
    DIRECTION OUTPUT ;
    USE SIGNAL ;
    SHAPE ABUTMENT ;
    PORT
      LAYER M4 ;
      RECT 0 634.656 0.192 634.680 ;
    END
  END rx_flit[120]
  PIN rx_flit[121]
    DIRECTION OUTPUT ;
    USE SIGNAL ;
    SHAPE ABUTMENT ;
    PORT
      LAYER M4 ;
      RECT 0 634.704 0.192 634.728 ;
    END
  END rx_flit[121]
  PIN rx_flit[122]
    DIRECTION OUTPUT ;
    USE SIGNAL ;
    SHAPE ABUTMENT ;
    PORT
      LAYER M4 ;
      RECT 0 634.752 0.192 634.776 ;
    END
  END rx_flit[122]
  PIN rx_flit[123]
    DIRECTION OUTPUT ;
    USE SIGNAL ;
    SHAPE ABUTMENT ;
    PORT
      LAYER M4 ;
      RECT 0 634.800 0.192 634.824 ;
    END
  END rx_flit[123]
  PIN rx_flit[124]
    DIRECTION OUTPUT ;
    USE SIGNAL ;
    SHAPE ABUTMENT ;
    PORT
      LAYER M4 ;
      RECT 0 634.848 0.192 634.872 ;
    END
  END rx_flit[124]
  PIN rx_flit[125]
    DIRECTION OUTPUT ;
    USE SIGNAL ;
    SHAPE ABUTMENT ;
    PORT
      LAYER M4 ;
      RECT 0 634.896 0.192 634.920 ;
    END
  END rx_flit[125]
  PIN rx_flit[126]
    DIRECTION OUTPUT ;
    USE SIGNAL ;
    SHAPE ABUTMENT ;
    PORT
      LAYER M4 ;
      RECT 0 634.944 0.192 634.968 ;
    END
  END rx_flit[126]
  PIN rx_flit[127]
    DIRECTION OUTPUT ;
    USE SIGNAL ;
    SHAPE ABUTMENT ;
    PORT
      LAYER M4 ;
      RECT 0 634.992 0.192 635.016 ;
    END
  END rx_flit[127]
  PIN rx_flit[128]
    DIRECTION OUTPUT ;
    USE SIGNAL ;
    SHAPE ABUTMENT ;
    PORT
      LAYER M4 ;
      RECT 0 635.040 0.192 635.064 ;
    END
  END rx_flit[128]
  PIN rx_flit[129]
    DIRECTION OUTPUT ;
    USE SIGNAL ;
    SHAPE ABUTMENT ;
    PORT
      LAYER M4 ;
      RECT 0 635.088 0.192 635.112 ;
    END
  END rx_flit[129]
  PIN rx_flit[130]
    DIRECTION OUTPUT ;
    USE SIGNAL ;
    SHAPE ABUTMENT ;
    PORT
      LAYER M4 ;
      RECT 0 635.136 0.192 635.160 ;
    END
  END rx_flit[130]
  PIN rx_flit[131]
    DIRECTION OUTPUT ;
    USE SIGNAL ;
    SHAPE ABUTMENT ;
    PORT
      LAYER M4 ;
      RECT 0 635.184 0.192 635.208 ;
    END
  END rx_flit[131]
  PIN rx_flit[132]
    DIRECTION OUTPUT ;
    USE SIGNAL ;
    SHAPE ABUTMENT ;
    PORT
      LAYER M4 ;
      RECT 0 635.232 0.192 635.256 ;
    END
  END rx_flit[132]
  PIN rx_flit[133]
    DIRECTION OUTPUT ;
    USE SIGNAL ;
    SHAPE ABUTMENT ;
    PORT
      LAYER M4 ;
      RECT 0 635.280 0.192 635.304 ;
    END
  END rx_flit[133]
  PIN rx_flit[134]
    DIRECTION OUTPUT ;
    USE SIGNAL ;
    SHAPE ABUTMENT ;
    PORT
      LAYER M4 ;
      RECT 0 635.328 0.192 635.352 ;
    END
  END rx_flit[134]
  PIN rx_flit[135]
    DIRECTION OUTPUT ;
    USE SIGNAL ;
    SHAPE ABUTMENT ;
    PORT
      LAYER M4 ;
      RECT 0 635.376 0.192 635.400 ;
    END
  END rx_flit[135]
  PIN rx_flit[136]
    DIRECTION OUTPUT ;
    USE SIGNAL ;
    SHAPE ABUTMENT ;
    PORT
      LAYER M4 ;
      RECT 0 635.424 0.192 635.448 ;
    END
  END rx_flit[136]
  PIN rx_flit[137]
    DIRECTION OUTPUT ;
    USE SIGNAL ;
    SHAPE ABUTMENT ;
    PORT
      LAYER M4 ;
      RECT 0 635.472 0.192 635.496 ;
    END
  END rx_flit[137]
  PIN rx_flit[138]
    DIRECTION OUTPUT ;
    USE SIGNAL ;
    SHAPE ABUTMENT ;
    PORT
      LAYER M4 ;
      RECT 0 635.520 0.192 635.544 ;
    END
  END rx_flit[138]
  PIN rx_flit[139]
    DIRECTION OUTPUT ;
    USE SIGNAL ;
    SHAPE ABUTMENT ;
    PORT
      LAYER M4 ;
      RECT 0 635.568 0.192 635.592 ;
    END
  END rx_flit[139]
  PIN rx_flit[140]
    DIRECTION OUTPUT ;
    USE SIGNAL ;
    SHAPE ABUTMENT ;
    PORT
      LAYER M4 ;
      RECT 0 635.616 0.192 635.640 ;
    END
  END rx_flit[140]
  PIN rx_flit[141]
    DIRECTION OUTPUT ;
    USE SIGNAL ;
    SHAPE ABUTMENT ;
    PORT
      LAYER M4 ;
      RECT 0 635.664 0.192 635.688 ;
    END
  END rx_flit[141]
  PIN rx_flit[142]
    DIRECTION OUTPUT ;
    USE SIGNAL ;
    SHAPE ABUTMENT ;
    PORT
      LAYER M4 ;
      RECT 0 635.712 0.192 635.736 ;
    END
  END rx_flit[142]
  PIN rx_flit[143]
    DIRECTION OUTPUT ;
    USE SIGNAL ;
    SHAPE ABUTMENT ;
    PORT
      LAYER M4 ;
      RECT 0 635.760 0.192 635.784 ;
    END
  END rx_flit[143]
  PIN rx_flit[144]
    DIRECTION OUTPUT ;
    USE SIGNAL ;
    SHAPE ABUTMENT ;
    PORT
      LAYER M4 ;
      RECT 0 635.808 0.192 635.832 ;
    END
  END rx_flit[144]
  PIN rx_flit[145]
    DIRECTION OUTPUT ;
    USE SIGNAL ;
    SHAPE ABUTMENT ;
    PORT
      LAYER M4 ;
      RECT 0 635.856 0.192 635.880 ;
    END
  END rx_flit[145]
  PIN rx_flit[146]
    DIRECTION OUTPUT ;
    USE SIGNAL ;
    SHAPE ABUTMENT ;
    PORT
      LAYER M4 ;
      RECT 0 635.904 0.192 635.928 ;
    END
  END rx_flit[146]
  PIN rx_flit[147]
    DIRECTION OUTPUT ;
    USE SIGNAL ;
    SHAPE ABUTMENT ;
    PORT
      LAYER M4 ;
      RECT 0 635.952 0.192 635.976 ;
    END
  END rx_flit[147]
  PIN rx_flit[148]
    DIRECTION OUTPUT ;
    USE SIGNAL ;
    SHAPE ABUTMENT ;
    PORT
      LAYER M4 ;
      RECT 0 636.000 0.192 636.024 ;
    END
  END rx_flit[148]
  PIN rx_flit[149]
    DIRECTION OUTPUT ;
    USE SIGNAL ;
    SHAPE ABUTMENT ;
    PORT
      LAYER M4 ;
      RECT 0 636.048 0.192 636.072 ;
    END
  END rx_flit[149]
  PIN rx_flit[150]
    DIRECTION OUTPUT ;
    USE SIGNAL ;
    SHAPE ABUTMENT ;
    PORT
      LAYER M4 ;
      RECT 0 636.096 0.192 636.120 ;
    END
  END rx_flit[150]
  PIN rx_flit[151]
    DIRECTION OUTPUT ;
    USE SIGNAL ;
    SHAPE ABUTMENT ;
    PORT
      LAYER M4 ;
      RECT 0 636.144 0.192 636.168 ;
    END
  END rx_flit[151]
  PIN rx_flit[152]
    DIRECTION OUTPUT ;
    USE SIGNAL ;
    SHAPE ABUTMENT ;
    PORT
      LAYER M4 ;
      RECT 0 636.192 0.192 636.216 ;
    END
  END rx_flit[152]
  PIN rx_flit[153]
    DIRECTION OUTPUT ;
    USE SIGNAL ;
    SHAPE ABUTMENT ;
    PORT
      LAYER M4 ;
      RECT 0 636.240 0.192 636.264 ;
    END
  END rx_flit[153]
  PIN rx_flit[154]
    DIRECTION OUTPUT ;
    USE SIGNAL ;
    SHAPE ABUTMENT ;
    PORT
      LAYER M4 ;
      RECT 0 636.288 0.192 636.312 ;
    END
  END rx_flit[154]
  PIN rx_flit[155]
    DIRECTION OUTPUT ;
    USE SIGNAL ;
    SHAPE ABUTMENT ;
    PORT
      LAYER M4 ;
      RECT 0 636.336 0.192 636.360 ;
    END
  END rx_flit[155]
  PIN rx_flit[156]
    DIRECTION OUTPUT ;
    USE SIGNAL ;
    SHAPE ABUTMENT ;
    PORT
      LAYER M4 ;
      RECT 0 636.384 0.192 636.408 ;
    END
  END rx_flit[156]
  PIN rx_flit[157]
    DIRECTION OUTPUT ;
    USE SIGNAL ;
    SHAPE ABUTMENT ;
    PORT
      LAYER M4 ;
      RECT 0 636.432 0.192 636.456 ;
    END
  END rx_flit[157]
  PIN rx_flit[158]
    DIRECTION OUTPUT ;
    USE SIGNAL ;
    SHAPE ABUTMENT ;
    PORT
      LAYER M4 ;
      RECT 0 636.480 0.192 636.504 ;
    END
  END rx_flit[158]
  PIN rx_flit[159]
    DIRECTION OUTPUT ;
    USE SIGNAL ;
    SHAPE ABUTMENT ;
    PORT
      LAYER M4 ;
      RECT 0 636.528 0.192 636.552 ;
    END
  END rx_flit[159]
  PIN rx_flit[160]
    DIRECTION OUTPUT ;
    USE SIGNAL ;
    SHAPE ABUTMENT ;
    PORT
      LAYER M4 ;
      RECT 0 636.576 0.192 636.600 ;
    END
  END rx_flit[160]
  PIN rx_flit[161]
    DIRECTION OUTPUT ;
    USE SIGNAL ;
    SHAPE ABUTMENT ;
    PORT
      LAYER M4 ;
      RECT 0 636.624 0.192 636.648 ;
    END
  END rx_flit[161]
  PIN rx_flit[162]
    DIRECTION OUTPUT ;
    USE SIGNAL ;
    SHAPE ABUTMENT ;
    PORT
      LAYER M4 ;
      RECT 0 636.672 0.192 636.696 ;
    END
  END rx_flit[162]
  PIN rx_flit[163]
    DIRECTION OUTPUT ;
    USE SIGNAL ;
    SHAPE ABUTMENT ;
    PORT
      LAYER M4 ;
      RECT 0 636.720 0.192 636.744 ;
    END
  END rx_flit[163]
  PIN rx_flit[164]
    DIRECTION OUTPUT ;
    USE SIGNAL ;
    SHAPE ABUTMENT ;
    PORT
      LAYER M4 ;
      RECT 0 636.768 0.192 636.792 ;
    END
  END rx_flit[164]
  PIN rx_flit[165]
    DIRECTION OUTPUT ;
    USE SIGNAL ;
    SHAPE ABUTMENT ;
    PORT
      LAYER M4 ;
      RECT 0 636.816 0.192 636.840 ;
    END
  END rx_flit[165]
  PIN rx_flit[166]
    DIRECTION OUTPUT ;
    USE SIGNAL ;
    SHAPE ABUTMENT ;
    PORT
      LAYER M4 ;
      RECT 0 636.864 0.192 636.888 ;
    END
  END rx_flit[166]
  PIN rx_flit[167]
    DIRECTION OUTPUT ;
    USE SIGNAL ;
    SHAPE ABUTMENT ;
    PORT
      LAYER M4 ;
      RECT 0 636.912 0.192 636.936 ;
    END
  END rx_flit[167]
  PIN rx_flit[168]
    DIRECTION OUTPUT ;
    USE SIGNAL ;
    SHAPE ABUTMENT ;
    PORT
      LAYER M4 ;
      RECT 0 636.960 0.192 636.984 ;
    END
  END rx_flit[168]
  PIN rx_flit[169]
    DIRECTION OUTPUT ;
    USE SIGNAL ;
    SHAPE ABUTMENT ;
    PORT
      LAYER M4 ;
      RECT 0 637.008 0.192 637.032 ;
    END
  END rx_flit[169]
  PIN rx_flit[170]
    DIRECTION OUTPUT ;
    USE SIGNAL ;
    SHAPE ABUTMENT ;
    PORT
      LAYER M4 ;
      RECT 0 637.056 0.192 637.080 ;
    END
  END rx_flit[170]
  PIN rx_flit[171]
    DIRECTION OUTPUT ;
    USE SIGNAL ;
    SHAPE ABUTMENT ;
    PORT
      LAYER M4 ;
      RECT 0 637.104 0.192 637.128 ;
    END
  END rx_flit[171]
  PIN rx_flit[172]
    DIRECTION OUTPUT ;
    USE SIGNAL ;
    SHAPE ABUTMENT ;
    PORT
      LAYER M4 ;
      RECT 0 637.152 0.192 637.176 ;
    END
  END rx_flit[172]
  PIN rx_flit[173]
    DIRECTION OUTPUT ;
    USE SIGNAL ;
    SHAPE ABUTMENT ;
    PORT
      LAYER M4 ;
      RECT 0 637.200 0.192 637.224 ;
    END
  END rx_flit[173]
  PIN rx_flit[174]
    DIRECTION OUTPUT ;
    USE SIGNAL ;
    SHAPE ABUTMENT ;
    PORT
      LAYER M4 ;
      RECT 0 637.248 0.192 637.272 ;
    END
  END rx_flit[174]
  PIN rx_flit[175]
    DIRECTION OUTPUT ;
    USE SIGNAL ;
    SHAPE ABUTMENT ;
    PORT
      LAYER M4 ;
      RECT 0 637.296 0.192 637.320 ;
    END
  END rx_flit[175]
  PIN rx_flit[176]
    DIRECTION OUTPUT ;
    USE SIGNAL ;
    SHAPE ABUTMENT ;
    PORT
      LAYER M4 ;
      RECT 0 637.344 0.192 637.368 ;
    END
  END rx_flit[176]
  PIN rx_flit[177]
    DIRECTION OUTPUT ;
    USE SIGNAL ;
    SHAPE ABUTMENT ;
    PORT
      LAYER M4 ;
      RECT 0 637.392 0.192 637.416 ;
    END
  END rx_flit[177]
  PIN rx_flit[178]
    DIRECTION OUTPUT ;
    USE SIGNAL ;
    SHAPE ABUTMENT ;
    PORT
      LAYER M4 ;
      RECT 0 637.440 0.192 637.464 ;
    END
  END rx_flit[178]
  PIN rx_flit[179]
    DIRECTION OUTPUT ;
    USE SIGNAL ;
    SHAPE ABUTMENT ;
    PORT
      LAYER M4 ;
      RECT 0 637.488 0.192 637.512 ;
    END
  END rx_flit[179]
  PIN rx_flit[180]
    DIRECTION OUTPUT ;
    USE SIGNAL ;
    SHAPE ABUTMENT ;
    PORT
      LAYER M4 ;
      RECT 0 637.536 0.192 637.560 ;
    END
  END rx_flit[180]
  PIN rx_flit[181]
    DIRECTION OUTPUT ;
    USE SIGNAL ;
    SHAPE ABUTMENT ;
    PORT
      LAYER M4 ;
      RECT 0 637.584 0.192 637.608 ;
    END
  END rx_flit[181]
  PIN rx_flit[182]
    DIRECTION OUTPUT ;
    USE SIGNAL ;
    SHAPE ABUTMENT ;
    PORT
      LAYER M4 ;
      RECT 0 637.632 0.192 637.656 ;
    END
  END rx_flit[182]
  PIN rx_flit[183]
    DIRECTION OUTPUT ;
    USE SIGNAL ;
    SHAPE ABUTMENT ;
    PORT
      LAYER M4 ;
      RECT 0 637.680 0.192 637.704 ;
    END
  END rx_flit[183]
  PIN rx_flit[184]
    DIRECTION OUTPUT ;
    USE SIGNAL ;
    SHAPE ABUTMENT ;
    PORT
      LAYER M4 ;
      RECT 0 637.728 0.192 637.752 ;
    END
  END rx_flit[184]
  PIN rx_flit[185]
    DIRECTION OUTPUT ;
    USE SIGNAL ;
    SHAPE ABUTMENT ;
    PORT
      LAYER M4 ;
      RECT 0 637.776 0.192 637.800 ;
    END
  END rx_flit[185]
  PIN rx_flit[186]
    DIRECTION OUTPUT ;
    USE SIGNAL ;
    SHAPE ABUTMENT ;
    PORT
      LAYER M4 ;
      RECT 0 637.824 0.192 637.848 ;
    END
  END rx_flit[186]
  PIN rx_flit[187]
    DIRECTION OUTPUT ;
    USE SIGNAL ;
    SHAPE ABUTMENT ;
    PORT
      LAYER M4 ;
      RECT 0 637.872 0.192 637.896 ;
    END
  END rx_flit[187]
  PIN rx_flit[188]
    DIRECTION OUTPUT ;
    USE SIGNAL ;
    SHAPE ABUTMENT ;
    PORT
      LAYER M4 ;
      RECT 0 637.920 0.192 637.944 ;
    END
  END rx_flit[188]
  PIN rx_flit[189]
    DIRECTION OUTPUT ;
    USE SIGNAL ;
    SHAPE ABUTMENT ;
    PORT
      LAYER M4 ;
      RECT 0 637.968 0.192 637.992 ;
    END
  END rx_flit[189]
  PIN rx_flit[190]
    DIRECTION OUTPUT ;
    USE SIGNAL ;
    SHAPE ABUTMENT ;
    PORT
      LAYER M4 ;
      RECT 0 638.016 0.192 638.040 ;
    END
  END rx_flit[190]
  PIN rx_flit[191]
    DIRECTION OUTPUT ;
    USE SIGNAL ;
    SHAPE ABUTMENT ;
    PORT
      LAYER M4 ;
      RECT 0 638.064 0.192 638.088 ;
    END
  END rx_flit[191]
  PIN rx_flit[192]
    DIRECTION OUTPUT ;
    USE SIGNAL ;
    SHAPE ABUTMENT ;
    PORT
      LAYER M4 ;
      RECT 0 638.112 0.192 638.136 ;
    END
  END rx_flit[192]
  PIN rx_flit[193]
    DIRECTION OUTPUT ;
    USE SIGNAL ;
    SHAPE ABUTMENT ;
    PORT
      LAYER M4 ;
      RECT 0 638.160 0.192 638.184 ;
    END
  END rx_flit[193]
  PIN rx_flit[194]
    DIRECTION OUTPUT ;
    USE SIGNAL ;
    SHAPE ABUTMENT ;
    PORT
      LAYER M4 ;
      RECT 0 638.208 0.192 638.232 ;
    END
  END rx_flit[194]
  PIN rx_flit[195]
    DIRECTION OUTPUT ;
    USE SIGNAL ;
    SHAPE ABUTMENT ;
    PORT
      LAYER M4 ;
      RECT 0 638.256 0.192 638.280 ;
    END
  END rx_flit[195]
  PIN rx_flit[196]
    DIRECTION OUTPUT ;
    USE SIGNAL ;
    SHAPE ABUTMENT ;
    PORT
      LAYER M4 ;
      RECT 0 638.304 0.192 638.328 ;
    END
  END rx_flit[196]
  PIN rx_flit[197]
    DIRECTION OUTPUT ;
    USE SIGNAL ;
    SHAPE ABUTMENT ;
    PORT
      LAYER M4 ;
      RECT 0 638.352 0.192 638.376 ;
    END
  END rx_flit[197]
  PIN rx_flit[198]
    DIRECTION OUTPUT ;
    USE SIGNAL ;
    SHAPE ABUTMENT ;
    PORT
      LAYER M4 ;
      RECT 0 638.400 0.192 638.424 ;
    END
  END rx_flit[198]
  PIN rx_flit[199]
    DIRECTION OUTPUT ;
    USE SIGNAL ;
    SHAPE ABUTMENT ;
    PORT
      LAYER M4 ;
      RECT 0 638.448 0.192 638.472 ;
    END
  END rx_flit[199]
  PIN rx_flit[200]
    DIRECTION OUTPUT ;
    USE SIGNAL ;
    SHAPE ABUTMENT ;
    PORT
      LAYER M4 ;
      RECT 0 638.496 0.192 638.520 ;
    END
  END rx_flit[200]
  PIN rx_flit[201]
    DIRECTION OUTPUT ;
    USE SIGNAL ;
    SHAPE ABUTMENT ;
    PORT
      LAYER M4 ;
      RECT 0 638.544 0.192 638.568 ;
    END
  END rx_flit[201]
  PIN rx_flit[202]
    DIRECTION OUTPUT ;
    USE SIGNAL ;
    SHAPE ABUTMENT ;
    PORT
      LAYER M4 ;
      RECT 0 638.592 0.192 638.616 ;
    END
  END rx_flit[202]
  PIN rx_flit[203]
    DIRECTION OUTPUT ;
    USE SIGNAL ;
    SHAPE ABUTMENT ;
    PORT
      LAYER M4 ;
      RECT 0 638.640 0.192 638.664 ;
    END
  END rx_flit[203]
  PIN rx_flit[204]
    DIRECTION OUTPUT ;
    USE SIGNAL ;
    SHAPE ABUTMENT ;
    PORT
      LAYER M4 ;
      RECT 0 638.688 0.192 638.712 ;
    END
  END rx_flit[204]
  PIN rx_flit[205]
    DIRECTION OUTPUT ;
    USE SIGNAL ;
    SHAPE ABUTMENT ;
    PORT
      LAYER M4 ;
      RECT 0 638.736 0.192 638.760 ;
    END
  END rx_flit[205]
  PIN rx_flit[206]
    DIRECTION OUTPUT ;
    USE SIGNAL ;
    SHAPE ABUTMENT ;
    PORT
      LAYER M4 ;
      RECT 0 638.784 0.192 638.808 ;
    END
  END rx_flit[206]
  PIN rx_flit[207]
    DIRECTION OUTPUT ;
    USE SIGNAL ;
    SHAPE ABUTMENT ;
    PORT
      LAYER M4 ;
      RECT 0 638.832 0.192 638.856 ;
    END
  END rx_flit[207]
  PIN rx_flit[208]
    DIRECTION OUTPUT ;
    USE SIGNAL ;
    SHAPE ABUTMENT ;
    PORT
      LAYER M4 ;
      RECT 0 638.880 0.192 638.904 ;
    END
  END rx_flit[208]
  PIN rx_flit[209]
    DIRECTION OUTPUT ;
    USE SIGNAL ;
    SHAPE ABUTMENT ;
    PORT
      LAYER M4 ;
      RECT 0 638.928 0.192 638.952 ;
    END
  END rx_flit[209]
  PIN rx_flit[210]
    DIRECTION OUTPUT ;
    USE SIGNAL ;
    SHAPE ABUTMENT ;
    PORT
      LAYER M4 ;
      RECT 0 638.976 0.192 639.000 ;
    END
  END rx_flit[210]
  PIN rx_flit[211]
    DIRECTION OUTPUT ;
    USE SIGNAL ;
    SHAPE ABUTMENT ;
    PORT
      LAYER M4 ;
      RECT 0 639.024 0.192 639.048 ;
    END
  END rx_flit[211]
  PIN rx_flit[212]
    DIRECTION OUTPUT ;
    USE SIGNAL ;
    SHAPE ABUTMENT ;
    PORT
      LAYER M4 ;
      RECT 0 639.072 0.192 639.096 ;
    END
  END rx_flit[212]
  PIN rx_flit[213]
    DIRECTION OUTPUT ;
    USE SIGNAL ;
    SHAPE ABUTMENT ;
    PORT
      LAYER M4 ;
      RECT 0 639.120 0.192 639.144 ;
    END
  END rx_flit[213]
  PIN rx_flit[214]
    DIRECTION OUTPUT ;
    USE SIGNAL ;
    SHAPE ABUTMENT ;
    PORT
      LAYER M4 ;
      RECT 0 639.168 0.192 639.192 ;
    END
  END rx_flit[214]
  PIN rx_flit[215]
    DIRECTION OUTPUT ;
    USE SIGNAL ;
    SHAPE ABUTMENT ;
    PORT
      LAYER M4 ;
      RECT 0 639.216 0.192 639.240 ;
    END
  END rx_flit[215]
  PIN rx_flit[216]
    DIRECTION OUTPUT ;
    USE SIGNAL ;
    SHAPE ABUTMENT ;
    PORT
      LAYER M4 ;
      RECT 0 639.264 0.192 639.288 ;
    END
  END rx_flit[216]
  PIN rx_flit[217]
    DIRECTION OUTPUT ;
    USE SIGNAL ;
    SHAPE ABUTMENT ;
    PORT
      LAYER M4 ;
      RECT 0 639.312 0.192 639.336 ;
    END
  END rx_flit[217]
  PIN rx_flit[218]
    DIRECTION OUTPUT ;
    USE SIGNAL ;
    SHAPE ABUTMENT ;
    PORT
      LAYER M4 ;
      RECT 0 639.360 0.192 639.384 ;
    END
  END rx_flit[218]
  PIN rx_flit[219]
    DIRECTION OUTPUT ;
    USE SIGNAL ;
    SHAPE ABUTMENT ;
    PORT
      LAYER M4 ;
      RECT 0 639.408 0.192 639.432 ;
    END
  END rx_flit[219]
  PIN rx_flit[220]
    DIRECTION OUTPUT ;
    USE SIGNAL ;
    SHAPE ABUTMENT ;
    PORT
      LAYER M4 ;
      RECT 0 639.456 0.192 639.480 ;
    END
  END rx_flit[220]
  PIN rx_flit[221]
    DIRECTION OUTPUT ;
    USE SIGNAL ;
    SHAPE ABUTMENT ;
    PORT
      LAYER M4 ;
      RECT 0 639.504 0.192 639.528 ;
    END
  END rx_flit[221]
  PIN rx_flit[222]
    DIRECTION OUTPUT ;
    USE SIGNAL ;
    SHAPE ABUTMENT ;
    PORT
      LAYER M4 ;
      RECT 0 639.552 0.192 639.576 ;
    END
  END rx_flit[222]
  PIN rx_flit[223]
    DIRECTION OUTPUT ;
    USE SIGNAL ;
    SHAPE ABUTMENT ;
    PORT
      LAYER M4 ;
      RECT 0 639.600 0.192 639.624 ;
    END
  END rx_flit[223]
  PIN rx_flit[224]
    DIRECTION OUTPUT ;
    USE SIGNAL ;
    SHAPE ABUTMENT ;
    PORT
      LAYER M4 ;
      RECT 0 639.648 0.192 639.672 ;
    END
  END rx_flit[224]
  PIN rx_flit[225]
    DIRECTION OUTPUT ;
    USE SIGNAL ;
    SHAPE ABUTMENT ;
    PORT
      LAYER M4 ;
      RECT 0 639.696 0.192 639.720 ;
    END
  END rx_flit[225]
  PIN rx_flit[226]
    DIRECTION OUTPUT ;
    USE SIGNAL ;
    SHAPE ABUTMENT ;
    PORT
      LAYER M4 ;
      RECT 0 639.744 0.192 639.768 ;
    END
  END rx_flit[226]
  PIN rx_flit[227]
    DIRECTION OUTPUT ;
    USE SIGNAL ;
    SHAPE ABUTMENT ;
    PORT
      LAYER M4 ;
      RECT 0 639.792 0.192 639.816 ;
    END
  END rx_flit[227]
  PIN rx_flit[228]
    DIRECTION OUTPUT ;
    USE SIGNAL ;
    SHAPE ABUTMENT ;
    PORT
      LAYER M4 ;
      RECT 0 639.840 0.192 639.864 ;
    END
  END rx_flit[228]
  PIN rx_flit[229]
    DIRECTION OUTPUT ;
    USE SIGNAL ;
    SHAPE ABUTMENT ;
    PORT
      LAYER M4 ;
      RECT 0 639.888 0.192 639.912 ;
    END
  END rx_flit[229]
  PIN rx_flit[230]
    DIRECTION OUTPUT ;
    USE SIGNAL ;
    SHAPE ABUTMENT ;
    PORT
      LAYER M4 ;
      RECT 0 639.936 0.192 639.960 ;
    END
  END rx_flit[230]
  PIN rx_flit[231]
    DIRECTION OUTPUT ;
    USE SIGNAL ;
    SHAPE ABUTMENT ;
    PORT
      LAYER M4 ;
      RECT 0 639.984 0.192 640.008 ;
    END
  END rx_flit[231]
  PIN rx_flit[232]
    DIRECTION OUTPUT ;
    USE SIGNAL ;
    SHAPE ABUTMENT ;
    PORT
      LAYER M4 ;
      RECT 0 640.032 0.192 640.056 ;
    END
  END rx_flit[232]
  PIN rx_flit[233]
    DIRECTION OUTPUT ;
    USE SIGNAL ;
    SHAPE ABUTMENT ;
    PORT
      LAYER M4 ;
      RECT 0 640.080 0.192 640.104 ;
    END
  END rx_flit[233]
  PIN rx_flit[234]
    DIRECTION OUTPUT ;
    USE SIGNAL ;
    SHAPE ABUTMENT ;
    PORT
      LAYER M4 ;
      RECT 0 640.128 0.192 640.152 ;
    END
  END rx_flit[234]
  PIN rx_flit[235]
    DIRECTION OUTPUT ;
    USE SIGNAL ;
    SHAPE ABUTMENT ;
    PORT
      LAYER M4 ;
      RECT 0 640.176 0.192 640.200 ;
    END
  END rx_flit[235]
  PIN rx_flit[236]
    DIRECTION OUTPUT ;
    USE SIGNAL ;
    SHAPE ABUTMENT ;
    PORT
      LAYER M4 ;
      RECT 0 640.224 0.192 640.248 ;
    END
  END rx_flit[236]
  PIN rx_flit[237]
    DIRECTION OUTPUT ;
    USE SIGNAL ;
    SHAPE ABUTMENT ;
    PORT
      LAYER M4 ;
      RECT 0 640.272 0.192 640.296 ;
    END
  END rx_flit[237]
  PIN rx_flit[238]
    DIRECTION OUTPUT ;
    USE SIGNAL ;
    SHAPE ABUTMENT ;
    PORT
      LAYER M4 ;
      RECT 0 640.320 0.192 640.344 ;
    END
  END rx_flit[238]
  PIN rx_flit[239]
    DIRECTION OUTPUT ;
    USE SIGNAL ;
    SHAPE ABUTMENT ;
    PORT
      LAYER M4 ;
      RECT 0 640.368 0.192 640.392 ;
    END
  END rx_flit[239]
  PIN rx_flit[240]
    DIRECTION OUTPUT ;
    USE SIGNAL ;
    SHAPE ABUTMENT ;
    PORT
      LAYER M4 ;
      RECT 0 640.416 0.192 640.440 ;
    END
  END rx_flit[240]
  PIN rx_flit[241]
    DIRECTION OUTPUT ;
    USE SIGNAL ;
    SHAPE ABUTMENT ;
    PORT
      LAYER M4 ;
      RECT 0 640.464 0.192 640.488 ;
    END
  END rx_flit[241]
  PIN rx_flit[242]
    DIRECTION OUTPUT ;
    USE SIGNAL ;
    SHAPE ABUTMENT ;
    PORT
      LAYER M4 ;
      RECT 0 640.512 0.192 640.536 ;
    END
  END rx_flit[242]
  PIN rx_flit[243]
    DIRECTION OUTPUT ;
    USE SIGNAL ;
    SHAPE ABUTMENT ;
    PORT
      LAYER M4 ;
      RECT 0 640.560 0.192 640.584 ;
    END
  END rx_flit[243]
  PIN rx_flit[244]
    DIRECTION OUTPUT ;
    USE SIGNAL ;
    SHAPE ABUTMENT ;
    PORT
      LAYER M4 ;
      RECT 0 640.608 0.192 640.632 ;
    END
  END rx_flit[244]
  PIN rx_flit[245]
    DIRECTION OUTPUT ;
    USE SIGNAL ;
    SHAPE ABUTMENT ;
    PORT
      LAYER M4 ;
      RECT 0 640.656 0.192 640.680 ;
    END
  END rx_flit[245]
  PIN rx_flit[246]
    DIRECTION OUTPUT ;
    USE SIGNAL ;
    SHAPE ABUTMENT ;
    PORT
      LAYER M4 ;
      RECT 0 640.704 0.192 640.728 ;
    END
  END rx_flit[246]
  PIN rx_flit[247]
    DIRECTION OUTPUT ;
    USE SIGNAL ;
    SHAPE ABUTMENT ;
    PORT
      LAYER M4 ;
      RECT 0 640.752 0.192 640.776 ;
    END
  END rx_flit[247]
  PIN rx_flit[248]
    DIRECTION OUTPUT ;
    USE SIGNAL ;
    SHAPE ABUTMENT ;
    PORT
      LAYER M4 ;
      RECT 0 640.800 0.192 640.824 ;
    END
  END rx_flit[248]
  PIN rx_flit[249]
    DIRECTION OUTPUT ;
    USE SIGNAL ;
    SHAPE ABUTMENT ;
    PORT
      LAYER M4 ;
      RECT 0 640.848 0.192 640.872 ;
    END
  END rx_flit[249]
  PIN rx_flit[250]
    DIRECTION OUTPUT ;
    USE SIGNAL ;
    SHAPE ABUTMENT ;
    PORT
      LAYER M4 ;
      RECT 0 640.896 0.192 640.920 ;
    END
  END rx_flit[250]
  PIN rx_flit[251]
    DIRECTION OUTPUT ;
    USE SIGNAL ;
    SHAPE ABUTMENT ;
    PORT
      LAYER M4 ;
      RECT 0 640.944 0.192 640.968 ;
    END
  END rx_flit[251]
  PIN rx_flit[252]
    DIRECTION OUTPUT ;
    USE SIGNAL ;
    SHAPE ABUTMENT ;
    PORT
      LAYER M4 ;
      RECT 0 640.992 0.192 641.016 ;
    END
  END rx_flit[252]
  PIN rx_flit[253]
    DIRECTION OUTPUT ;
    USE SIGNAL ;
    SHAPE ABUTMENT ;
    PORT
      LAYER M4 ;
      RECT 0 641.040 0.192 641.064 ;
    END
  END rx_flit[253]
  PIN rx_flit[254]
    DIRECTION OUTPUT ;
    USE SIGNAL ;
    SHAPE ABUTMENT ;
    PORT
      LAYER M4 ;
      RECT 0 641.088 0.192 641.112 ;
    END
  END rx_flit[254]
  PIN rx_flit[255]
    DIRECTION OUTPUT ;
    USE SIGNAL ;
    SHAPE ABUTMENT ;
    PORT
      LAYER M4 ;
      RECT 0 641.136 0.192 641.160 ;
    END
  END rx_flit[255]
  PIN rx_flit[256]
    DIRECTION OUTPUT ;
    USE SIGNAL ;
    SHAPE ABUTMENT ;
    PORT
      LAYER M4 ;
      RECT 0 641.184 0.192 641.208 ;
    END
  END rx_flit[256]
  PIN rx_flit[257]
    DIRECTION OUTPUT ;
    USE SIGNAL ;
    SHAPE ABUTMENT ;
    PORT
      LAYER M4 ;
      RECT 0 641.232 0.192 641.256 ;
    END
  END rx_flit[257]
  PIN rx_flit[258]
    DIRECTION OUTPUT ;
    USE SIGNAL ;
    SHAPE ABUTMENT ;
    PORT
      LAYER M4 ;
      RECT 0 641.280 0.192 641.304 ;
    END
  END rx_flit[258]
  PIN rx_flit[259]
    DIRECTION OUTPUT ;
    USE SIGNAL ;
    SHAPE ABUTMENT ;
    PORT
      LAYER M4 ;
      RECT 0 641.328 0.192 641.352 ;
    END
  END rx_flit[259]
  PIN rx_flit[260]
    DIRECTION OUTPUT ;
    USE SIGNAL ;
    SHAPE ABUTMENT ;
    PORT
      LAYER M4 ;
      RECT 0 641.376 0.192 641.400 ;
    END
  END rx_flit[260]
  PIN rx_flit[261]
    DIRECTION OUTPUT ;
    USE SIGNAL ;
    SHAPE ABUTMENT ;
    PORT
      LAYER M4 ;
      RECT 0 641.424 0.192 641.448 ;
    END
  END rx_flit[261]
  PIN rx_flit[262]
    DIRECTION OUTPUT ;
    USE SIGNAL ;
    SHAPE ABUTMENT ;
    PORT
      LAYER M4 ;
      RECT 0 641.472 0.192 641.496 ;
    END
  END rx_flit[262]
  PIN rx_flit[263]
    DIRECTION OUTPUT ;
    USE SIGNAL ;
    SHAPE ABUTMENT ;
    PORT
      LAYER M4 ;
      RECT 0 641.520 0.192 641.544 ;
    END
  END rx_flit[263]
  PIN rx_flit[264]
    DIRECTION OUTPUT ;
    USE SIGNAL ;
    SHAPE ABUTMENT ;
    PORT
      LAYER M4 ;
      RECT 0 641.568 0.192 641.592 ;
    END
  END rx_flit[264]
  PIN rx_flit[265]
    DIRECTION OUTPUT ;
    USE SIGNAL ;
    SHAPE ABUTMENT ;
    PORT
      LAYER M4 ;
      RECT 0 641.616 0.192 641.640 ;
    END
  END rx_flit[265]
  PIN rx_flit[266]
    DIRECTION OUTPUT ;
    USE SIGNAL ;
    SHAPE ABUTMENT ;
    PORT
      LAYER M4 ;
      RECT 0 641.664 0.192 641.688 ;
    END
  END rx_flit[266]
  PIN rx_flit[267]
    DIRECTION OUTPUT ;
    USE SIGNAL ;
    SHAPE ABUTMENT ;
    PORT
      LAYER M4 ;
      RECT 0 641.712 0.192 641.736 ;
    END
  END rx_flit[267]
  PIN rx_flit[268]
    DIRECTION OUTPUT ;
    USE SIGNAL ;
    SHAPE ABUTMENT ;
    PORT
      LAYER M4 ;
      RECT 0 641.760 0.192 641.784 ;
    END
  END rx_flit[268]
  PIN rx_flit[269]
    DIRECTION OUTPUT ;
    USE SIGNAL ;
    SHAPE ABUTMENT ;
    PORT
      LAYER M4 ;
      RECT 0 641.808 0.192 641.832 ;
    END
  END rx_flit[269]
  PIN rx_flit[270]
    DIRECTION OUTPUT ;
    USE SIGNAL ;
    SHAPE ABUTMENT ;
    PORT
      LAYER M4 ;
      RECT 0 641.856 0.192 641.880 ;
    END
  END rx_flit[270]
  PIN rx_flit[271]
    DIRECTION OUTPUT ;
    USE SIGNAL ;
    SHAPE ABUTMENT ;
    PORT
      LAYER M4 ;
      RECT 0 641.904 0.192 641.928 ;
    END
  END rx_flit[271]
  PIN rx_flit[272]
    DIRECTION OUTPUT ;
    USE SIGNAL ;
    SHAPE ABUTMENT ;
    PORT
      LAYER M4 ;
      RECT 0 641.952 0.192 641.976 ;
    END
  END rx_flit[272]
  PIN rx_flit[273]
    DIRECTION OUTPUT ;
    USE SIGNAL ;
    SHAPE ABUTMENT ;
    PORT
      LAYER M4 ;
      RECT 0 642.000 0.192 642.024 ;
    END
  END rx_flit[273]
  PIN rx_flit[274]
    DIRECTION OUTPUT ;
    USE SIGNAL ;
    SHAPE ABUTMENT ;
    PORT
      LAYER M4 ;
      RECT 0 642.048 0.192 642.072 ;
    END
  END rx_flit[274]
  PIN rx_flit[275]
    DIRECTION OUTPUT ;
    USE SIGNAL ;
    SHAPE ABUTMENT ;
    PORT
      LAYER M4 ;
      RECT 0 642.096 0.192 642.120 ;
    END
  END rx_flit[275]
  PIN rx_flit[276]
    DIRECTION OUTPUT ;
    USE SIGNAL ;
    SHAPE ABUTMENT ;
    PORT
      LAYER M4 ;
      RECT 0 642.144 0.192 642.168 ;
    END
  END rx_flit[276]
  PIN rx_flit[277]
    DIRECTION OUTPUT ;
    USE SIGNAL ;
    SHAPE ABUTMENT ;
    PORT
      LAYER M4 ;
      RECT 0 642.192 0.192 642.216 ;
    END
  END rx_flit[277]
  PIN rx_flit[278]
    DIRECTION OUTPUT ;
    USE SIGNAL ;
    SHAPE ABUTMENT ;
    PORT
      LAYER M4 ;
      RECT 0 642.240 0.192 642.264 ;
    END
  END rx_flit[278]
  PIN rx_flit[279]
    DIRECTION OUTPUT ;
    USE SIGNAL ;
    SHAPE ABUTMENT ;
    PORT
      LAYER M4 ;
      RECT 0 642.288 0.192 642.312 ;
    END
  END rx_flit[279]
  PIN rx_flit[280]
    DIRECTION OUTPUT ;
    USE SIGNAL ;
    SHAPE ABUTMENT ;
    PORT
      LAYER M4 ;
      RECT 0 642.336 0.192 642.360 ;
    END
  END rx_flit[280]
  PIN rx_flit[281]
    DIRECTION OUTPUT ;
    USE SIGNAL ;
    SHAPE ABUTMENT ;
    PORT
      LAYER M4 ;
      RECT 0 642.384 0.192 642.408 ;
    END
  END rx_flit[281]
  PIN rx_flit[282]
    DIRECTION OUTPUT ;
    USE SIGNAL ;
    SHAPE ABUTMENT ;
    PORT
      LAYER M4 ;
      RECT 0 642.432 0.192 642.456 ;
    END
  END rx_flit[282]
  PIN rx_flit[283]
    DIRECTION OUTPUT ;
    USE SIGNAL ;
    SHAPE ABUTMENT ;
    PORT
      LAYER M4 ;
      RECT 0 642.480 0.192 642.504 ;
    END
  END rx_flit[283]
  PIN rx_flit[284]
    DIRECTION OUTPUT ;
    USE SIGNAL ;
    SHAPE ABUTMENT ;
    PORT
      LAYER M4 ;
      RECT 0 642.528 0.192 642.552 ;
    END
  END rx_flit[284]
  PIN rx_flit[285]
    DIRECTION OUTPUT ;
    USE SIGNAL ;
    SHAPE ABUTMENT ;
    PORT
      LAYER M4 ;
      RECT 0 642.576 0.192 642.600 ;
    END
  END rx_flit[285]
  PIN rx_flit[286]
    DIRECTION OUTPUT ;
    USE SIGNAL ;
    SHAPE ABUTMENT ;
    PORT
      LAYER M4 ;
      RECT 0 642.624 0.192 642.648 ;
    END
  END rx_flit[286]
  PIN rx_flit[287]
    DIRECTION OUTPUT ;
    USE SIGNAL ;
    SHAPE ABUTMENT ;
    PORT
      LAYER M4 ;
      RECT 0 642.672 0.192 642.696 ;
    END
  END rx_flit[287]
  PIN rx_flit[288]
    DIRECTION OUTPUT ;
    USE SIGNAL ;
    SHAPE ABUTMENT ;
    PORT
      LAYER M4 ;
      RECT 0 642.720 0.192 642.744 ;
    END
  END rx_flit[288]
  PIN rx_flit[289]
    DIRECTION OUTPUT ;
    USE SIGNAL ;
    SHAPE ABUTMENT ;
    PORT
      LAYER M4 ;
      RECT 0 642.768 0.192 642.792 ;
    END
  END rx_flit[289]
  PIN rx_flit[290]
    DIRECTION OUTPUT ;
    USE SIGNAL ;
    SHAPE ABUTMENT ;
    PORT
      LAYER M4 ;
      RECT 0 642.816 0.192 642.840 ;
    END
  END rx_flit[290]
  PIN rx_flit[291]
    DIRECTION OUTPUT ;
    USE SIGNAL ;
    SHAPE ABUTMENT ;
    PORT
      LAYER M4 ;
      RECT 0 642.864 0.192 642.888 ;
    END
  END rx_flit[291]
  PIN rx_flit[292]
    DIRECTION OUTPUT ;
    USE SIGNAL ;
    SHAPE ABUTMENT ;
    PORT
      LAYER M4 ;
      RECT 0 642.912 0.192 642.936 ;
    END
  END rx_flit[292]
  PIN rx_flit[293]
    DIRECTION OUTPUT ;
    USE SIGNAL ;
    SHAPE ABUTMENT ;
    PORT
      LAYER M4 ;
      RECT 0 642.960 0.192 642.984 ;
    END
  END rx_flit[293]
  PIN rx_flit[294]
    DIRECTION OUTPUT ;
    USE SIGNAL ;
    SHAPE ABUTMENT ;
    PORT
      LAYER M4 ;
      RECT 0 643.008 0.192 643.032 ;
    END
  END rx_flit[294]
  PIN rx_flit[295]
    DIRECTION OUTPUT ;
    USE SIGNAL ;
    SHAPE ABUTMENT ;
    PORT
      LAYER M4 ;
      RECT 0 643.056 0.192 643.080 ;
    END
  END rx_flit[295]
  PIN rx_flit[296]
    DIRECTION OUTPUT ;
    USE SIGNAL ;
    SHAPE ABUTMENT ;
    PORT
      LAYER M4 ;
      RECT 0 643.104 0.192 643.128 ;
    END
  END rx_flit[296]
  PIN rx_flit[297]
    DIRECTION OUTPUT ;
    USE SIGNAL ;
    SHAPE ABUTMENT ;
    PORT
      LAYER M4 ;
      RECT 0 643.152 0.192 643.176 ;
    END
  END rx_flit[297]
  PIN rx_flit[298]
    DIRECTION OUTPUT ;
    USE SIGNAL ;
    SHAPE ABUTMENT ;
    PORT
      LAYER M4 ;
      RECT 0 643.200 0.192 643.224 ;
    END
  END rx_flit[298]
  PIN rx_flit[299]
    DIRECTION OUTPUT ;
    USE SIGNAL ;
    SHAPE ABUTMENT ;
    PORT
      LAYER M4 ;
      RECT 0 643.248 0.192 643.272 ;
    END
  END rx_flit[299]
  PIN rx_flit[300]
    DIRECTION OUTPUT ;
    USE SIGNAL ;
    SHAPE ABUTMENT ;
    PORT
      LAYER M4 ;
      RECT 0 643.296 0.192 643.320 ;
    END
  END rx_flit[300]
  PIN rx_flit[301]
    DIRECTION OUTPUT ;
    USE SIGNAL ;
    SHAPE ABUTMENT ;
    PORT
      LAYER M4 ;
      RECT 0 643.344 0.192 643.368 ;
    END
  END rx_flit[301]
  PIN rx_flit[302]
    DIRECTION OUTPUT ;
    USE SIGNAL ;
    SHAPE ABUTMENT ;
    PORT
      LAYER M4 ;
      RECT 0 643.392 0.192 643.416 ;
    END
  END rx_flit[302]
  PIN rx_flit[303]
    DIRECTION OUTPUT ;
    USE SIGNAL ;
    SHAPE ABUTMENT ;
    PORT
      LAYER M4 ;
      RECT 0 643.440 0.192 643.464 ;
    END
  END rx_flit[303]
  PIN rx_flit[304]
    DIRECTION OUTPUT ;
    USE SIGNAL ;
    SHAPE ABUTMENT ;
    PORT
      LAYER M4 ;
      RECT 0 643.488 0.192 643.512 ;
    END
  END rx_flit[304]
  PIN rx_flit[305]
    DIRECTION OUTPUT ;
    USE SIGNAL ;
    SHAPE ABUTMENT ;
    PORT
      LAYER M4 ;
      RECT 0 643.536 0.192 643.560 ;
    END
  END rx_flit[305]
  PIN rx_flit[306]
    DIRECTION OUTPUT ;
    USE SIGNAL ;
    SHAPE ABUTMENT ;
    PORT
      LAYER M4 ;
      RECT 0 643.584 0.192 643.608 ;
    END
  END rx_flit[306]
  PIN rx_flit[307]
    DIRECTION OUTPUT ;
    USE SIGNAL ;
    SHAPE ABUTMENT ;
    PORT
      LAYER M4 ;
      RECT 0 643.632 0.192 643.656 ;
    END
  END rx_flit[307]
  PIN rx_flit[308]
    DIRECTION OUTPUT ;
    USE SIGNAL ;
    SHAPE ABUTMENT ;
    PORT
      LAYER M4 ;
      RECT 0 643.680 0.192 643.704 ;
    END
  END rx_flit[308]
  PIN rx_flit[309]
    DIRECTION OUTPUT ;
    USE SIGNAL ;
    SHAPE ABUTMENT ;
    PORT
      LAYER M4 ;
      RECT 0 643.728 0.192 643.752 ;
    END
  END rx_flit[309]
  PIN rx_flit[310]
    DIRECTION OUTPUT ;
    USE SIGNAL ;
    SHAPE ABUTMENT ;
    PORT
      LAYER M4 ;
      RECT 0 643.776 0.192 643.800 ;
    END
  END rx_flit[310]
  PIN rx_flit[311]
    DIRECTION OUTPUT ;
    USE SIGNAL ;
    SHAPE ABUTMENT ;
    PORT
      LAYER M4 ;
      RECT 0 643.824 0.192 643.848 ;
    END
  END rx_flit[311]
  PIN rx_flit[312]
    DIRECTION OUTPUT ;
    USE SIGNAL ;
    SHAPE ABUTMENT ;
    PORT
      LAYER M4 ;
      RECT 0 643.872 0.192 643.896 ;
    END
  END rx_flit[312]
  PIN rx_flit[313]
    DIRECTION OUTPUT ;
    USE SIGNAL ;
    SHAPE ABUTMENT ;
    PORT
      LAYER M4 ;
      RECT 0 643.920 0.192 643.944 ;
    END
  END rx_flit[313]
  PIN rx_flit[314]
    DIRECTION OUTPUT ;
    USE SIGNAL ;
    SHAPE ABUTMENT ;
    PORT
      LAYER M4 ;
      RECT 0 643.968 0.192 643.992 ;
    END
  END rx_flit[314]
  PIN rx_flit[315]
    DIRECTION OUTPUT ;
    USE SIGNAL ;
    SHAPE ABUTMENT ;
    PORT
      LAYER M4 ;
      RECT 0 644.016 0.192 644.040 ;
    END
  END rx_flit[315]
  PIN rx_flit[316]
    DIRECTION OUTPUT ;
    USE SIGNAL ;
    SHAPE ABUTMENT ;
    PORT
      LAYER M4 ;
      RECT 0 644.064 0.192 644.088 ;
    END
  END rx_flit[316]
  PIN rx_flit[317]
    DIRECTION OUTPUT ;
    USE SIGNAL ;
    SHAPE ABUTMENT ;
    PORT
      LAYER M4 ;
      RECT 0 644.112 0.192 644.136 ;
    END
  END rx_flit[317]
  PIN rx_flit[318]
    DIRECTION OUTPUT ;
    USE SIGNAL ;
    SHAPE ABUTMENT ;
    PORT
      LAYER M4 ;
      RECT 0 644.160 0.192 644.184 ;
    END
  END rx_flit[318]
  PIN rx_flit[319]
    DIRECTION OUTPUT ;
    USE SIGNAL ;
    SHAPE ABUTMENT ;
    PORT
      LAYER M4 ;
      RECT 0 644.208 0.192 644.232 ;
    END
  END rx_flit[319]
  PIN rx_flit[320]
    DIRECTION OUTPUT ;
    USE SIGNAL ;
    SHAPE ABUTMENT ;
    PORT
      LAYER M4 ;
      RECT 0 644.256 0.192 644.280 ;
    END
  END rx_flit[320]
  PIN rx_flit[321]
    DIRECTION OUTPUT ;
    USE SIGNAL ;
    SHAPE ABUTMENT ;
    PORT
      LAYER M4 ;
      RECT 0 644.304 0.192 644.328 ;
    END
  END rx_flit[321]
  PIN rx_flit[322]
    DIRECTION OUTPUT ;
    USE SIGNAL ;
    SHAPE ABUTMENT ;
    PORT
      LAYER M4 ;
      RECT 0 644.352 0.192 644.376 ;
    END
  END rx_flit[322]
  PIN rx_flit[323]
    DIRECTION OUTPUT ;
    USE SIGNAL ;
    SHAPE ABUTMENT ;
    PORT
      LAYER M4 ;
      RECT 0 644.400 0.192 644.424 ;
    END
  END rx_flit[323]
  PIN rx_flit[324]
    DIRECTION OUTPUT ;
    USE SIGNAL ;
    SHAPE ABUTMENT ;
    PORT
      LAYER M4 ;
      RECT 0 644.448 0.192 644.472 ;
    END
  END rx_flit[324]
  PIN rx_flit[325]
    DIRECTION OUTPUT ;
    USE SIGNAL ;
    SHAPE ABUTMENT ;
    PORT
      LAYER M4 ;
      RECT 0 644.496 0.192 644.520 ;
    END
  END rx_flit[325]
  PIN rx_flit[326]
    DIRECTION OUTPUT ;
    USE SIGNAL ;
    SHAPE ABUTMENT ;
    PORT
      LAYER M4 ;
      RECT 0 644.544 0.192 644.568 ;
    END
  END rx_flit[326]
  PIN rx_flit[327]
    DIRECTION OUTPUT ;
    USE SIGNAL ;
    SHAPE ABUTMENT ;
    PORT
      LAYER M4 ;
      RECT 0 644.592 0.192 644.616 ;
    END
  END rx_flit[327]
  PIN rx_flit[328]
    DIRECTION OUTPUT ;
    USE SIGNAL ;
    SHAPE ABUTMENT ;
    PORT
      LAYER M4 ;
      RECT 0 644.640 0.192 644.664 ;
    END
  END rx_flit[328]
  PIN rx_flit[329]
    DIRECTION OUTPUT ;
    USE SIGNAL ;
    SHAPE ABUTMENT ;
    PORT
      LAYER M4 ;
      RECT 0 644.688 0.192 644.712 ;
    END
  END rx_flit[329]
  PIN rx_flit[330]
    DIRECTION OUTPUT ;
    USE SIGNAL ;
    SHAPE ABUTMENT ;
    PORT
      LAYER M4 ;
      RECT 0 644.736 0.192 644.760 ;
    END
  END rx_flit[330]
  PIN rx_flit[331]
    DIRECTION OUTPUT ;
    USE SIGNAL ;
    SHAPE ABUTMENT ;
    PORT
      LAYER M4 ;
      RECT 0 644.784 0.192 644.808 ;
    END
  END rx_flit[331]
  PIN rx_flit[332]
    DIRECTION OUTPUT ;
    USE SIGNAL ;
    SHAPE ABUTMENT ;
    PORT
      LAYER M4 ;
      RECT 0 644.832 0.192 644.856 ;
    END
  END rx_flit[332]
  PIN rx_flit[333]
    DIRECTION OUTPUT ;
    USE SIGNAL ;
    SHAPE ABUTMENT ;
    PORT
      LAYER M4 ;
      RECT 0 644.880 0.192 644.904 ;
    END
  END rx_flit[333]
  PIN rx_flit[334]
    DIRECTION OUTPUT ;
    USE SIGNAL ;
    SHAPE ABUTMENT ;
    PORT
      LAYER M4 ;
      RECT 0 644.928 0.192 644.952 ;
    END
  END rx_flit[334]
  PIN rx_flit[335]
    DIRECTION OUTPUT ;
    USE SIGNAL ;
    SHAPE ABUTMENT ;
    PORT
      LAYER M4 ;
      RECT 0 644.976 0.192 645.000 ;
    END
  END rx_flit[335]
  PIN rx_flit[336]
    DIRECTION OUTPUT ;
    USE SIGNAL ;
    SHAPE ABUTMENT ;
    PORT
      LAYER M4 ;
      RECT 0 645.024 0.192 645.048 ;
    END
  END rx_flit[336]
  PIN rx_flit[337]
    DIRECTION OUTPUT ;
    USE SIGNAL ;
    SHAPE ABUTMENT ;
    PORT
      LAYER M4 ;
      RECT 0 645.072 0.192 645.096 ;
    END
  END rx_flit[337]
  PIN rx_flit[338]
    DIRECTION OUTPUT ;
    USE SIGNAL ;
    SHAPE ABUTMENT ;
    PORT
      LAYER M4 ;
      RECT 0 645.120 0.192 645.144 ;
    END
  END rx_flit[338]
  PIN rx_flit[339]
    DIRECTION OUTPUT ;
    USE SIGNAL ;
    SHAPE ABUTMENT ;
    PORT
      LAYER M4 ;
      RECT 0 645.168 0.192 645.192 ;
    END
  END rx_flit[339]
  PIN rx_flit[340]
    DIRECTION OUTPUT ;
    USE SIGNAL ;
    SHAPE ABUTMENT ;
    PORT
      LAYER M4 ;
      RECT 0 645.216 0.192 645.240 ;
    END
  END rx_flit[340]
  PIN rx_flit[341]
    DIRECTION OUTPUT ;
    USE SIGNAL ;
    SHAPE ABUTMENT ;
    PORT
      LAYER M4 ;
      RECT 0 645.264 0.192 645.288 ;
    END
  END rx_flit[341]
  PIN rx_flit[342]
    DIRECTION OUTPUT ;
    USE SIGNAL ;
    SHAPE ABUTMENT ;
    PORT
      LAYER M4 ;
      RECT 0 645.312 0.192 645.336 ;
    END
  END rx_flit[342]
  PIN rx_flit[343]
    DIRECTION OUTPUT ;
    USE SIGNAL ;
    SHAPE ABUTMENT ;
    PORT
      LAYER M4 ;
      RECT 0 645.360 0.192 645.384 ;
    END
  END rx_flit[343]
  PIN rx_flit[344]
    DIRECTION OUTPUT ;
    USE SIGNAL ;
    SHAPE ABUTMENT ;
    PORT
      LAYER M4 ;
      RECT 0 645.408 0.192 645.432 ;
    END
  END rx_flit[344]
  PIN rx_flit[345]
    DIRECTION OUTPUT ;
    USE SIGNAL ;
    SHAPE ABUTMENT ;
    PORT
      LAYER M4 ;
      RECT 0 645.456 0.192 645.480 ;
    END
  END rx_flit[345]
  PIN rx_flit[346]
    DIRECTION OUTPUT ;
    USE SIGNAL ;
    SHAPE ABUTMENT ;
    PORT
      LAYER M4 ;
      RECT 0 645.504 0.192 645.528 ;
    END
  END rx_flit[346]
  PIN rx_flit[347]
    DIRECTION OUTPUT ;
    USE SIGNAL ;
    SHAPE ABUTMENT ;
    PORT
      LAYER M4 ;
      RECT 0 645.552 0.192 645.576 ;
    END
  END rx_flit[347]
  PIN rx_flit[348]
    DIRECTION OUTPUT ;
    USE SIGNAL ;
    SHAPE ABUTMENT ;
    PORT
      LAYER M4 ;
      RECT 0 645.600 0.192 645.624 ;
    END
  END rx_flit[348]
  PIN rx_flit[349]
    DIRECTION OUTPUT ;
    USE SIGNAL ;
    SHAPE ABUTMENT ;
    PORT
      LAYER M4 ;
      RECT 0 645.648 0.192 645.672 ;
    END
  END rx_flit[349]
  PIN rx_flit[350]
    DIRECTION OUTPUT ;
    USE SIGNAL ;
    SHAPE ABUTMENT ;
    PORT
      LAYER M4 ;
      RECT 0 645.696 0.192 645.720 ;
    END
  END rx_flit[350]
  PIN rx_flit[351]
    DIRECTION OUTPUT ;
    USE SIGNAL ;
    SHAPE ABUTMENT ;
    PORT
      LAYER M4 ;
      RECT 0 645.744 0.192 645.768 ;
    END
  END rx_flit[351]
  PIN rx_flit[352]
    DIRECTION OUTPUT ;
    USE SIGNAL ;
    SHAPE ABUTMENT ;
    PORT
      LAYER M4 ;
      RECT 0 645.792 0.192 645.816 ;
    END
  END rx_flit[352]
  PIN rx_flit[353]
    DIRECTION OUTPUT ;
    USE SIGNAL ;
    SHAPE ABUTMENT ;
    PORT
      LAYER M4 ;
      RECT 0 645.840 0.192 645.864 ;
    END
  END rx_flit[353]
  PIN rx_flit[354]
    DIRECTION OUTPUT ;
    USE SIGNAL ;
    SHAPE ABUTMENT ;
    PORT
      LAYER M4 ;
      RECT 0 645.888 0.192 645.912 ;
    END
  END rx_flit[354]
  PIN rx_flit[355]
    DIRECTION OUTPUT ;
    USE SIGNAL ;
    SHAPE ABUTMENT ;
    PORT
      LAYER M4 ;
      RECT 0 645.936 0.192 645.960 ;
    END
  END rx_flit[355]
  PIN rx_flit[356]
    DIRECTION OUTPUT ;
    USE SIGNAL ;
    SHAPE ABUTMENT ;
    PORT
      LAYER M4 ;
      RECT 0 645.984 0.192 646.008 ;
    END
  END rx_flit[356]
  PIN rx_flit[357]
    DIRECTION OUTPUT ;
    USE SIGNAL ;
    SHAPE ABUTMENT ;
    PORT
      LAYER M4 ;
      RECT 0 646.032 0.192 646.056 ;
    END
  END rx_flit[357]
  PIN rx_flit[358]
    DIRECTION OUTPUT ;
    USE SIGNAL ;
    SHAPE ABUTMENT ;
    PORT
      LAYER M4 ;
      RECT 0 646.080 0.192 646.104 ;
    END
  END rx_flit[358]
  PIN rx_flit[359]
    DIRECTION OUTPUT ;
    USE SIGNAL ;
    SHAPE ABUTMENT ;
    PORT
      LAYER M4 ;
      RECT 0 646.128 0.192 646.152 ;
    END
  END rx_flit[359]
  PIN rx_flit[360]
    DIRECTION OUTPUT ;
    USE SIGNAL ;
    SHAPE ABUTMENT ;
    PORT
      LAYER M4 ;
      RECT 0 646.176 0.192 646.200 ;
    END
  END rx_flit[360]
  PIN rx_flit[361]
    DIRECTION OUTPUT ;
    USE SIGNAL ;
    SHAPE ABUTMENT ;
    PORT
      LAYER M4 ;
      RECT 0 646.224 0.192 646.248 ;
    END
  END rx_flit[361]
  PIN rx_flit[362]
    DIRECTION OUTPUT ;
    USE SIGNAL ;
    SHAPE ABUTMENT ;
    PORT
      LAYER M4 ;
      RECT 0 646.272 0.192 646.296 ;
    END
  END rx_flit[362]
  PIN rx_flit[363]
    DIRECTION OUTPUT ;
    USE SIGNAL ;
    SHAPE ABUTMENT ;
    PORT
      LAYER M4 ;
      RECT 0 646.320 0.192 646.344 ;
    END
  END rx_flit[363]
  PIN rx_flit[364]
    DIRECTION OUTPUT ;
    USE SIGNAL ;
    SHAPE ABUTMENT ;
    PORT
      LAYER M4 ;
      RECT 0 646.368 0.192 646.392 ;
    END
  END rx_flit[364]
  PIN rx_flit[365]
    DIRECTION OUTPUT ;
    USE SIGNAL ;
    SHAPE ABUTMENT ;
    PORT
      LAYER M4 ;
      RECT 0 646.416 0.192 646.440 ;
    END
  END rx_flit[365]
  PIN rx_flit[366]
    DIRECTION OUTPUT ;
    USE SIGNAL ;
    SHAPE ABUTMENT ;
    PORT
      LAYER M4 ;
      RECT 0 646.464 0.192 646.488 ;
    END
  END rx_flit[366]
  PIN rx_flit[367]
    DIRECTION OUTPUT ;
    USE SIGNAL ;
    SHAPE ABUTMENT ;
    PORT
      LAYER M4 ;
      RECT 0 646.512 0.192 646.536 ;
    END
  END rx_flit[367]
  PIN rx_flit[368]
    DIRECTION OUTPUT ;
    USE SIGNAL ;
    SHAPE ABUTMENT ;
    PORT
      LAYER M4 ;
      RECT 0 646.560 0.192 646.584 ;
    END
  END rx_flit[368]
  PIN rx_flit[369]
    DIRECTION OUTPUT ;
    USE SIGNAL ;
    SHAPE ABUTMENT ;
    PORT
      LAYER M4 ;
      RECT 0 646.608 0.192 646.632 ;
    END
  END rx_flit[369]
  PIN rx_flit[370]
    DIRECTION OUTPUT ;
    USE SIGNAL ;
    SHAPE ABUTMENT ;
    PORT
      LAYER M4 ;
      RECT 0 646.656 0.192 646.680 ;
    END
  END rx_flit[370]
  PIN rx_flit[371]
    DIRECTION OUTPUT ;
    USE SIGNAL ;
    SHAPE ABUTMENT ;
    PORT
      LAYER M4 ;
      RECT 0 646.704 0.192 646.728 ;
    END
  END rx_flit[371]
  PIN rx_flit[372]
    DIRECTION OUTPUT ;
    USE SIGNAL ;
    SHAPE ABUTMENT ;
    PORT
      LAYER M4 ;
      RECT 0 646.752 0.192 646.776 ;
    END
  END rx_flit[372]
  PIN rx_flit[373]
    DIRECTION OUTPUT ;
    USE SIGNAL ;
    SHAPE ABUTMENT ;
    PORT
      LAYER M4 ;
      RECT 0 646.800 0.192 646.824 ;
    END
  END rx_flit[373]
  PIN rx_flit[374]
    DIRECTION OUTPUT ;
    USE SIGNAL ;
    SHAPE ABUTMENT ;
    PORT
      LAYER M4 ;
      RECT 0 646.848 0.192 646.872 ;
    END
  END rx_flit[374]
  PIN rx_flit[375]
    DIRECTION OUTPUT ;
    USE SIGNAL ;
    SHAPE ABUTMENT ;
    PORT
      LAYER M4 ;
      RECT 0 646.896 0.192 646.920 ;
    END
  END rx_flit[375]
  PIN rx_flit[376]
    DIRECTION OUTPUT ;
    USE SIGNAL ;
    SHAPE ABUTMENT ;
    PORT
      LAYER M4 ;
      RECT 0 646.944 0.192 646.968 ;
    END
  END rx_flit[376]
  PIN rx_flit[377]
    DIRECTION OUTPUT ;
    USE SIGNAL ;
    SHAPE ABUTMENT ;
    PORT
      LAYER M4 ;
      RECT 0 646.992 0.192 647.016 ;
    END
  END rx_flit[377]
  PIN rx_flit[378]
    DIRECTION OUTPUT ;
    USE SIGNAL ;
    SHAPE ABUTMENT ;
    PORT
      LAYER M4 ;
      RECT 0 647.040 0.192 647.064 ;
    END
  END rx_flit[378]
  PIN rx_flit[379]
    DIRECTION OUTPUT ;
    USE SIGNAL ;
    SHAPE ABUTMENT ;
    PORT
      LAYER M4 ;
      RECT 0 647.088 0.192 647.112 ;
    END
  END rx_flit[379]
  PIN rx_flit[380]
    DIRECTION OUTPUT ;
    USE SIGNAL ;
    SHAPE ABUTMENT ;
    PORT
      LAYER M4 ;
      RECT 0 647.136 0.192 647.160 ;
    END
  END rx_flit[380]
  PIN rx_flit[381]
    DIRECTION OUTPUT ;
    USE SIGNAL ;
    SHAPE ABUTMENT ;
    PORT
      LAYER M4 ;
      RECT 0 647.184 0.192 647.208 ;
    END
  END rx_flit[381]
  PIN rx_flit[382]
    DIRECTION OUTPUT ;
    USE SIGNAL ;
    SHAPE ABUTMENT ;
    PORT
      LAYER M4 ;
      RECT 0 647.232 0.192 647.256 ;
    END
  END rx_flit[382]
  PIN rx_flit[383]
    DIRECTION OUTPUT ;
    USE SIGNAL ;
    SHAPE ABUTMENT ;
    PORT
      LAYER M4 ;
      RECT 0 647.280 0.192 647.304 ;
    END
  END rx_flit[383]
  PIN rx_flit[384]
    DIRECTION OUTPUT ;
    USE SIGNAL ;
    SHAPE ABUTMENT ;
    PORT
      LAYER M4 ;
      RECT 0 647.328 0.192 647.352 ;
    END
  END rx_flit[384]
  PIN rx_flit[385]
    DIRECTION OUTPUT ;
    USE SIGNAL ;
    SHAPE ABUTMENT ;
    PORT
      LAYER M4 ;
      RECT 0 647.376 0.192 647.400 ;
    END
  END rx_flit[385]
  PIN rx_flit[386]
    DIRECTION OUTPUT ;
    USE SIGNAL ;
    SHAPE ABUTMENT ;
    PORT
      LAYER M4 ;
      RECT 0 647.424 0.192 647.448 ;
    END
  END rx_flit[386]
  PIN rx_flit[387]
    DIRECTION OUTPUT ;
    USE SIGNAL ;
    SHAPE ABUTMENT ;
    PORT
      LAYER M4 ;
      RECT 0 647.472 0.192 647.496 ;
    END
  END rx_flit[387]
  PIN rx_flit[388]
    DIRECTION OUTPUT ;
    USE SIGNAL ;
    SHAPE ABUTMENT ;
    PORT
      LAYER M4 ;
      RECT 0 647.520 0.192 647.544 ;
    END
  END rx_flit[388]
  PIN rx_flit[389]
    DIRECTION OUTPUT ;
    USE SIGNAL ;
    SHAPE ABUTMENT ;
    PORT
      LAYER M4 ;
      RECT 0 647.568 0.192 647.592 ;
    END
  END rx_flit[389]
  PIN rx_flit[390]
    DIRECTION OUTPUT ;
    USE SIGNAL ;
    SHAPE ABUTMENT ;
    PORT
      LAYER M4 ;
      RECT 0 647.616 0.192 647.640 ;
    END
  END rx_flit[390]
  PIN rx_flit[391]
    DIRECTION OUTPUT ;
    USE SIGNAL ;
    SHAPE ABUTMENT ;
    PORT
      LAYER M4 ;
      RECT 0 647.664 0.192 647.688 ;
    END
  END rx_flit[391]
  PIN rx_flit[392]
    DIRECTION OUTPUT ;
    USE SIGNAL ;
    SHAPE ABUTMENT ;
    PORT
      LAYER M4 ;
      RECT 0 647.712 0.192 647.736 ;
    END
  END rx_flit[392]
  PIN rx_flit[393]
    DIRECTION OUTPUT ;
    USE SIGNAL ;
    SHAPE ABUTMENT ;
    PORT
      LAYER M4 ;
      RECT 0 647.760 0.192 647.784 ;
    END
  END rx_flit[393]
  PIN rx_flit[394]
    DIRECTION OUTPUT ;
    USE SIGNAL ;
    SHAPE ABUTMENT ;
    PORT
      LAYER M4 ;
      RECT 0 647.808 0.192 647.832 ;
    END
  END rx_flit[394]
  PIN rx_flit[395]
    DIRECTION OUTPUT ;
    USE SIGNAL ;
    SHAPE ABUTMENT ;
    PORT
      LAYER M4 ;
      RECT 0 647.856 0.192 647.880 ;
    END
  END rx_flit[395]
  PIN rx_flit[396]
    DIRECTION OUTPUT ;
    USE SIGNAL ;
    SHAPE ABUTMENT ;
    PORT
      LAYER M4 ;
      RECT 0 647.904 0.192 647.928 ;
    END
  END rx_flit[396]
  PIN rx_flit[397]
    DIRECTION OUTPUT ;
    USE SIGNAL ;
    SHAPE ABUTMENT ;
    PORT
      LAYER M4 ;
      RECT 0 647.952 0.192 647.976 ;
    END
  END rx_flit[397]
  PIN rx_flit[398]
    DIRECTION OUTPUT ;
    USE SIGNAL ;
    SHAPE ABUTMENT ;
    PORT
      LAYER M4 ;
      RECT 0 648.000 0.192 648.024 ;
    END
  END rx_flit[398]
  PIN rx_flit[399]
    DIRECTION OUTPUT ;
    USE SIGNAL ;
    SHAPE ABUTMENT ;
    PORT
      LAYER M4 ;
      RECT 0 648.048 0.192 648.072 ;
    END
  END rx_flit[399]
  PIN rx_flit[400]
    DIRECTION OUTPUT ;
    USE SIGNAL ;
    SHAPE ABUTMENT ;
    PORT
      LAYER M4 ;
      RECT 0 648.096 0.192 648.120 ;
    END
  END rx_flit[400]
  PIN rx_flit[401]
    DIRECTION OUTPUT ;
    USE SIGNAL ;
    SHAPE ABUTMENT ;
    PORT
      LAYER M4 ;
      RECT 0 648.144 0.192 648.168 ;
    END
  END rx_flit[401]
  PIN rx_flit[402]
    DIRECTION OUTPUT ;
    USE SIGNAL ;
    SHAPE ABUTMENT ;
    PORT
      LAYER M4 ;
      RECT 0 648.192 0.192 648.216 ;
    END
  END rx_flit[402]
  PIN rx_flit[403]
    DIRECTION OUTPUT ;
    USE SIGNAL ;
    SHAPE ABUTMENT ;
    PORT
      LAYER M4 ;
      RECT 0 648.240 0.192 648.264 ;
    END
  END rx_flit[403]
  PIN rx_flit[404]
    DIRECTION OUTPUT ;
    USE SIGNAL ;
    SHAPE ABUTMENT ;
    PORT
      LAYER M4 ;
      RECT 0 648.288 0.192 648.312 ;
    END
  END rx_flit[404]
  PIN rx_flit[405]
    DIRECTION OUTPUT ;
    USE SIGNAL ;
    SHAPE ABUTMENT ;
    PORT
      LAYER M4 ;
      RECT 0 648.336 0.192 648.360 ;
    END
  END rx_flit[405]
  PIN rx_flit[406]
    DIRECTION OUTPUT ;
    USE SIGNAL ;
    SHAPE ABUTMENT ;
    PORT
      LAYER M4 ;
      RECT 0 648.384 0.192 648.408 ;
    END
  END rx_flit[406]
  PIN rx_flit[407]
    DIRECTION OUTPUT ;
    USE SIGNAL ;
    SHAPE ABUTMENT ;
    PORT
      LAYER M4 ;
      RECT 0 648.432 0.192 648.456 ;
    END
  END rx_flit[407]
  PIN rx_flit[408]
    DIRECTION OUTPUT ;
    USE SIGNAL ;
    SHAPE ABUTMENT ;
    PORT
      LAYER M4 ;
      RECT 0 648.480 0.192 648.504 ;
    END
  END rx_flit[408]
  PIN rx_flit[409]
    DIRECTION OUTPUT ;
    USE SIGNAL ;
    SHAPE ABUTMENT ;
    PORT
      LAYER M4 ;
      RECT 0 648.528 0.192 648.552 ;
    END
  END rx_flit[409]
  PIN rx_flit[410]
    DIRECTION OUTPUT ;
    USE SIGNAL ;
    SHAPE ABUTMENT ;
    PORT
      LAYER M4 ;
      RECT 0 648.576 0.192 648.600 ;
    END
  END rx_flit[410]
  PIN rx_flit[411]
    DIRECTION OUTPUT ;
    USE SIGNAL ;
    SHAPE ABUTMENT ;
    PORT
      LAYER M4 ;
      RECT 0 648.624 0.192 648.648 ;
    END
  END rx_flit[411]
  PIN rx_flit[412]
    DIRECTION OUTPUT ;
    USE SIGNAL ;
    SHAPE ABUTMENT ;
    PORT
      LAYER M4 ;
      RECT 0 648.672 0.192 648.696 ;
    END
  END rx_flit[412]
  PIN rx_flit[413]
    DIRECTION OUTPUT ;
    USE SIGNAL ;
    SHAPE ABUTMENT ;
    PORT
      LAYER M4 ;
      RECT 0 648.720 0.192 648.744 ;
    END
  END rx_flit[413]
  PIN rx_flit[414]
    DIRECTION OUTPUT ;
    USE SIGNAL ;
    SHAPE ABUTMENT ;
    PORT
      LAYER M4 ;
      RECT 0 648.768 0.192 648.792 ;
    END
  END rx_flit[414]
  PIN rx_flit[415]
    DIRECTION OUTPUT ;
    USE SIGNAL ;
    SHAPE ABUTMENT ;
    PORT
      LAYER M4 ;
      RECT 0 648.816 0.192 648.840 ;
    END
  END rx_flit[415]
  PIN rx_flit[416]
    DIRECTION OUTPUT ;
    USE SIGNAL ;
    SHAPE ABUTMENT ;
    PORT
      LAYER M4 ;
      RECT 0 648.864 0.192 648.888 ;
    END
  END rx_flit[416]
  PIN rx_flit[417]
    DIRECTION OUTPUT ;
    USE SIGNAL ;
    SHAPE ABUTMENT ;
    PORT
      LAYER M4 ;
      RECT 0 648.912 0.192 648.936 ;
    END
  END rx_flit[417]
  PIN rx_flit[418]
    DIRECTION OUTPUT ;
    USE SIGNAL ;
    SHAPE ABUTMENT ;
    PORT
      LAYER M4 ;
      RECT 0 648.960 0.192 648.984 ;
    END
  END rx_flit[418]
  PIN rx_flit[419]
    DIRECTION OUTPUT ;
    USE SIGNAL ;
    SHAPE ABUTMENT ;
    PORT
      LAYER M4 ;
      RECT 0 649.008 0.192 649.032 ;
    END
  END rx_flit[419]
  PIN rx_flit[420]
    DIRECTION OUTPUT ;
    USE SIGNAL ;
    SHAPE ABUTMENT ;
    PORT
      LAYER M4 ;
      RECT 0 649.056 0.192 649.080 ;
    END
  END rx_flit[420]
  PIN rx_flit[421]
    DIRECTION OUTPUT ;
    USE SIGNAL ;
    SHAPE ABUTMENT ;
    PORT
      LAYER M4 ;
      RECT 0 649.104 0.192 649.128 ;
    END
  END rx_flit[421]
  PIN rx_flit[422]
    DIRECTION OUTPUT ;
    USE SIGNAL ;
    SHAPE ABUTMENT ;
    PORT
      LAYER M4 ;
      RECT 0 649.152 0.192 649.176 ;
    END
  END rx_flit[422]
  PIN rx_flit[423]
    DIRECTION OUTPUT ;
    USE SIGNAL ;
    SHAPE ABUTMENT ;
    PORT
      LAYER M4 ;
      RECT 0 649.200 0.192 649.224 ;
    END
  END rx_flit[423]
  PIN rx_flit[424]
    DIRECTION OUTPUT ;
    USE SIGNAL ;
    SHAPE ABUTMENT ;
    PORT
      LAYER M4 ;
      RECT 0 649.248 0.192 649.272 ;
    END
  END rx_flit[424]
  PIN rx_flit[425]
    DIRECTION OUTPUT ;
    USE SIGNAL ;
    SHAPE ABUTMENT ;
    PORT
      LAYER M4 ;
      RECT 0 649.296 0.192 649.320 ;
    END
  END rx_flit[425]
  PIN rx_flit[426]
    DIRECTION OUTPUT ;
    USE SIGNAL ;
    SHAPE ABUTMENT ;
    PORT
      LAYER M4 ;
      RECT 0 649.344 0.192 649.368 ;
    END
  END rx_flit[426]
  PIN rx_flit[427]
    DIRECTION OUTPUT ;
    USE SIGNAL ;
    SHAPE ABUTMENT ;
    PORT
      LAYER M4 ;
      RECT 0 649.392 0.192 649.416 ;
    END
  END rx_flit[427]
  PIN rx_flit[428]
    DIRECTION OUTPUT ;
    USE SIGNAL ;
    SHAPE ABUTMENT ;
    PORT
      LAYER M4 ;
      RECT 0 649.440 0.192 649.464 ;
    END
  END rx_flit[428]
  PIN rx_flit[429]
    DIRECTION OUTPUT ;
    USE SIGNAL ;
    SHAPE ABUTMENT ;
    PORT
      LAYER M4 ;
      RECT 0 649.488 0.192 649.512 ;
    END
  END rx_flit[429]
  PIN rx_flit[430]
    DIRECTION OUTPUT ;
    USE SIGNAL ;
    SHAPE ABUTMENT ;
    PORT
      LAYER M4 ;
      RECT 0 649.536 0.192 649.560 ;
    END
  END rx_flit[430]
  PIN rx_flit[431]
    DIRECTION OUTPUT ;
    USE SIGNAL ;
    SHAPE ABUTMENT ;
    PORT
      LAYER M4 ;
      RECT 0 649.584 0.192 649.608 ;
    END
  END rx_flit[431]
  PIN rx_flit[432]
    DIRECTION OUTPUT ;
    USE SIGNAL ;
    SHAPE ABUTMENT ;
    PORT
      LAYER M4 ;
      RECT 0 649.632 0.192 649.656 ;
    END
  END rx_flit[432]
  PIN rx_flit[433]
    DIRECTION OUTPUT ;
    USE SIGNAL ;
    SHAPE ABUTMENT ;
    PORT
      LAYER M4 ;
      RECT 0 649.680 0.192 649.704 ;
    END
  END rx_flit[433]
  PIN rx_flit[434]
    DIRECTION OUTPUT ;
    USE SIGNAL ;
    SHAPE ABUTMENT ;
    PORT
      LAYER M4 ;
      RECT 0 649.728 0.192 649.752 ;
    END
  END rx_flit[434]
  PIN rx_flit[435]
    DIRECTION OUTPUT ;
    USE SIGNAL ;
    SHAPE ABUTMENT ;
    PORT
      LAYER M4 ;
      RECT 0 649.776 0.192 649.800 ;
    END
  END rx_flit[435]
  PIN rx_flit[436]
    DIRECTION OUTPUT ;
    USE SIGNAL ;
    SHAPE ABUTMENT ;
    PORT
      LAYER M4 ;
      RECT 0 649.824 0.192 649.848 ;
    END
  END rx_flit[436]
  PIN rx_flit[437]
    DIRECTION OUTPUT ;
    USE SIGNAL ;
    SHAPE ABUTMENT ;
    PORT
      LAYER M4 ;
      RECT 0 649.872 0.192 649.896 ;
    END
  END rx_flit[437]
  PIN rx_flit[438]
    DIRECTION OUTPUT ;
    USE SIGNAL ;
    SHAPE ABUTMENT ;
    PORT
      LAYER M4 ;
      RECT 0 649.920 0.192 649.944 ;
    END
  END rx_flit[438]
  PIN rx_flit[439]
    DIRECTION OUTPUT ;
    USE SIGNAL ;
    SHAPE ABUTMENT ;
    PORT
      LAYER M4 ;
      RECT 0 649.968 0.192 649.992 ;
    END
  END rx_flit[439]
  PIN rx_flit[440]
    DIRECTION OUTPUT ;
    USE SIGNAL ;
    SHAPE ABUTMENT ;
    PORT
      LAYER M4 ;
      RECT 0 650.016 0.192 650.040 ;
    END
  END rx_flit[440]
  PIN rx_flit[441]
    DIRECTION OUTPUT ;
    USE SIGNAL ;
    SHAPE ABUTMENT ;
    PORT
      LAYER M4 ;
      RECT 0 650.064 0.192 650.088 ;
    END
  END rx_flit[441]
  PIN rx_flit[442]
    DIRECTION OUTPUT ;
    USE SIGNAL ;
    SHAPE ABUTMENT ;
    PORT
      LAYER M4 ;
      RECT 0 650.112 0.192 650.136 ;
    END
  END rx_flit[442]
  PIN rx_flit[443]
    DIRECTION OUTPUT ;
    USE SIGNAL ;
    SHAPE ABUTMENT ;
    PORT
      LAYER M4 ;
      RECT 0 650.160 0.192 650.184 ;
    END
  END rx_flit[443]
  PIN rx_flit[444]
    DIRECTION OUTPUT ;
    USE SIGNAL ;
    SHAPE ABUTMENT ;
    PORT
      LAYER M4 ;
      RECT 0 650.208 0.192 650.232 ;
    END
  END rx_flit[444]
  PIN rx_flit[445]
    DIRECTION OUTPUT ;
    USE SIGNAL ;
    SHAPE ABUTMENT ;
    PORT
      LAYER M4 ;
      RECT 0 650.256 0.192 650.280 ;
    END
  END rx_flit[445]
  PIN rx_flit[446]
    DIRECTION OUTPUT ;
    USE SIGNAL ;
    SHAPE ABUTMENT ;
    PORT
      LAYER M4 ;
      RECT 0 650.304 0.192 650.328 ;
    END
  END rx_flit[446]
  PIN rx_flit[447]
    DIRECTION OUTPUT ;
    USE SIGNAL ;
    SHAPE ABUTMENT ;
    PORT
      LAYER M4 ;
      RECT 0 650.352 0.192 650.376 ;
    END
  END rx_flit[447]
  PIN rx_flit[448]
    DIRECTION OUTPUT ;
    USE SIGNAL ;
    SHAPE ABUTMENT ;
    PORT
      LAYER M4 ;
      RECT 0 650.400 0.192 650.424 ;
    END
  END rx_flit[448]
  PIN rx_flit[449]
    DIRECTION OUTPUT ;
    USE SIGNAL ;
    SHAPE ABUTMENT ;
    PORT
      LAYER M4 ;
      RECT 0 650.448 0.192 650.472 ;
    END
  END rx_flit[449]
  PIN rx_flit[450]
    DIRECTION OUTPUT ;
    USE SIGNAL ;
    SHAPE ABUTMENT ;
    PORT
      LAYER M4 ;
      RECT 0 650.496 0.192 650.520 ;
    END
  END rx_flit[450]
  PIN rx_flit[451]
    DIRECTION OUTPUT ;
    USE SIGNAL ;
    SHAPE ABUTMENT ;
    PORT
      LAYER M4 ;
      RECT 0 650.544 0.192 650.568 ;
    END
  END rx_flit[451]
  PIN rx_flit[452]
    DIRECTION OUTPUT ;
    USE SIGNAL ;
    SHAPE ABUTMENT ;
    PORT
      LAYER M4 ;
      RECT 0 650.592 0.192 650.616 ;
    END
  END rx_flit[452]
  PIN rx_flit[453]
    DIRECTION OUTPUT ;
    USE SIGNAL ;
    SHAPE ABUTMENT ;
    PORT
      LAYER M4 ;
      RECT 0 650.640 0.192 650.664 ;
    END
  END rx_flit[453]
  PIN rx_flit[454]
    DIRECTION OUTPUT ;
    USE SIGNAL ;
    SHAPE ABUTMENT ;
    PORT
      LAYER M4 ;
      RECT 0 650.688 0.192 650.712 ;
    END
  END rx_flit[454]
  PIN rx_flit[455]
    DIRECTION OUTPUT ;
    USE SIGNAL ;
    SHAPE ABUTMENT ;
    PORT
      LAYER M4 ;
      RECT 0 650.736 0.192 650.760 ;
    END
  END rx_flit[455]
  PIN rx_flit[456]
    DIRECTION OUTPUT ;
    USE SIGNAL ;
    SHAPE ABUTMENT ;
    PORT
      LAYER M4 ;
      RECT 0 650.784 0.192 650.808 ;
    END
  END rx_flit[456]
  PIN rx_flit[457]
    DIRECTION OUTPUT ;
    USE SIGNAL ;
    SHAPE ABUTMENT ;
    PORT
      LAYER M4 ;
      RECT 0 650.832 0.192 650.856 ;
    END
  END rx_flit[457]
  PIN rx_flit[458]
    DIRECTION OUTPUT ;
    USE SIGNAL ;
    SHAPE ABUTMENT ;
    PORT
      LAYER M4 ;
      RECT 0 650.880 0.192 650.904 ;
    END
  END rx_flit[458]
  PIN rx_flit[459]
    DIRECTION OUTPUT ;
    USE SIGNAL ;
    SHAPE ABUTMENT ;
    PORT
      LAYER M4 ;
      RECT 0 650.928 0.192 650.952 ;
    END
  END rx_flit[459]
  PIN rx_flit[460]
    DIRECTION OUTPUT ;
    USE SIGNAL ;
    SHAPE ABUTMENT ;
    PORT
      LAYER M4 ;
      RECT 0 650.976 0.192 651.000 ;
    END
  END rx_flit[460]
  PIN rx_flit[461]
    DIRECTION OUTPUT ;
    USE SIGNAL ;
    SHAPE ABUTMENT ;
    PORT
      LAYER M4 ;
      RECT 0 651.024 0.192 651.048 ;
    END
  END rx_flit[461]
  PIN rx_flit[462]
    DIRECTION OUTPUT ;
    USE SIGNAL ;
    SHAPE ABUTMENT ;
    PORT
      LAYER M4 ;
      RECT 0 651.072 0.192 651.096 ;
    END
  END rx_flit[462]
  PIN rx_flit[463]
    DIRECTION OUTPUT ;
    USE SIGNAL ;
    SHAPE ABUTMENT ;
    PORT
      LAYER M4 ;
      RECT 0 651.120 0.192 651.144 ;
    END
  END rx_flit[463]
  PIN rx_flit[464]
    DIRECTION OUTPUT ;
    USE SIGNAL ;
    SHAPE ABUTMENT ;
    PORT
      LAYER M4 ;
      RECT 0 651.168 0.192 651.192 ;
    END
  END rx_flit[464]
  PIN rx_flit[465]
    DIRECTION OUTPUT ;
    USE SIGNAL ;
    SHAPE ABUTMENT ;
    PORT
      LAYER M4 ;
      RECT 0 651.216 0.192 651.240 ;
    END
  END rx_flit[465]
  PIN rx_flit[466]
    DIRECTION OUTPUT ;
    USE SIGNAL ;
    SHAPE ABUTMENT ;
    PORT
      LAYER M4 ;
      RECT 0 651.264 0.192 651.288 ;
    END
  END rx_flit[466]
  PIN rx_flit[467]
    DIRECTION OUTPUT ;
    USE SIGNAL ;
    SHAPE ABUTMENT ;
    PORT
      LAYER M4 ;
      RECT 0 651.312 0.192 651.336 ;
    END
  END rx_flit[467]
  PIN rx_flit[468]
    DIRECTION OUTPUT ;
    USE SIGNAL ;
    SHAPE ABUTMENT ;
    PORT
      LAYER M4 ;
      RECT 0 651.360 0.192 651.384 ;
    END
  END rx_flit[468]
  PIN rx_flit[469]
    DIRECTION OUTPUT ;
    USE SIGNAL ;
    SHAPE ABUTMENT ;
    PORT
      LAYER M4 ;
      RECT 0 651.408 0.192 651.432 ;
    END
  END rx_flit[469]
  PIN rx_flit[470]
    DIRECTION OUTPUT ;
    USE SIGNAL ;
    SHAPE ABUTMENT ;
    PORT
      LAYER M4 ;
      RECT 0 651.456 0.192 651.480 ;
    END
  END rx_flit[470]
  PIN rx_flit[471]
    DIRECTION OUTPUT ;
    USE SIGNAL ;
    SHAPE ABUTMENT ;
    PORT
      LAYER M4 ;
      RECT 0 651.504 0.192 651.528 ;
    END
  END rx_flit[471]
  PIN rx_flit[472]
    DIRECTION OUTPUT ;
    USE SIGNAL ;
    SHAPE ABUTMENT ;
    PORT
      LAYER M4 ;
      RECT 0 651.552 0.192 651.576 ;
    END
  END rx_flit[472]
  PIN rx_flit[473]
    DIRECTION OUTPUT ;
    USE SIGNAL ;
    SHAPE ABUTMENT ;
    PORT
      LAYER M4 ;
      RECT 0 651.600 0.192 651.624 ;
    END
  END rx_flit[473]
  PIN rx_flit[474]
    DIRECTION OUTPUT ;
    USE SIGNAL ;
    SHAPE ABUTMENT ;
    PORT
      LAYER M4 ;
      RECT 0 651.648 0.192 651.672 ;
    END
  END rx_flit[474]
  PIN rx_flit[475]
    DIRECTION OUTPUT ;
    USE SIGNAL ;
    SHAPE ABUTMENT ;
    PORT
      LAYER M4 ;
      RECT 0 651.696 0.192 651.720 ;
    END
  END rx_flit[475]
  PIN rx_flit[476]
    DIRECTION OUTPUT ;
    USE SIGNAL ;
    SHAPE ABUTMENT ;
    PORT
      LAYER M4 ;
      RECT 0 651.744 0.192 651.768 ;
    END
  END rx_flit[476]
  PIN rx_flit[477]
    DIRECTION OUTPUT ;
    USE SIGNAL ;
    SHAPE ABUTMENT ;
    PORT
      LAYER M4 ;
      RECT 0 651.792 0.192 651.816 ;
    END
  END rx_flit[477]
  PIN rx_flit[478]
    DIRECTION OUTPUT ;
    USE SIGNAL ;
    SHAPE ABUTMENT ;
    PORT
      LAYER M4 ;
      RECT 0 651.840 0.192 651.864 ;
    END
  END rx_flit[478]
  PIN rx_flit[479]
    DIRECTION OUTPUT ;
    USE SIGNAL ;
    SHAPE ABUTMENT ;
    PORT
      LAYER M4 ;
      RECT 0 651.888 0.192 651.912 ;
    END
  END rx_flit[479]
  PIN rx_flit[480]
    DIRECTION OUTPUT ;
    USE SIGNAL ;
    SHAPE ABUTMENT ;
    PORT
      LAYER M4 ;
      RECT 0 651.936 0.192 651.960 ;
    END
  END rx_flit[480]
  PIN rx_flit[481]
    DIRECTION OUTPUT ;
    USE SIGNAL ;
    SHAPE ABUTMENT ;
    PORT
      LAYER M4 ;
      RECT 0 651.984 0.192 652.008 ;
    END
  END rx_flit[481]
  PIN rx_flit[482]
    DIRECTION OUTPUT ;
    USE SIGNAL ;
    SHAPE ABUTMENT ;
    PORT
      LAYER M4 ;
      RECT 0 652.032 0.192 652.056 ;
    END
  END rx_flit[482]
  PIN rx_flit[483]
    DIRECTION OUTPUT ;
    USE SIGNAL ;
    SHAPE ABUTMENT ;
    PORT
      LAYER M4 ;
      RECT 0 652.080 0.192 652.104 ;
    END
  END rx_flit[483]
  PIN rx_flit[484]
    DIRECTION OUTPUT ;
    USE SIGNAL ;
    SHAPE ABUTMENT ;
    PORT
      LAYER M4 ;
      RECT 0 652.128 0.192 652.152 ;
    END
  END rx_flit[484]
  PIN rx_flit[485]
    DIRECTION OUTPUT ;
    USE SIGNAL ;
    SHAPE ABUTMENT ;
    PORT
      LAYER M4 ;
      RECT 0 652.176 0.192 652.200 ;
    END
  END rx_flit[485]
  PIN rx_flit[486]
    DIRECTION OUTPUT ;
    USE SIGNAL ;
    SHAPE ABUTMENT ;
    PORT
      LAYER M4 ;
      RECT 0 652.224 0.192 652.248 ;
    END
  END rx_flit[486]
  PIN rx_flit[487]
    DIRECTION OUTPUT ;
    USE SIGNAL ;
    SHAPE ABUTMENT ;
    PORT
      LAYER M4 ;
      RECT 0 652.272 0.192 652.296 ;
    END
  END rx_flit[487]
  PIN rx_flit[488]
    DIRECTION OUTPUT ;
    USE SIGNAL ;
    SHAPE ABUTMENT ;
    PORT
      LAYER M4 ;
      RECT 0 652.320 0.192 652.344 ;
    END
  END rx_flit[488]
  PIN rx_flit[489]
    DIRECTION OUTPUT ;
    USE SIGNAL ;
    SHAPE ABUTMENT ;
    PORT
      LAYER M4 ;
      RECT 0 652.368 0.192 652.392 ;
    END
  END rx_flit[489]
  PIN rx_flit[490]
    DIRECTION OUTPUT ;
    USE SIGNAL ;
    SHAPE ABUTMENT ;
    PORT
      LAYER M4 ;
      RECT 0 652.416 0.192 652.440 ;
    END
  END rx_flit[490]
  PIN rx_flit[491]
    DIRECTION OUTPUT ;
    USE SIGNAL ;
    SHAPE ABUTMENT ;
    PORT
      LAYER M4 ;
      RECT 0 652.464 0.192 652.488 ;
    END
  END rx_flit[491]
  PIN rx_flit[492]
    DIRECTION OUTPUT ;
    USE SIGNAL ;
    SHAPE ABUTMENT ;
    PORT
      LAYER M4 ;
      RECT 0 652.512 0.192 652.536 ;
    END
  END rx_flit[492]
  PIN rx_flit[493]
    DIRECTION OUTPUT ;
    USE SIGNAL ;
    SHAPE ABUTMENT ;
    PORT
      LAYER M4 ;
      RECT 0 652.560 0.192 652.584 ;
    END
  END rx_flit[493]
  PIN rx_flit[494]
    DIRECTION OUTPUT ;
    USE SIGNAL ;
    SHAPE ABUTMENT ;
    PORT
      LAYER M4 ;
      RECT 0 652.608 0.192 652.632 ;
    END
  END rx_flit[494]
  PIN rx_flit[495]
    DIRECTION OUTPUT ;
    USE SIGNAL ;
    SHAPE ABUTMENT ;
    PORT
      LAYER M4 ;
      RECT 0 652.656 0.192 652.680 ;
    END
  END rx_flit[495]
  PIN rx_flit[496]
    DIRECTION OUTPUT ;
    USE SIGNAL ;
    SHAPE ABUTMENT ;
    PORT
      LAYER M4 ;
      RECT 0 652.704 0.192 652.728 ;
    END
  END rx_flit[496]
  PIN rx_flit[497]
    DIRECTION OUTPUT ;
    USE SIGNAL ;
    SHAPE ABUTMENT ;
    PORT
      LAYER M4 ;
      RECT 0 652.752 0.192 652.776 ;
    END
  END rx_flit[497]
  PIN rx_flit[498]
    DIRECTION OUTPUT ;
    USE SIGNAL ;
    SHAPE ABUTMENT ;
    PORT
      LAYER M4 ;
      RECT 0 652.800 0.192 652.824 ;
    END
  END rx_flit[498]
  PIN rx_flit[499]
    DIRECTION OUTPUT ;
    USE SIGNAL ;
    SHAPE ABUTMENT ;
    PORT
      LAYER M4 ;
      RECT 0 652.848 0.192 652.872 ;
    END
  END rx_flit[499]
  PIN rx_flit[500]
    DIRECTION OUTPUT ;
    USE SIGNAL ;
    SHAPE ABUTMENT ;
    PORT
      LAYER M4 ;
      RECT 0 652.896 0.192 652.920 ;
    END
  END rx_flit[500]
  PIN rx_flit[501]
    DIRECTION OUTPUT ;
    USE SIGNAL ;
    SHAPE ABUTMENT ;
    PORT
      LAYER M4 ;
      RECT 0 652.944 0.192 652.968 ;
    END
  END rx_flit[501]
  PIN rx_flit[502]
    DIRECTION OUTPUT ;
    USE SIGNAL ;
    SHAPE ABUTMENT ;
    PORT
      LAYER M4 ;
      RECT 0 652.992 0.192 653.016 ;
    END
  END rx_flit[502]
  PIN rx_flit[503]
    DIRECTION OUTPUT ;
    USE SIGNAL ;
    SHAPE ABUTMENT ;
    PORT
      LAYER M4 ;
      RECT 0 653.040 0.192 653.064 ;
    END
  END rx_flit[503]
  PIN rx_flit[504]
    DIRECTION OUTPUT ;
    USE SIGNAL ;
    SHAPE ABUTMENT ;
    PORT
      LAYER M4 ;
      RECT 0 653.088 0.192 653.112 ;
    END
  END rx_flit[504]
  PIN rx_flit[505]
    DIRECTION OUTPUT ;
    USE SIGNAL ;
    SHAPE ABUTMENT ;
    PORT
      LAYER M4 ;
      RECT 0 653.136 0.192 653.160 ;
    END
  END rx_flit[505]
  PIN rx_flit[506]
    DIRECTION OUTPUT ;
    USE SIGNAL ;
    SHAPE ABUTMENT ;
    PORT
      LAYER M4 ;
      RECT 0 653.184 0.192 653.208 ;
    END
  END rx_flit[506]
  PIN rx_flit[507]
    DIRECTION OUTPUT ;
    USE SIGNAL ;
    SHAPE ABUTMENT ;
    PORT
      LAYER M4 ;
      RECT 0 653.232 0.192 653.256 ;
    END
  END rx_flit[507]
  PIN rx_flit[508]
    DIRECTION OUTPUT ;
    USE SIGNAL ;
    SHAPE ABUTMENT ;
    PORT
      LAYER M4 ;
      RECT 0 653.280 0.192 653.304 ;
    END
  END rx_flit[508]
  PIN rx_flit[509]
    DIRECTION OUTPUT ;
    USE SIGNAL ;
    SHAPE ABUTMENT ;
    PORT
      LAYER M4 ;
      RECT 0 653.328 0.192 653.352 ;
    END
  END rx_flit[509]
  PIN rx_flit[510]
    DIRECTION OUTPUT ;
    USE SIGNAL ;
    SHAPE ABUTMENT ;
    PORT
      LAYER M4 ;
      RECT 0 653.376 0.192 653.400 ;
    END
  END rx_flit[510]
  PIN rx_flit[511]
    DIRECTION OUTPUT ;
    USE SIGNAL ;
    SHAPE ABUTMENT ;
    PORT
      LAYER M4 ;
      RECT 0 653.424 0.192 653.448 ;
    END
  END rx_flit[511]
  PIN rx_flit[512]
    DIRECTION OUTPUT ;
    USE SIGNAL ;
    SHAPE ABUTMENT ;
    PORT
      LAYER M4 ;
      RECT 0 653.472 0.192 653.496 ;
    END
  END rx_flit[512]
  PIN rx_flit[513]
    DIRECTION OUTPUT ;
    USE SIGNAL ;
    SHAPE ABUTMENT ;
    PORT
      LAYER M4 ;
      RECT 0 653.520 0.192 653.544 ;
    END
  END rx_flit[513]
  PIN rx_flit[514]
    DIRECTION OUTPUT ;
    USE SIGNAL ;
    SHAPE ABUTMENT ;
    PORT
      LAYER M4 ;
      RECT 0 653.568 0.192 653.592 ;
    END
  END rx_flit[514]
  PIN rx_flit[515]
    DIRECTION OUTPUT ;
    USE SIGNAL ;
    SHAPE ABUTMENT ;
    PORT
      LAYER M4 ;
      RECT 0 653.616 0.192 653.640 ;
    END
  END rx_flit[515]
  PIN rx_flit[516]
    DIRECTION OUTPUT ;
    USE SIGNAL ;
    SHAPE ABUTMENT ;
    PORT
      LAYER M4 ;
      RECT 0 653.664 0.192 653.688 ;
    END
  END rx_flit[516]
  PIN rx_flit[517]
    DIRECTION OUTPUT ;
    USE SIGNAL ;
    SHAPE ABUTMENT ;
    PORT
      LAYER M4 ;
      RECT 0 653.712 0.192 653.736 ;
    END
  END rx_flit[517]
  PIN rx_flit[518]
    DIRECTION OUTPUT ;
    USE SIGNAL ;
    SHAPE ABUTMENT ;
    PORT
      LAYER M4 ;
      RECT 0 653.760 0.192 653.784 ;
    END
  END rx_flit[518]
  PIN rx_flit[519]
    DIRECTION OUTPUT ;
    USE SIGNAL ;
    SHAPE ABUTMENT ;
    PORT
      LAYER M4 ;
      RECT 0 653.808 0.192 653.832 ;
    END
  END rx_flit[519]
  PIN rx_flit[520]
    DIRECTION OUTPUT ;
    USE SIGNAL ;
    SHAPE ABUTMENT ;
    PORT
      LAYER M4 ;
      RECT 0 653.856 0.192 653.880 ;
    END
  END rx_flit[520]
  PIN rx_flit[521]
    DIRECTION OUTPUT ;
    USE SIGNAL ;
    SHAPE ABUTMENT ;
    PORT
      LAYER M4 ;
      RECT 0 653.904 0.192 653.928 ;
    END
  END rx_flit[521]
  PIN rx_flit[522]
    DIRECTION OUTPUT ;
    USE SIGNAL ;
    SHAPE ABUTMENT ;
    PORT
      LAYER M4 ;
      RECT 0 653.952 0.192 653.976 ;
    END
  END rx_flit[522]
  PIN rx_flit[523]
    DIRECTION OUTPUT ;
    USE SIGNAL ;
    SHAPE ABUTMENT ;
    PORT
      LAYER M4 ;
      RECT 0 654.000 0.192 654.024 ;
    END
  END rx_flit[523]
  PIN rx_flit[524]
    DIRECTION OUTPUT ;
    USE SIGNAL ;
    SHAPE ABUTMENT ;
    PORT
      LAYER M4 ;
      RECT 0 654.048 0.192 654.072 ;
    END
  END rx_flit[524]
  PIN rx_flit[525]
    DIRECTION OUTPUT ;
    USE SIGNAL ;
    SHAPE ABUTMENT ;
    PORT
      LAYER M4 ;
      RECT 0 654.096 0.192 654.120 ;
    END
  END rx_flit[525]
  PIN rx_flit[526]
    DIRECTION OUTPUT ;
    USE SIGNAL ;
    SHAPE ABUTMENT ;
    PORT
      LAYER M4 ;
      RECT 0 654.144 0.192 654.168 ;
    END
  END rx_flit[526]
  PIN rx_flit[527]
    DIRECTION OUTPUT ;
    USE SIGNAL ;
    SHAPE ABUTMENT ;
    PORT
      LAYER M4 ;
      RECT 0 654.192 0.192 654.216 ;
    END
  END rx_flit[527]
  PIN rx_flit[528]
    DIRECTION OUTPUT ;
    USE SIGNAL ;
    SHAPE ABUTMENT ;
    PORT
      LAYER M4 ;
      RECT 0 654.240 0.192 654.264 ;
    END
  END rx_flit[528]
  PIN rx_flit[529]
    DIRECTION OUTPUT ;
    USE SIGNAL ;
    SHAPE ABUTMENT ;
    PORT
      LAYER M4 ;
      RECT 0 654.288 0.192 654.312 ;
    END
  END rx_flit[529]
  PIN rx_flit[530]
    DIRECTION OUTPUT ;
    USE SIGNAL ;
    SHAPE ABUTMENT ;
    PORT
      LAYER M4 ;
      RECT 0 654.336 0.192 654.360 ;
    END
  END rx_flit[530]
  PIN rx_flit[531]
    DIRECTION OUTPUT ;
    USE SIGNAL ;
    SHAPE ABUTMENT ;
    PORT
      LAYER M4 ;
      RECT 0 654.384 0.192 654.408 ;
    END
  END rx_flit[531]
  PIN rx_flit[532]
    DIRECTION OUTPUT ;
    USE SIGNAL ;
    SHAPE ABUTMENT ;
    PORT
      LAYER M4 ;
      RECT 0 654.432 0.192 654.456 ;
    END
  END rx_flit[532]
  PIN rx_flit[533]
    DIRECTION OUTPUT ;
    USE SIGNAL ;
    SHAPE ABUTMENT ;
    PORT
      LAYER M4 ;
      RECT 0 654.480 0.192 654.504 ;
    END
  END rx_flit[533]
  PIN rx_flit[534]
    DIRECTION OUTPUT ;
    USE SIGNAL ;
    SHAPE ABUTMENT ;
    PORT
      LAYER M4 ;
      RECT 0 654.528 0.192 654.552 ;
    END
  END rx_flit[534]
  PIN rx_flit[535]
    DIRECTION OUTPUT ;
    USE SIGNAL ;
    SHAPE ABUTMENT ;
    PORT
      LAYER M4 ;
      RECT 0 654.576 0.192 654.600 ;
    END
  END rx_flit[535]
  PIN rx_flit[536]
    DIRECTION OUTPUT ;
    USE SIGNAL ;
    SHAPE ABUTMENT ;
    PORT
      LAYER M4 ;
      RECT 0 654.624 0.192 654.648 ;
    END
  END rx_flit[536]
  PIN rx_flit[537]
    DIRECTION OUTPUT ;
    USE SIGNAL ;
    SHAPE ABUTMENT ;
    PORT
      LAYER M4 ;
      RECT 0 654.672 0.192 654.696 ;
    END
  END rx_flit[537]
  PIN rx_flit[538]
    DIRECTION OUTPUT ;
    USE SIGNAL ;
    SHAPE ABUTMENT ;
    PORT
      LAYER M4 ;
      RECT 0 654.720 0.192 654.744 ;
    END
  END rx_flit[538]
  PIN rx_flit[539]
    DIRECTION OUTPUT ;
    USE SIGNAL ;
    SHAPE ABUTMENT ;
    PORT
      LAYER M4 ;
      RECT 0 654.768 0.192 654.792 ;
    END
  END rx_flit[539]
  PIN rx_flit[540]
    DIRECTION OUTPUT ;
    USE SIGNAL ;
    SHAPE ABUTMENT ;
    PORT
      LAYER M4 ;
      RECT 0 654.816 0.192 654.840 ;
    END
  END rx_flit[540]
  PIN rx_flit[541]
    DIRECTION OUTPUT ;
    USE SIGNAL ;
    SHAPE ABUTMENT ;
    PORT
      LAYER M4 ;
      RECT 0 654.864 0.192 654.888 ;
    END
  END rx_flit[541]
  PIN rx_flit[542]
    DIRECTION OUTPUT ;
    USE SIGNAL ;
    SHAPE ABUTMENT ;
    PORT
      LAYER M4 ;
      RECT 0 654.912 0.192 654.936 ;
    END
  END rx_flit[542]
  PIN rx_flit[543]
    DIRECTION OUTPUT ;
    USE SIGNAL ;
    SHAPE ABUTMENT ;
    PORT
      LAYER M4 ;
      RECT 0 654.960 0.192 654.984 ;
    END
  END rx_flit[543]
  PIN rx_flit[544]
    DIRECTION OUTPUT ;
    USE SIGNAL ;
    SHAPE ABUTMENT ;
    PORT
      LAYER M4 ;
      RECT 0 655.008 0.192 655.032 ;
    END
  END rx_flit[544]
  PIN rx_flit[545]
    DIRECTION OUTPUT ;
    USE SIGNAL ;
    SHAPE ABUTMENT ;
    PORT
      LAYER M4 ;
      RECT 0 655.056 0.192 655.080 ;
    END
  END rx_flit[545]
  PIN rx_flit[546]
    DIRECTION OUTPUT ;
    USE SIGNAL ;
    SHAPE ABUTMENT ;
    PORT
      LAYER M4 ;
      RECT 0 655.104 0.192 655.128 ;
    END
  END rx_flit[546]
  PIN rx_flit[547]
    DIRECTION OUTPUT ;
    USE SIGNAL ;
    SHAPE ABUTMENT ;
    PORT
      LAYER M4 ;
      RECT 0 655.152 0.192 655.176 ;
    END
  END rx_flit[547]
  PIN rx_flit[548]
    DIRECTION OUTPUT ;
    USE SIGNAL ;
    SHAPE ABUTMENT ;
    PORT
      LAYER M4 ;
      RECT 0 655.200 0.192 655.224 ;
    END
  END rx_flit[548]
  PIN rx_flit[549]
    DIRECTION OUTPUT ;
    USE SIGNAL ;
    SHAPE ABUTMENT ;
    PORT
      LAYER M4 ;
      RECT 0 655.248 0.192 655.272 ;
    END
  END rx_flit[549]
  PIN rx_flit[550]
    DIRECTION OUTPUT ;
    USE SIGNAL ;
    SHAPE ABUTMENT ;
    PORT
      LAYER M4 ;
      RECT 0 655.296 0.192 655.320 ;
    END
  END rx_flit[550]
  PIN rx_flit[551]
    DIRECTION OUTPUT ;
    USE SIGNAL ;
    SHAPE ABUTMENT ;
    PORT
      LAYER M4 ;
      RECT 0 655.344 0.192 655.368 ;
    END
  END rx_flit[551]
  PIN rx_flit[552]
    DIRECTION OUTPUT ;
    USE SIGNAL ;
    SHAPE ABUTMENT ;
    PORT
      LAYER M4 ;
      RECT 0 655.392 0.192 655.416 ;
    END
  END rx_flit[552]
  PIN rx_flit[553]
    DIRECTION OUTPUT ;
    USE SIGNAL ;
    SHAPE ABUTMENT ;
    PORT
      LAYER M4 ;
      RECT 0 655.440 0.192 655.464 ;
    END
  END rx_flit[553]
  PIN rx_flit[554]
    DIRECTION OUTPUT ;
    USE SIGNAL ;
    SHAPE ABUTMENT ;
    PORT
      LAYER M4 ;
      RECT 0 655.488 0.192 655.512 ;
    END
  END rx_flit[554]
  PIN rx_flit[555]
    DIRECTION OUTPUT ;
    USE SIGNAL ;
    SHAPE ABUTMENT ;
    PORT
      LAYER M4 ;
      RECT 0 655.536 0.192 655.560 ;
    END
  END rx_flit[555]
  PIN rx_flit[556]
    DIRECTION OUTPUT ;
    USE SIGNAL ;
    SHAPE ABUTMENT ;
    PORT
      LAYER M4 ;
      RECT 0 655.584 0.192 655.608 ;
    END
  END rx_flit[556]
  PIN rx_flit[557]
    DIRECTION OUTPUT ;
    USE SIGNAL ;
    SHAPE ABUTMENT ;
    PORT
      LAYER M4 ;
      RECT 0 655.632 0.192 655.656 ;
    END
  END rx_flit[557]
  PIN rx_flit[558]
    DIRECTION OUTPUT ;
    USE SIGNAL ;
    SHAPE ABUTMENT ;
    PORT
      LAYER M4 ;
      RECT 0 655.680 0.192 655.704 ;
    END
  END rx_flit[558]
  PIN rx_flit[559]
    DIRECTION OUTPUT ;
    USE SIGNAL ;
    SHAPE ABUTMENT ;
    PORT
      LAYER M4 ;
      RECT 0 655.728 0.192 655.752 ;
    END
  END rx_flit[559]
  PIN rx_flit[560]
    DIRECTION OUTPUT ;
    USE SIGNAL ;
    SHAPE ABUTMENT ;
    PORT
      LAYER M4 ;
      RECT 0 655.776 0.192 655.800 ;
    END
  END rx_flit[560]
  PIN rx_flit[561]
    DIRECTION OUTPUT ;
    USE SIGNAL ;
    SHAPE ABUTMENT ;
    PORT
      LAYER M4 ;
      RECT 0 655.824 0.192 655.848 ;
    END
  END rx_flit[561]
  PIN rx_flit[562]
    DIRECTION OUTPUT ;
    USE SIGNAL ;
    SHAPE ABUTMENT ;
    PORT
      LAYER M4 ;
      RECT 0 655.872 0.192 655.896 ;
    END
  END rx_flit[562]
  PIN rx_flit[563]
    DIRECTION OUTPUT ;
    USE SIGNAL ;
    SHAPE ABUTMENT ;
    PORT
      LAYER M4 ;
      RECT 0 655.920 0.192 655.944 ;
    END
  END rx_flit[563]
  PIN rx_flit[564]
    DIRECTION OUTPUT ;
    USE SIGNAL ;
    SHAPE ABUTMENT ;
    PORT
      LAYER M4 ;
      RECT 0 655.968 0.192 655.992 ;
    END
  END rx_flit[564]
  PIN rx_flit[565]
    DIRECTION OUTPUT ;
    USE SIGNAL ;
    SHAPE ABUTMENT ;
    PORT
      LAYER M4 ;
      RECT 0 656.016 0.192 656.040 ;
    END
  END rx_flit[565]
  PIN rx_flit[566]
    DIRECTION OUTPUT ;
    USE SIGNAL ;
    SHAPE ABUTMENT ;
    PORT
      LAYER M4 ;
      RECT 0 656.064 0.192 656.088 ;
    END
  END rx_flit[566]
  PIN rx_flit[567]
    DIRECTION OUTPUT ;
    USE SIGNAL ;
    SHAPE ABUTMENT ;
    PORT
      LAYER M4 ;
      RECT 0 656.112 0.192 656.136 ;
    END
  END rx_flit[567]
  PIN rx_flit[568]
    DIRECTION OUTPUT ;
    USE SIGNAL ;
    SHAPE ABUTMENT ;
    PORT
      LAYER M4 ;
      RECT 0 656.160 0.192 656.184 ;
    END
  END rx_flit[568]
  PIN rx_flit[569]
    DIRECTION OUTPUT ;
    USE SIGNAL ;
    SHAPE ABUTMENT ;
    PORT
      LAYER M4 ;
      RECT 0 656.208 0.192 656.232 ;
    END
  END rx_flit[569]
  PIN rx_flit[570]
    DIRECTION OUTPUT ;
    USE SIGNAL ;
    SHAPE ABUTMENT ;
    PORT
      LAYER M4 ;
      RECT 0 656.256 0.192 656.280 ;
    END
  END rx_flit[570]
  PIN rx_flit[571]
    DIRECTION OUTPUT ;
    USE SIGNAL ;
    SHAPE ABUTMENT ;
    PORT
      LAYER M4 ;
      RECT 0 656.304 0.192 656.328 ;
    END
  END rx_flit[571]
  PIN rx_flit[572]
    DIRECTION OUTPUT ;
    USE SIGNAL ;
    SHAPE ABUTMENT ;
    PORT
      LAYER M4 ;
      RECT 0 656.352 0.192 656.376 ;
    END
  END rx_flit[572]
  PIN rx_flit[573]
    DIRECTION OUTPUT ;
    USE SIGNAL ;
    SHAPE ABUTMENT ;
    PORT
      LAYER M4 ;
      RECT 0 656.400 0.192 656.424 ;
    END
  END rx_flit[573]
  PIN rx_flit[574]
    DIRECTION OUTPUT ;
    USE SIGNAL ;
    SHAPE ABUTMENT ;
    PORT
      LAYER M4 ;
      RECT 0 656.448 0.192 656.472 ;
    END
  END rx_flit[574]
  PIN rx_flit[575]
    DIRECTION OUTPUT ;
    USE SIGNAL ;
    SHAPE ABUTMENT ;
    PORT
      LAYER M4 ;
      RECT 0 656.496 0.192 656.520 ;
    END
  END rx_flit[575]
  PIN rx_flit[576]
    DIRECTION OUTPUT ;
    USE SIGNAL ;
    SHAPE ABUTMENT ;
    PORT
      LAYER M4 ;
      RECT 0 656.544 0.192 656.568 ;
    END
  END rx_flit[576]
  PIN rx_flit[577]
    DIRECTION OUTPUT ;
    USE SIGNAL ;
    SHAPE ABUTMENT ;
    PORT
      LAYER M4 ;
      RECT 0 656.592 0.192 656.616 ;
    END
  END rx_flit[577]
  PIN rx_flit[578]
    DIRECTION OUTPUT ;
    USE SIGNAL ;
    SHAPE ABUTMENT ;
    PORT
      LAYER M4 ;
      RECT 0 656.640 0.192 656.664 ;
    END
  END rx_flit[578]
  PIN rx_flit[579]
    DIRECTION OUTPUT ;
    USE SIGNAL ;
    SHAPE ABUTMENT ;
    PORT
      LAYER M4 ;
      RECT 0 656.688 0.192 656.712 ;
    END
  END rx_flit[579]
  PIN rx_flit[580]
    DIRECTION OUTPUT ;
    USE SIGNAL ;
    SHAPE ABUTMENT ;
    PORT
      LAYER M4 ;
      RECT 0 656.736 0.192 656.760 ;
    END
  END rx_flit[580]
  PIN rx_flit[581]
    DIRECTION OUTPUT ;
    USE SIGNAL ;
    SHAPE ABUTMENT ;
    PORT
      LAYER M4 ;
      RECT 0 656.784 0.192 656.808 ;
    END
  END rx_flit[581]
  PIN rx_flit[582]
    DIRECTION OUTPUT ;
    USE SIGNAL ;
    SHAPE ABUTMENT ;
    PORT
      LAYER M4 ;
      RECT 0 656.832 0.192 656.856 ;
    END
  END rx_flit[582]
  PIN rx_flit[583]
    DIRECTION OUTPUT ;
    USE SIGNAL ;
    SHAPE ABUTMENT ;
    PORT
      LAYER M4 ;
      RECT 0 656.880 0.192 656.904 ;
    END
  END rx_flit[583]
  PIN rx_flit[584]
    DIRECTION OUTPUT ;
    USE SIGNAL ;
    SHAPE ABUTMENT ;
    PORT
      LAYER M4 ;
      RECT 0 656.928 0.192 656.952 ;
    END
  END rx_flit[584]
  PIN rx_flit[585]
    DIRECTION OUTPUT ;
    USE SIGNAL ;
    SHAPE ABUTMENT ;
    PORT
      LAYER M4 ;
      RECT 0 656.976 0.192 657.000 ;
    END
  END rx_flit[585]
  PIN rx_flit[586]
    DIRECTION OUTPUT ;
    USE SIGNAL ;
    SHAPE ABUTMENT ;
    PORT
      LAYER M4 ;
      RECT 0 657.024 0.192 657.048 ;
    END
  END rx_flit[586]
  PIN rx_flit[587]
    DIRECTION OUTPUT ;
    USE SIGNAL ;
    SHAPE ABUTMENT ;
    PORT
      LAYER M4 ;
      RECT 0 657.072 0.192 657.096 ;
    END
  END rx_flit[587]
  PIN rx_flit[588]
    DIRECTION OUTPUT ;
    USE SIGNAL ;
    SHAPE ABUTMENT ;
    PORT
      LAYER M4 ;
      RECT 0 657.120 0.192 657.144 ;
    END
  END rx_flit[588]
  PIN rx_flit[589]
    DIRECTION OUTPUT ;
    USE SIGNAL ;
    SHAPE ABUTMENT ;
    PORT
      LAYER M4 ;
      RECT 0 657.168 0.192 657.192 ;
    END
  END rx_flit[589]
  PIN rx_flit[590]
    DIRECTION OUTPUT ;
    USE SIGNAL ;
    SHAPE ABUTMENT ;
    PORT
      LAYER M4 ;
      RECT 0 657.216 0.192 657.240 ;
    END
  END rx_flit[590]
  PIN rx_flit[591]
    DIRECTION OUTPUT ;
    USE SIGNAL ;
    SHAPE ABUTMENT ;
    PORT
      LAYER M4 ;
      RECT 0 657.264 0.192 657.288 ;
    END
  END rx_flit[591]
  PIN rx_flit[592]
    DIRECTION OUTPUT ;
    USE SIGNAL ;
    SHAPE ABUTMENT ;
    PORT
      LAYER M4 ;
      RECT 0 657.312 0.192 657.336 ;
    END
  END rx_flit[592]
  PIN rx_flit[593]
    DIRECTION OUTPUT ;
    USE SIGNAL ;
    SHAPE ABUTMENT ;
    PORT
      LAYER M4 ;
      RECT 0 657.360 0.192 657.384 ;
    END
  END rx_flit[593]
  PIN rx_flit[594]
    DIRECTION OUTPUT ;
    USE SIGNAL ;
    SHAPE ABUTMENT ;
    PORT
      LAYER M4 ;
      RECT 0 657.408 0.192 657.432 ;
    END
  END rx_flit[594]
  PIN rx_flit[595]
    DIRECTION OUTPUT ;
    USE SIGNAL ;
    SHAPE ABUTMENT ;
    PORT
      LAYER M4 ;
      RECT 0 657.456 0.192 657.480 ;
    END
  END rx_flit[595]
  PIN rx_flit[596]
    DIRECTION OUTPUT ;
    USE SIGNAL ;
    SHAPE ABUTMENT ;
    PORT
      LAYER M4 ;
      RECT 0 657.504 0.192 657.528 ;
    END
  END rx_flit[596]
  PIN VDD
    DIRECTION INOUT ;
    USE POWER ;
    PORT
      LAYER M4 ;
      RECT 0.500 1.000 2319.556 1.288 ;
      RECT 0.500 3.400 2319.556 3.688 ;
      RECT 0.500 5.800 2319.556 6.088 ;
      RECT 0.500 8.200 2319.556 8.488 ;
      RECT 0.500 10.600 2319.556 10.888 ;
      RECT 0.500 13.000 2319.556 13.288 ;
      RECT 0.500 15.400 2319.556 15.688 ;
      RECT 0.500 17.800 2319.556 18.088 ;
      RECT 0.500 20.200 2319.556 20.488 ;
      RECT 0.500 22.600 2319.556 22.888 ;
      RECT 0.500 25.000 2319.556 25.288 ;
      RECT 0.500 27.400 2319.556 27.688 ;
      RECT 0.500 29.800 2319.556 30.088 ;
      RECT 0.500 32.200 2319.556 32.488 ;
      RECT 0.500 34.600 2319.556 34.888 ;
      RECT 0.500 37.000 2319.556 37.288 ;
      RECT 0.500 39.400 2319.556 39.688 ;
      RECT 0.500 41.800 2319.556 42.088 ;
      RECT 0.500 44.200 2319.556 44.488 ;
      RECT 0.500 46.600 2319.556 46.888 ;
      RECT 0.500 49.000 2319.556 49.288 ;
      RECT 0.500 51.400 2319.556 51.688 ;
      RECT 0.500 53.800 2319.556 54.088 ;
      RECT 0.500 56.200 2319.556 56.488 ;
      RECT 0.500 58.600 2319.556 58.888 ;
      RECT 0.500 61.000 2319.556 61.288 ;
      RECT 0.500 63.400 2319.556 63.688 ;
      RECT 0.500 65.800 2319.556 66.088 ;
      RECT 0.500 68.200 2319.556 68.488 ;
      RECT 0.500 70.600 2319.556 70.888 ;
      RECT 0.500 73.000 2319.556 73.288 ;
      RECT 0.500 75.400 2319.556 75.688 ;
      RECT 0.500 77.800 2319.556 78.088 ;
      RECT 0.500 80.200 2319.556 80.488 ;
      RECT 0.500 82.600 2319.556 82.888 ;
      RECT 0.500 85.000 2319.556 85.288 ;
      RECT 0.500 87.400 2319.556 87.688 ;
      RECT 0.500 89.800 2319.556 90.088 ;
      RECT 0.500 92.200 2319.556 92.488 ;
      RECT 0.500 94.600 2319.556 94.888 ;
      RECT 0.500 97.000 2319.556 97.288 ;
      RECT 0.500 99.400 2319.556 99.688 ;
      RECT 0.500 101.800 2319.556 102.088 ;
      RECT 0.500 104.200 2319.556 104.488 ;
      RECT 0.500 106.600 2319.556 106.888 ;
      RECT 0.500 109.000 2319.556 109.288 ;
      RECT 0.500 111.400 2319.556 111.688 ;
      RECT 0.500 113.800 2319.556 114.088 ;
      RECT 0.500 116.200 2319.556 116.488 ;
      RECT 0.500 118.600 2319.556 118.888 ;
      RECT 0.500 121.000 2319.556 121.288 ;
      RECT 0.500 123.400 2319.556 123.688 ;
      RECT 0.500 125.800 2319.556 126.088 ;
      RECT 0.500 128.200 2319.556 128.488 ;
      RECT 0.500 130.600 2319.556 130.888 ;
      RECT 0.500 133.000 2319.556 133.288 ;
      RECT 0.500 135.400 2319.556 135.688 ;
      RECT 0.500 137.800 2319.556 138.088 ;
      RECT 0.500 140.200 2319.556 140.488 ;
      RECT 0.500 142.600 2319.556 142.888 ;
      RECT 0.500 145.000 2319.556 145.288 ;
      RECT 0.500 147.400 2319.556 147.688 ;
      RECT 0.500 149.800 2319.556 150.088 ;
      RECT 0.500 152.200 2319.556 152.488 ;
      RECT 0.500 154.600 2319.556 154.888 ;
      RECT 0.500 157.000 2319.556 157.288 ;
      RECT 0.500 159.400 2319.556 159.688 ;
      RECT 0.500 161.800 2319.556 162.088 ;
      RECT 0.500 164.200 2319.556 164.488 ;
      RECT 0.500 166.600 2319.556 166.888 ;
      RECT 0.500 169.000 2319.556 169.288 ;
      RECT 0.500 171.400 2319.556 171.688 ;
      RECT 0.500 173.800 2319.556 174.088 ;
      RECT 0.500 176.200 2319.556 176.488 ;
      RECT 0.500 178.600 2319.556 178.888 ;
      RECT 0.500 181.000 2319.556 181.288 ;
      RECT 0.500 183.400 2319.556 183.688 ;
      RECT 0.500 185.800 2319.556 186.088 ;
      RECT 0.500 188.200 2319.556 188.488 ;
      RECT 0.500 190.600 2319.556 190.888 ;
      RECT 0.500 193.000 2319.556 193.288 ;
      RECT 0.500 195.400 2319.556 195.688 ;
      RECT 0.500 197.800 2319.556 198.088 ;
      RECT 0.500 200.200 2319.556 200.488 ;
      RECT 0.500 202.600 2319.556 202.888 ;
      RECT 0.500 205.000 2319.556 205.288 ;
      RECT 0.500 207.400 2319.556 207.688 ;
      RECT 0.500 209.800 2319.556 210.088 ;
      RECT 0.500 212.200 2319.556 212.488 ;
      RECT 0.500 214.600 2319.556 214.888 ;
      RECT 0.500 217.000 2319.556 217.288 ;
      RECT 0.500 219.400 2319.556 219.688 ;
      RECT 0.500 221.800 2319.556 222.088 ;
      RECT 0.500 224.200 2319.556 224.488 ;
      RECT 0.500 226.600 2319.556 226.888 ;
      RECT 0.500 229.000 2319.556 229.288 ;
      RECT 0.500 231.400 2319.556 231.688 ;
      RECT 0.500 233.800 2319.556 234.088 ;
      RECT 0.500 236.200 2319.556 236.488 ;
      RECT 0.500 238.600 2319.556 238.888 ;
      RECT 0.500 241.000 2319.556 241.288 ;
      RECT 0.500 243.400 2319.556 243.688 ;
      RECT 0.500 245.800 2319.556 246.088 ;
      RECT 0.500 248.200 2319.556 248.488 ;
      RECT 0.500 250.600 2319.556 250.888 ;
      RECT 0.500 253.000 2319.556 253.288 ;
      RECT 0.500 255.400 2319.556 255.688 ;
      RECT 0.500 257.800 2319.556 258.088 ;
      RECT 0.500 260.200 2319.556 260.488 ;
      RECT 0.500 262.600 2319.556 262.888 ;
      RECT 0.500 265.000 2319.556 265.288 ;
      RECT 0.500 267.400 2319.556 267.688 ;
      RECT 0.500 269.800 2319.556 270.088 ;
      RECT 0.500 272.200 2319.556 272.488 ;
      RECT 0.500 274.600 2319.556 274.888 ;
      RECT 0.500 277.000 2319.556 277.288 ;
      RECT 0.500 279.400 2319.556 279.688 ;
      RECT 0.500 281.800 2319.556 282.088 ;
      RECT 0.500 284.200 2319.556 284.488 ;
      RECT 0.500 286.600 2319.556 286.888 ;
      RECT 0.500 289.000 2319.556 289.288 ;
      RECT 0.500 291.400 2319.556 291.688 ;
      RECT 0.500 293.800 2319.556 294.088 ;
      RECT 0.500 296.200 2319.556 296.488 ;
      RECT 0.500 298.600 2319.556 298.888 ;
      RECT 0.500 301.000 2319.556 301.288 ;
      RECT 0.500 303.400 2319.556 303.688 ;
      RECT 0.500 305.800 2319.556 306.088 ;
      RECT 0.500 308.200 2319.556 308.488 ;
      RECT 0.500 310.600 2319.556 310.888 ;
      RECT 0.500 313.000 2319.556 313.288 ;
      RECT 0.500 315.400 2319.556 315.688 ;
      RECT 0.500 317.800 2319.556 318.088 ;
      RECT 0.500 320.200 2319.556 320.488 ;
      RECT 0.500 322.600 2319.556 322.888 ;
      RECT 0.500 325.000 2319.556 325.288 ;
      RECT 0.500 327.400 2319.556 327.688 ;
      RECT 0.500 329.800 2319.556 330.088 ;
      RECT 0.500 332.200 2319.556 332.488 ;
      RECT 0.500 334.600 2319.556 334.888 ;
      RECT 0.500 337.000 2319.556 337.288 ;
      RECT 0.500 339.400 2319.556 339.688 ;
      RECT 0.500 341.800 2319.556 342.088 ;
      RECT 0.500 344.200 2319.556 344.488 ;
      RECT 0.500 346.600 2319.556 346.888 ;
      RECT 0.500 349.000 2319.556 349.288 ;
      RECT 0.500 351.400 2319.556 351.688 ;
      RECT 0.500 353.800 2319.556 354.088 ;
      RECT 0.500 356.200 2319.556 356.488 ;
      RECT 0.500 358.600 2319.556 358.888 ;
      RECT 0.500 361.000 2319.556 361.288 ;
      RECT 0.500 363.400 2319.556 363.688 ;
      RECT 0.500 365.800 2319.556 366.088 ;
      RECT 0.500 368.200 2319.556 368.488 ;
      RECT 0.500 370.600 2319.556 370.888 ;
      RECT 0.500 373.000 2319.556 373.288 ;
      RECT 0.500 375.400 2319.556 375.688 ;
      RECT 0.500 377.800 2319.556 378.088 ;
      RECT 0.500 380.200 2319.556 380.488 ;
      RECT 0.500 382.600 2319.556 382.888 ;
      RECT 0.500 385.000 2319.556 385.288 ;
      RECT 0.500 387.400 2319.556 387.688 ;
      RECT 0.500 389.800 2319.556 390.088 ;
      RECT 0.500 392.200 2319.556 392.488 ;
      RECT 0.500 394.600 2319.556 394.888 ;
      RECT 0.500 397.000 2319.556 397.288 ;
      RECT 0.500 399.400 2319.556 399.688 ;
      RECT 0.500 401.800 2319.556 402.088 ;
      RECT 0.500 404.200 2319.556 404.488 ;
      RECT 0.500 406.600 2319.556 406.888 ;
      RECT 0.500 409.000 2319.556 409.288 ;
      RECT 0.500 411.400 2319.556 411.688 ;
      RECT 0.500 413.800 2319.556 414.088 ;
      RECT 0.500 416.200 2319.556 416.488 ;
      RECT 0.500 418.600 2319.556 418.888 ;
      RECT 0.500 421.000 2319.556 421.288 ;
      RECT 0.500 423.400 2319.556 423.688 ;
      RECT 0.500 425.800 2319.556 426.088 ;
      RECT 0.500 428.200 2319.556 428.488 ;
      RECT 0.500 430.600 2319.556 430.888 ;
      RECT 0.500 433.000 2319.556 433.288 ;
      RECT 0.500 435.400 2319.556 435.688 ;
      RECT 0.500 437.800 2319.556 438.088 ;
      RECT 0.500 440.200 2319.556 440.488 ;
      RECT 0.500 442.600 2319.556 442.888 ;
      RECT 0.500 445.000 2319.556 445.288 ;
      RECT 0.500 447.400 2319.556 447.688 ;
      RECT 0.500 449.800 2319.556 450.088 ;
      RECT 0.500 452.200 2319.556 452.488 ;
      RECT 0.500 454.600 2319.556 454.888 ;
      RECT 0.500 457.000 2319.556 457.288 ;
      RECT 0.500 459.400 2319.556 459.688 ;
      RECT 0.500 461.800 2319.556 462.088 ;
      RECT 0.500 464.200 2319.556 464.488 ;
      RECT 0.500 466.600 2319.556 466.888 ;
      RECT 0.500 469.000 2319.556 469.288 ;
      RECT 0.500 471.400 2319.556 471.688 ;
      RECT 0.500 473.800 2319.556 474.088 ;
      RECT 0.500 476.200 2319.556 476.488 ;
      RECT 0.500 478.600 2319.556 478.888 ;
      RECT 0.500 481.000 2319.556 481.288 ;
      RECT 0.500 483.400 2319.556 483.688 ;
      RECT 0.500 485.800 2319.556 486.088 ;
      RECT 0.500 488.200 2319.556 488.488 ;
      RECT 0.500 490.600 2319.556 490.888 ;
      RECT 0.500 493.000 2319.556 493.288 ;
      RECT 0.500 495.400 2319.556 495.688 ;
      RECT 0.500 497.800 2319.556 498.088 ;
      RECT 0.500 500.200 2319.556 500.488 ;
      RECT 0.500 502.600 2319.556 502.888 ;
      RECT 0.500 505.000 2319.556 505.288 ;
      RECT 0.500 507.400 2319.556 507.688 ;
      RECT 0.500 509.800 2319.556 510.088 ;
      RECT 0.500 512.200 2319.556 512.488 ;
      RECT 0.500 514.600 2319.556 514.888 ;
      RECT 0.500 517.000 2319.556 517.288 ;
      RECT 0.500 519.400 2319.556 519.688 ;
      RECT 0.500 521.800 2319.556 522.088 ;
      RECT 0.500 524.200 2319.556 524.488 ;
      RECT 0.500 526.600 2319.556 526.888 ;
      RECT 0.500 529.000 2319.556 529.288 ;
      RECT 0.500 531.400 2319.556 531.688 ;
      RECT 0.500 533.800 2319.556 534.088 ;
      RECT 0.500 536.200 2319.556 536.488 ;
      RECT 0.500 538.600 2319.556 538.888 ;
      RECT 0.500 541.000 2319.556 541.288 ;
      RECT 0.500 543.400 2319.556 543.688 ;
      RECT 0.500 545.800 2319.556 546.088 ;
      RECT 0.500 548.200 2319.556 548.488 ;
      RECT 0.500 550.600 2319.556 550.888 ;
      RECT 0.500 553.000 2319.556 553.288 ;
      RECT 0.500 555.400 2319.556 555.688 ;
      RECT 0.500 557.800 2319.556 558.088 ;
      RECT 0.500 560.200 2319.556 560.488 ;
      RECT 0.500 562.600 2319.556 562.888 ;
      RECT 0.500 565.000 2319.556 565.288 ;
      RECT 0.500 567.400 2319.556 567.688 ;
      RECT 0.500 569.800 2319.556 570.088 ;
      RECT 0.500 572.200 2319.556 572.488 ;
      RECT 0.500 574.600 2319.556 574.888 ;
      RECT 0.500 577.000 2319.556 577.288 ;
      RECT 0.500 579.400 2319.556 579.688 ;
      RECT 0.500 581.800 2319.556 582.088 ;
      RECT 0.500 584.200 2319.556 584.488 ;
      RECT 0.500 586.600 2319.556 586.888 ;
      RECT 0.500 589.000 2319.556 589.288 ;
      RECT 0.500 591.400 2319.556 591.688 ;
      RECT 0.500 593.800 2319.556 594.088 ;
      RECT 0.500 596.200 2319.556 596.488 ;
      RECT 0.500 598.600 2319.556 598.888 ;
      RECT 0.500 601.000 2319.556 601.288 ;
      RECT 0.500 603.400 2319.556 603.688 ;
      RECT 0.500 605.800 2319.556 606.088 ;
      RECT 0.500 608.200 2319.556 608.488 ;
      RECT 0.500 610.600 2319.556 610.888 ;
      RECT 0.500 613.000 2319.556 613.288 ;
      RECT 0.500 615.400 2319.556 615.688 ;
      RECT 0.500 617.800 2319.556 618.088 ;
      RECT 0.500 620.200 2319.556 620.488 ;
      RECT 0.500 622.600 2319.556 622.888 ;
      RECT 0.500 625.000 2319.556 625.288 ;
      RECT 0.500 627.400 2319.556 627.688 ;
      RECT 0.500 629.800 2319.556 630.088 ;
      RECT 0.500 632.200 2319.556 632.488 ;
      RECT 0.500 634.600 2319.556 634.888 ;
      RECT 0.500 637.000 2319.556 637.288 ;
      RECT 0.500 639.400 2319.556 639.688 ;
      RECT 0.500 641.800 2319.556 642.088 ;
      RECT 0.500 644.200 2319.556 644.488 ;
      RECT 0.500 646.600 2319.556 646.888 ;
      RECT 0.500 649.000 2319.556 649.288 ;
      RECT 0.500 651.400 2319.556 651.688 ;
      RECT 0.500 653.800 2319.556 654.088 ;
      RECT 0.500 656.200 2319.556 656.488 ;
      RECT 0.500 658.600 2319.556 658.888 ;
      RECT 0.500 661.000 2319.556 661.288 ;
      RECT 0.500 663.400 2319.556 663.688 ;
      RECT 0.500 665.800 2319.556 666.088 ;
      RECT 0.500 668.200 2319.556 668.488 ;
      RECT 0.500 670.600 2319.556 670.888 ;
      RECT 0.500 673.000 2319.556 673.288 ;
      RECT 0.500 675.400 2319.556 675.688 ;
      RECT 0.500 677.800 2319.556 678.088 ;
      RECT 0.500 680.200 2319.556 680.488 ;
      RECT 0.500 682.600 2319.556 682.888 ;
      RECT 0.500 685.000 2319.556 685.288 ;
      RECT 0.500 687.400 2319.556 687.688 ;
      RECT 0.500 689.800 2319.556 690.088 ;
      RECT 0.500 692.200 2319.556 692.488 ;
      RECT 0.500 694.600 2319.556 694.888 ;
      RECT 0.500 697.000 2319.556 697.288 ;
      RECT 0.500 699.400 2319.556 699.688 ;
      RECT 0.500 701.800 2319.556 702.088 ;
      RECT 0.500 704.200 2319.556 704.488 ;
      RECT 0.500 706.600 2319.556 706.888 ;
      RECT 0.500 709.000 2319.556 709.288 ;
      RECT 0.500 711.400 2319.556 711.688 ;
      RECT 0.500 713.800 2319.556 714.088 ;
      RECT 0.500 716.200 2319.556 716.488 ;
      RECT 0.500 718.600 2319.556 718.888 ;
      RECT 0.500 721.000 2319.556 721.288 ;
      RECT 0.500 723.400 2319.556 723.688 ;
      RECT 0.500 725.800 2319.556 726.088 ;
      RECT 0.500 728.200 2319.556 728.488 ;
      RECT 0.500 730.600 2319.556 730.888 ;
      RECT 0.500 733.000 2319.556 733.288 ;
      RECT 0.500 735.400 2319.556 735.688 ;
      RECT 0.500 737.800 2319.556 738.088 ;
      RECT 0.500 740.200 2319.556 740.488 ;
      RECT 0.500 742.600 2319.556 742.888 ;
      RECT 0.500 745.000 2319.556 745.288 ;
      RECT 0.500 747.400 2319.556 747.688 ;
      RECT 0.500 749.800 2319.556 750.088 ;
      RECT 0.500 752.200 2319.556 752.488 ;
      RECT 0.500 754.600 2319.556 754.888 ;
      RECT 0.500 757.000 2319.556 757.288 ;
      RECT 0.500 759.400 2319.556 759.688 ;
      RECT 0.500 761.800 2319.556 762.088 ;
      RECT 0.500 764.200 2319.556 764.488 ;
      RECT 0.500 766.600 2319.556 766.888 ;
      RECT 0.500 769.000 2319.556 769.288 ;
      RECT 0.500 771.400 2319.556 771.688 ;
      RECT 0.500 773.800 2319.556 774.088 ;
      RECT 0.500 776.200 2319.556 776.488 ;
      RECT 0.500 778.600 2319.556 778.888 ;
      RECT 0.500 781.000 2319.556 781.288 ;
      RECT 0.500 783.400 2319.556 783.688 ;
      RECT 0.500 785.800 2319.556 786.088 ;
      RECT 0.500 788.200 2319.556 788.488 ;
      RECT 0.500 790.600 2319.556 790.888 ;
      RECT 0.500 793.000 2319.556 793.288 ;
      RECT 0.500 795.400 2319.556 795.688 ;
      RECT 0.500 797.800 2319.556 798.088 ;
      RECT 0.500 800.200 2319.556 800.488 ;
      RECT 0.500 802.600 2319.556 802.888 ;
      RECT 0.500 805.000 2319.556 805.288 ;
      RECT 0.500 807.400 2319.556 807.688 ;
      RECT 0.500 809.800 2319.556 810.088 ;
      RECT 0.500 812.200 2319.556 812.488 ;
      RECT 0.500 814.600 2319.556 814.888 ;
      RECT 0.500 817.000 2319.556 817.288 ;
      RECT 0.500 819.400 2319.556 819.688 ;
      RECT 0.500 821.800 2319.556 822.088 ;
      RECT 0.500 824.200 2319.556 824.488 ;
      RECT 0.500 826.600 2319.556 826.888 ;
      RECT 0.500 829.000 2319.556 829.288 ;
      RECT 0.500 831.400 2319.556 831.688 ;
      RECT 0.500 833.800 2319.556 834.088 ;
      RECT 0.500 836.200 2319.556 836.488 ;
      RECT 0.500 838.600 2319.556 838.888 ;
      RECT 0.500 841.000 2319.556 841.288 ;
      RECT 0.500 843.400 2319.556 843.688 ;
      RECT 0.500 845.800 2319.556 846.088 ;
      RECT 0.500 848.200 2319.556 848.488 ;
      RECT 0.500 850.600 2319.556 850.888 ;
      RECT 0.500 853.000 2319.556 853.288 ;
      RECT 0.500 855.400 2319.556 855.688 ;
      RECT 0.500 857.800 2319.556 858.088 ;
      RECT 0.500 860.200 2319.556 860.488 ;
      RECT 0.500 862.600 2319.556 862.888 ;
      RECT 0.500 865.000 2319.556 865.288 ;
      RECT 0.500 867.400 2319.556 867.688 ;
      RECT 0.500 869.800 2319.556 870.088 ;
      RECT 0.500 872.200 2319.556 872.488 ;
      RECT 0.500 874.600 2319.556 874.888 ;
      RECT 0.500 877.000 2319.556 877.288 ;
      RECT 0.500 879.400 2319.556 879.688 ;
      RECT 0.500 881.800 2319.556 882.088 ;
      RECT 0.500 884.200 2319.556 884.488 ;
      RECT 0.500 886.600 2319.556 886.888 ;
      RECT 0.500 889.000 2319.556 889.288 ;
      RECT 0.500 891.400 2319.556 891.688 ;
      RECT 0.500 893.800 2319.556 894.088 ;
      RECT 0.500 896.200 2319.556 896.488 ;
      RECT 0.500 898.600 2319.556 898.888 ;
      RECT 0.500 901.000 2319.556 901.288 ;
      RECT 0.500 903.400 2319.556 903.688 ;
      RECT 0.500 905.800 2319.556 906.088 ;
      RECT 0.500 908.200 2319.556 908.488 ;
      RECT 0.500 910.600 2319.556 910.888 ;
      RECT 0.500 913.000 2319.556 913.288 ;
      RECT 0.500 915.400 2319.556 915.688 ;
      RECT 0.500 917.800 2319.556 918.088 ;
      RECT 0.500 920.200 2319.556 920.488 ;
      RECT 0.500 922.600 2319.556 922.888 ;
      RECT 0.500 925.000 2319.556 925.288 ;
      RECT 0.500 927.400 2319.556 927.688 ;
      RECT 0.500 929.800 2319.556 930.088 ;
      RECT 0.500 932.200 2319.556 932.488 ;
      RECT 0.500 934.600 2319.556 934.888 ;
      RECT 0.500 937.000 2319.556 937.288 ;
      RECT 0.500 939.400 2319.556 939.688 ;
      RECT 0.500 941.800 2319.556 942.088 ;
      RECT 0.500 944.200 2319.556 944.488 ;
      RECT 0.500 946.600 2319.556 946.888 ;
      RECT 0.500 949.000 2319.556 949.288 ;
      RECT 0.500 951.400 2319.556 951.688 ;
      RECT 0.500 953.800 2319.556 954.088 ;
      RECT 0.500 956.200 2319.556 956.488 ;
      RECT 0.500 958.600 2319.556 958.888 ;
      RECT 0.500 961.000 2319.556 961.288 ;
      RECT 0.500 963.400 2319.556 963.688 ;
      RECT 0.500 965.800 2319.556 966.088 ;
      RECT 0.500 968.200 2319.556 968.488 ;
      RECT 0.500 970.600 2319.556 970.888 ;
      RECT 0.500 973.000 2319.556 973.288 ;
      RECT 0.500 975.400 2319.556 975.688 ;
      RECT 0.500 977.800 2319.556 978.088 ;
      RECT 0.500 980.200 2319.556 980.488 ;
      RECT 0.500 982.600 2319.556 982.888 ;
      RECT 0.500 985.000 2319.556 985.288 ;
      RECT 0.500 987.400 2319.556 987.688 ;
      RECT 0.500 989.800 2319.556 990.088 ;
      RECT 0.500 992.200 2319.556 992.488 ;
      RECT 0.500 994.600 2319.556 994.888 ;
      RECT 0.500 997.000 2319.556 997.288 ;
      RECT 0.500 999.400 2319.556 999.688 ;
      RECT 0.500 1001.800 2319.556 1002.088 ;
      RECT 0.500 1004.200 2319.556 1004.488 ;
      RECT 0.500 1006.600 2319.556 1006.888 ;
      RECT 0.500 1009.000 2319.556 1009.288 ;
      RECT 0.500 1011.400 2319.556 1011.688 ;
      RECT 0.500 1013.800 2319.556 1014.088 ;
      RECT 0.500 1016.200 2319.556 1016.488 ;
      RECT 0.500 1018.600 2319.556 1018.888 ;
      RECT 0.500 1021.000 2319.556 1021.288 ;
      RECT 0.500 1023.400 2319.556 1023.688 ;
      RECT 0.500 1025.800 2319.556 1026.088 ;
      RECT 0.500 1028.200 2319.556 1028.488 ;
      RECT 0.500 1030.600 2319.556 1030.888 ;
      RECT 0.500 1033.000 2319.556 1033.288 ;
      RECT 0.500 1035.400 2319.556 1035.688 ;
      RECT 0.500 1037.800 2319.556 1038.088 ;
      RECT 0.500 1040.200 2319.556 1040.488 ;
      RECT 0.500 1042.600 2319.556 1042.888 ;
      RECT 0.500 1045.000 2319.556 1045.288 ;
      RECT 0.500 1047.400 2319.556 1047.688 ;
      RECT 0.500 1049.800 2319.556 1050.088 ;
      RECT 0.500 1052.200 2319.556 1052.488 ;
      RECT 0.500 1054.600 2319.556 1054.888 ;
      RECT 0.500 1057.000 2319.556 1057.288 ;
      RECT 0.500 1059.400 2319.556 1059.688 ;
      RECT 0.500 1061.800 2319.556 1062.088 ;
      RECT 0.500 1064.200 2319.556 1064.488 ;
      RECT 0.500 1066.600 2319.556 1066.888 ;
      RECT 0.500 1069.000 2319.556 1069.288 ;
      RECT 0.500 1071.400 2319.556 1071.688 ;
      RECT 0.500 1073.800 2319.556 1074.088 ;
      RECT 0.500 1076.200 2319.556 1076.488 ;
      RECT 0.500 1078.600 2319.556 1078.888 ;
      RECT 0.500 1081.000 2319.556 1081.288 ;
      RECT 0.500 1083.400 2319.556 1083.688 ;
      RECT 0.500 1085.800 2319.556 1086.088 ;
      RECT 0.500 1088.200 2319.556 1088.488 ;
      RECT 0.500 1090.600 2319.556 1090.888 ;
      RECT 0.500 1093.000 2319.556 1093.288 ;
      RECT 0.500 1095.400 2319.556 1095.688 ;
      RECT 0.500 1097.800 2319.556 1098.088 ;
      RECT 0.500 1100.200 2319.556 1100.488 ;
      RECT 0.500 1102.600 2319.556 1102.888 ;
      RECT 0.500 1105.000 2319.556 1105.288 ;
      RECT 0.500 1107.400 2319.556 1107.688 ;
      RECT 0.500 1109.800 2319.556 1110.088 ;
      RECT 0.500 1112.200 2319.556 1112.488 ;
      RECT 0.500 1114.600 2319.556 1114.888 ;
      RECT 0.500 1117.000 2319.556 1117.288 ;
      RECT 0.500 1119.400 2319.556 1119.688 ;
      RECT 0.500 1121.800 2319.556 1122.088 ;
      RECT 0.500 1124.200 2319.556 1124.488 ;
      RECT 0.500 1126.600 2319.556 1126.888 ;
      RECT 0.500 1129.000 2319.556 1129.288 ;
      RECT 0.500 1131.400 2319.556 1131.688 ;
      RECT 0.500 1133.800 2319.556 1134.088 ;
      RECT 0.500 1136.200 2319.556 1136.488 ;
      RECT 0.500 1138.600 2319.556 1138.888 ;
      RECT 0.500 1141.000 2319.556 1141.288 ;
      RECT 0.500 1143.400 2319.556 1143.688 ;
      RECT 0.500 1145.800 2319.556 1146.088 ;
      RECT 0.500 1148.200 2319.556 1148.488 ;
      RECT 0.500 1150.600 2319.556 1150.888 ;
      RECT 0.500 1153.000 2319.556 1153.288 ;
      RECT 0.500 1155.400 2319.556 1155.688 ;
      RECT 0.500 1157.800 2319.556 1158.088 ;
      RECT 0.500 1160.200 2319.556 1160.488 ;
      RECT 0.500 1162.600 2319.556 1162.888 ;
      RECT 0.500 1165.000 2319.556 1165.288 ;
      RECT 0.500 1167.400 2319.556 1167.688 ;
      RECT 0.500 1169.800 2319.556 1170.088 ;
      RECT 0.500 1172.200 2319.556 1172.488 ;
      RECT 0.500 1174.600 2319.556 1174.888 ;
      RECT 0.500 1177.000 2319.556 1177.288 ;
      RECT 0.500 1179.400 2319.556 1179.688 ;
      RECT 0.500 1181.800 2319.556 1182.088 ;
      RECT 0.500 1184.200 2319.556 1184.488 ;
      RECT 0.500 1186.600 2319.556 1186.888 ;
      RECT 0.500 1189.000 2319.556 1189.288 ;
      RECT 0.500 1191.400 2319.556 1191.688 ;
      RECT 0.500 1193.800 2319.556 1194.088 ;
      RECT 0.500 1196.200 2319.556 1196.488 ;
      RECT 0.500 1198.600 2319.556 1198.888 ;
      RECT 0.500 1201.000 2319.556 1201.288 ;
      RECT 0.500 1203.400 2319.556 1203.688 ;
      RECT 0.500 1205.800 2319.556 1206.088 ;
      RECT 0.500 1208.200 2319.556 1208.488 ;
      RECT 0.500 1210.600 2319.556 1210.888 ;
      RECT 0.500 1213.000 2319.556 1213.288 ;
      RECT 0.500 1215.400 2319.556 1215.688 ;
      RECT 0.500 1217.800 2319.556 1218.088 ;
      RECT 0.500 1220.200 2319.556 1220.488 ;
      RECT 0.500 1222.600 2319.556 1222.888 ;
      RECT 0.500 1225.000 2319.556 1225.288 ;
      RECT 0.500 1227.400 2319.556 1227.688 ;
      RECT 0.500 1229.800 2319.556 1230.088 ;
      RECT 0.500 1232.200 2319.556 1232.488 ;
      RECT 0.500 1234.600 2319.556 1234.888 ;
      RECT 0.500 1237.000 2319.556 1237.288 ;
      RECT 0.500 1239.400 2319.556 1239.688 ;
      RECT 0.500 1241.800 2319.556 1242.088 ;
      RECT 0.500 1244.200 2319.556 1244.488 ;
      RECT 0.500 1246.600 2319.556 1246.888 ;
      RECT 0.500 1249.000 2319.556 1249.288 ;
      RECT 0.500 1251.400 2319.556 1251.688 ;
      RECT 0.500 1253.800 2319.556 1254.088 ;
      RECT 0.500 1256.200 2319.556 1256.488 ;
      RECT 0.500 1258.600 2319.556 1258.888 ;
      RECT 0.500 1261.000 2319.556 1261.288 ;
      RECT 0.500 1263.400 2319.556 1263.688 ;
      RECT 0.500 1265.800 2319.556 1266.088 ;
      RECT 0.500 1268.200 2319.556 1268.488 ;
      RECT 0.500 1270.600 2319.556 1270.888 ;
      RECT 0.500 1273.000 2319.556 1273.288 ;
      RECT 0.500 1275.400 2319.556 1275.688 ;
      RECT 0.500 1277.800 2319.556 1278.088 ;
      RECT 0.500 1280.200 2319.556 1280.488 ;
      RECT 0.500 1282.600 2319.556 1282.888 ;
      RECT 0.500 1285.000 2319.556 1285.288 ;
      RECT 0.500 1287.400 2319.556 1287.688 ;
      RECT 0.500 1289.800 2319.556 1290.088 ;
      RECT 0.500 1292.200 2319.556 1292.488 ;
      RECT 0.500 1294.600 2319.556 1294.888 ;
      RECT 0.500 1297.000 2319.556 1297.288 ;
      RECT 0.500 1299.400 2319.556 1299.688 ;
      RECT 0.500 1301.800 2319.556 1302.088 ;
      RECT 0.500 1304.200 2319.556 1304.488 ;
      RECT 0.500 1306.600 2319.556 1306.888 ;
      RECT 0.500 1309.000 2319.556 1309.288 ;
      RECT 0.500 1311.400 2319.556 1311.688 ;
      RECT 0.500 1313.800 2319.556 1314.088 ;
      RECT 0.500 1316.200 2319.556 1316.488 ;
      RECT 0.500 1318.600 2319.556 1318.888 ;
      RECT 0.500 1321.000 2319.556 1321.288 ;
      RECT 0.500 1323.400 2319.556 1323.688 ;
      RECT 0.500 1325.800 2319.556 1326.088 ;
      RECT 0.500 1328.200 2319.556 1328.488 ;
      RECT 0.500 1330.600 2319.556 1330.888 ;
      RECT 0.500 1333.000 2319.556 1333.288 ;
      RECT 0.500 1335.400 2319.556 1335.688 ;
      RECT 0.500 1337.800 2319.556 1338.088 ;
      RECT 0.500 1340.200 2319.556 1340.488 ;
      RECT 0.500 1342.600 2319.556 1342.888 ;
      RECT 0.500 1345.000 2319.556 1345.288 ;
      RECT 0.500 1347.400 2319.556 1347.688 ;
      RECT 0.500 1349.800 2319.556 1350.088 ;
      RECT 0.500 1352.200 2319.556 1352.488 ;
      RECT 0.500 1354.600 2319.556 1354.888 ;
      RECT 0.500 1357.000 2319.556 1357.288 ;
      RECT 0.500 1359.400 2319.556 1359.688 ;
      RECT 0.500 1361.800 2319.556 1362.088 ;
      RECT 0.500 1364.200 2319.556 1364.488 ;
      RECT 0.500 1366.600 2319.556 1366.888 ;
      RECT 0.500 1369.000 2319.556 1369.288 ;
      RECT 0.500 1371.400 2319.556 1371.688 ;
      RECT 0.500 1373.800 2319.556 1374.088 ;
      RECT 0.500 1376.200 2319.556 1376.488 ;
      RECT 0.500 1378.600 2319.556 1378.888 ;
      RECT 0.500 1381.000 2319.556 1381.288 ;
      RECT 0.500 1383.400 2319.556 1383.688 ;
      RECT 0.500 1385.800 2319.556 1386.088 ;
      RECT 0.500 1388.200 2319.556 1388.488 ;
      RECT 0.500 1390.600 2319.556 1390.888 ;
      RECT 0.500 1393.000 2319.556 1393.288 ;
      RECT 0.500 1395.400 2319.556 1395.688 ;
      RECT 0.500 1397.800 2319.556 1398.088 ;
      RECT 0.500 1400.200 2319.556 1400.488 ;
      RECT 0.500 1402.600 2319.556 1402.888 ;
      RECT 0.500 1405.000 2319.556 1405.288 ;
      RECT 0.500 1407.400 2319.556 1407.688 ;
      RECT 0.500 1409.800 2319.556 1410.088 ;
      RECT 0.500 1412.200 2319.556 1412.488 ;
      RECT 0.500 1414.600 2319.556 1414.888 ;
      RECT 0.500 1417.000 2319.556 1417.288 ;
      RECT 0.500 1419.400 2319.556 1419.688 ;
      RECT 0.500 1421.800 2319.556 1422.088 ;
      RECT 0.500 1424.200 2319.556 1424.488 ;
      RECT 0.500 1426.600 2319.556 1426.888 ;
      RECT 0.500 1429.000 2319.556 1429.288 ;
      RECT 0.500 1431.400 2319.556 1431.688 ;
      RECT 0.500 1433.800 2319.556 1434.088 ;
      RECT 0.500 1436.200 2319.556 1436.488 ;
      RECT 0.500 1438.600 2319.556 1438.888 ;
      RECT 0.500 1441.000 2319.556 1441.288 ;
      RECT 0.500 1443.400 2319.556 1443.688 ;
      RECT 0.500 1445.800 2319.556 1446.088 ;
      RECT 0.500 1448.200 2319.556 1448.488 ;
      RECT 0.500 1450.600 2319.556 1450.888 ;
      RECT 0.500 1453.000 2319.556 1453.288 ;
      RECT 0.500 1455.400 2319.556 1455.688 ;
      RECT 0.500 1457.800 2319.556 1458.088 ;
      RECT 0.500 1460.200 2319.556 1460.488 ;
      RECT 0.500 1462.600 2319.556 1462.888 ;
      RECT 0.500 1465.000 2319.556 1465.288 ;
      RECT 0.500 1467.400 2319.556 1467.688 ;
      RECT 0.500 1469.800 2319.556 1470.088 ;
      RECT 0.500 1472.200 2319.556 1472.488 ;
      RECT 0.500 1474.600 2319.556 1474.888 ;
      RECT 0.500 1477.000 2319.556 1477.288 ;
      RECT 0.500 1479.400 2319.556 1479.688 ;
      RECT 0.500 1481.800 2319.556 1482.088 ;
      RECT 0.500 1484.200 2319.556 1484.488 ;
      RECT 0.500 1486.600 2319.556 1486.888 ;
      RECT 0.500 1489.000 2319.556 1489.288 ;
      RECT 0.500 1491.400 2319.556 1491.688 ;
      RECT 0.500 1493.800 2319.556 1494.088 ;
      RECT 0.500 1496.200 2319.556 1496.488 ;
      RECT 0.500 1498.600 2319.556 1498.888 ;
      RECT 0.500 1501.000 2319.556 1501.288 ;
      RECT 0.500 1503.400 2319.556 1503.688 ;
      RECT 0.500 1505.800 2319.556 1506.088 ;
      RECT 0.500 1508.200 2319.556 1508.488 ;
      RECT 0.500 1510.600 2319.556 1510.888 ;
      RECT 0.500 1513.000 2319.556 1513.288 ;
      RECT 0.500 1515.400 2319.556 1515.688 ;
      RECT 0.500 1517.800 2319.556 1518.088 ;
      RECT 0.500 1520.200 2319.556 1520.488 ;
      RECT 0.500 1522.600 2319.556 1522.888 ;
      RECT 0.500 1525.000 2319.556 1525.288 ;
      RECT 0.500 1527.400 2319.556 1527.688 ;
      RECT 0.500 1529.800 2319.556 1530.088 ;
      RECT 0.500 1532.200 2319.556 1532.488 ;
      RECT 0.500 1534.600 2319.556 1534.888 ;
      RECT 0.500 1537.000 2319.556 1537.288 ;
      RECT 0.500 1539.400 2319.556 1539.688 ;
      RECT 0.500 1541.800 2319.556 1542.088 ;
      RECT 0.500 1544.200 2319.556 1544.488 ;
      RECT 0.500 1546.600 2319.556 1546.888 ;
      RECT 0.500 1549.000 2319.556 1549.288 ;
      RECT 0.500 1551.400 2319.556 1551.688 ;
      RECT 0.500 1553.800 2319.556 1554.088 ;
      RECT 0.500 1556.200 2319.556 1556.488 ;
      RECT 0.500 1558.600 2319.556 1558.888 ;
      RECT 0.500 1561.000 2319.556 1561.288 ;
    END
  END VDD
  PIN VSS
    DIRECTION INOUT ;
    USE GROUND ;
    PORT
      LAYER M4 ;
      RECT 0.500 2.200 2319.556 2.488 ;
      RECT 0.500 4.600 2319.556 4.888 ;
      RECT 0.500 7.000 2319.556 7.288 ;
      RECT 0.500 9.400 2319.556 9.688 ;
      RECT 0.500 11.800 2319.556 12.088 ;
      RECT 0.500 14.200 2319.556 14.488 ;
      RECT 0.500 16.600 2319.556 16.888 ;
      RECT 0.500 19.000 2319.556 19.288 ;
      RECT 0.500 21.400 2319.556 21.688 ;
      RECT 0.500 23.800 2319.556 24.088 ;
      RECT 0.500 26.200 2319.556 26.488 ;
      RECT 0.500 28.600 2319.556 28.888 ;
      RECT 0.500 31.000 2319.556 31.288 ;
      RECT 0.500 33.400 2319.556 33.688 ;
      RECT 0.500 35.800 2319.556 36.088 ;
      RECT 0.500 38.200 2319.556 38.488 ;
      RECT 0.500 40.600 2319.556 40.888 ;
      RECT 0.500 43.000 2319.556 43.288 ;
      RECT 0.500 45.400 2319.556 45.688 ;
      RECT 0.500 47.800 2319.556 48.088 ;
      RECT 0.500 50.200 2319.556 50.488 ;
      RECT 0.500 52.600 2319.556 52.888 ;
      RECT 0.500 55.000 2319.556 55.288 ;
      RECT 0.500 57.400 2319.556 57.688 ;
      RECT 0.500 59.800 2319.556 60.088 ;
      RECT 0.500 62.200 2319.556 62.488 ;
      RECT 0.500 64.600 2319.556 64.888 ;
      RECT 0.500 67.000 2319.556 67.288 ;
      RECT 0.500 69.400 2319.556 69.688 ;
      RECT 0.500 71.800 2319.556 72.088 ;
      RECT 0.500 74.200 2319.556 74.488 ;
      RECT 0.500 76.600 2319.556 76.888 ;
      RECT 0.500 79.000 2319.556 79.288 ;
      RECT 0.500 81.400 2319.556 81.688 ;
      RECT 0.500 83.800 2319.556 84.088 ;
      RECT 0.500 86.200 2319.556 86.488 ;
      RECT 0.500 88.600 2319.556 88.888 ;
      RECT 0.500 91.000 2319.556 91.288 ;
      RECT 0.500 93.400 2319.556 93.688 ;
      RECT 0.500 95.800 2319.556 96.088 ;
      RECT 0.500 98.200 2319.556 98.488 ;
      RECT 0.500 100.600 2319.556 100.888 ;
      RECT 0.500 103.000 2319.556 103.288 ;
      RECT 0.500 105.400 2319.556 105.688 ;
      RECT 0.500 107.800 2319.556 108.088 ;
      RECT 0.500 110.200 2319.556 110.488 ;
      RECT 0.500 112.600 2319.556 112.888 ;
      RECT 0.500 115.000 2319.556 115.288 ;
      RECT 0.500 117.400 2319.556 117.688 ;
      RECT 0.500 119.800 2319.556 120.088 ;
      RECT 0.500 122.200 2319.556 122.488 ;
      RECT 0.500 124.600 2319.556 124.888 ;
      RECT 0.500 127.000 2319.556 127.288 ;
      RECT 0.500 129.400 2319.556 129.688 ;
      RECT 0.500 131.800 2319.556 132.088 ;
      RECT 0.500 134.200 2319.556 134.488 ;
      RECT 0.500 136.600 2319.556 136.888 ;
      RECT 0.500 139.000 2319.556 139.288 ;
      RECT 0.500 141.400 2319.556 141.688 ;
      RECT 0.500 143.800 2319.556 144.088 ;
      RECT 0.500 146.200 2319.556 146.488 ;
      RECT 0.500 148.600 2319.556 148.888 ;
      RECT 0.500 151.000 2319.556 151.288 ;
      RECT 0.500 153.400 2319.556 153.688 ;
      RECT 0.500 155.800 2319.556 156.088 ;
      RECT 0.500 158.200 2319.556 158.488 ;
      RECT 0.500 160.600 2319.556 160.888 ;
      RECT 0.500 163.000 2319.556 163.288 ;
      RECT 0.500 165.400 2319.556 165.688 ;
      RECT 0.500 167.800 2319.556 168.088 ;
      RECT 0.500 170.200 2319.556 170.488 ;
      RECT 0.500 172.600 2319.556 172.888 ;
      RECT 0.500 175.000 2319.556 175.288 ;
      RECT 0.500 177.400 2319.556 177.688 ;
      RECT 0.500 179.800 2319.556 180.088 ;
      RECT 0.500 182.200 2319.556 182.488 ;
      RECT 0.500 184.600 2319.556 184.888 ;
      RECT 0.500 187.000 2319.556 187.288 ;
      RECT 0.500 189.400 2319.556 189.688 ;
      RECT 0.500 191.800 2319.556 192.088 ;
      RECT 0.500 194.200 2319.556 194.488 ;
      RECT 0.500 196.600 2319.556 196.888 ;
      RECT 0.500 199.000 2319.556 199.288 ;
      RECT 0.500 201.400 2319.556 201.688 ;
      RECT 0.500 203.800 2319.556 204.088 ;
      RECT 0.500 206.200 2319.556 206.488 ;
      RECT 0.500 208.600 2319.556 208.888 ;
      RECT 0.500 211.000 2319.556 211.288 ;
      RECT 0.500 213.400 2319.556 213.688 ;
      RECT 0.500 215.800 2319.556 216.088 ;
      RECT 0.500 218.200 2319.556 218.488 ;
      RECT 0.500 220.600 2319.556 220.888 ;
      RECT 0.500 223.000 2319.556 223.288 ;
      RECT 0.500 225.400 2319.556 225.688 ;
      RECT 0.500 227.800 2319.556 228.088 ;
      RECT 0.500 230.200 2319.556 230.488 ;
      RECT 0.500 232.600 2319.556 232.888 ;
      RECT 0.500 235.000 2319.556 235.288 ;
      RECT 0.500 237.400 2319.556 237.688 ;
      RECT 0.500 239.800 2319.556 240.088 ;
      RECT 0.500 242.200 2319.556 242.488 ;
      RECT 0.500 244.600 2319.556 244.888 ;
      RECT 0.500 247.000 2319.556 247.288 ;
      RECT 0.500 249.400 2319.556 249.688 ;
      RECT 0.500 251.800 2319.556 252.088 ;
      RECT 0.500 254.200 2319.556 254.488 ;
      RECT 0.500 256.600 2319.556 256.888 ;
      RECT 0.500 259.000 2319.556 259.288 ;
      RECT 0.500 261.400 2319.556 261.688 ;
      RECT 0.500 263.800 2319.556 264.088 ;
      RECT 0.500 266.200 2319.556 266.488 ;
      RECT 0.500 268.600 2319.556 268.888 ;
      RECT 0.500 271.000 2319.556 271.288 ;
      RECT 0.500 273.400 2319.556 273.688 ;
      RECT 0.500 275.800 2319.556 276.088 ;
      RECT 0.500 278.200 2319.556 278.488 ;
      RECT 0.500 280.600 2319.556 280.888 ;
      RECT 0.500 283.000 2319.556 283.288 ;
      RECT 0.500 285.400 2319.556 285.688 ;
      RECT 0.500 287.800 2319.556 288.088 ;
      RECT 0.500 290.200 2319.556 290.488 ;
      RECT 0.500 292.600 2319.556 292.888 ;
      RECT 0.500 295.000 2319.556 295.288 ;
      RECT 0.500 297.400 2319.556 297.688 ;
      RECT 0.500 299.800 2319.556 300.088 ;
      RECT 0.500 302.200 2319.556 302.488 ;
      RECT 0.500 304.600 2319.556 304.888 ;
      RECT 0.500 307.000 2319.556 307.288 ;
      RECT 0.500 309.400 2319.556 309.688 ;
      RECT 0.500 311.800 2319.556 312.088 ;
      RECT 0.500 314.200 2319.556 314.488 ;
      RECT 0.500 316.600 2319.556 316.888 ;
      RECT 0.500 319.000 2319.556 319.288 ;
      RECT 0.500 321.400 2319.556 321.688 ;
      RECT 0.500 323.800 2319.556 324.088 ;
      RECT 0.500 326.200 2319.556 326.488 ;
      RECT 0.500 328.600 2319.556 328.888 ;
      RECT 0.500 331.000 2319.556 331.288 ;
      RECT 0.500 333.400 2319.556 333.688 ;
      RECT 0.500 335.800 2319.556 336.088 ;
      RECT 0.500 338.200 2319.556 338.488 ;
      RECT 0.500 340.600 2319.556 340.888 ;
      RECT 0.500 343.000 2319.556 343.288 ;
      RECT 0.500 345.400 2319.556 345.688 ;
      RECT 0.500 347.800 2319.556 348.088 ;
      RECT 0.500 350.200 2319.556 350.488 ;
      RECT 0.500 352.600 2319.556 352.888 ;
      RECT 0.500 355.000 2319.556 355.288 ;
      RECT 0.500 357.400 2319.556 357.688 ;
      RECT 0.500 359.800 2319.556 360.088 ;
      RECT 0.500 362.200 2319.556 362.488 ;
      RECT 0.500 364.600 2319.556 364.888 ;
      RECT 0.500 367.000 2319.556 367.288 ;
      RECT 0.500 369.400 2319.556 369.688 ;
      RECT 0.500 371.800 2319.556 372.088 ;
      RECT 0.500 374.200 2319.556 374.488 ;
      RECT 0.500 376.600 2319.556 376.888 ;
      RECT 0.500 379.000 2319.556 379.288 ;
      RECT 0.500 381.400 2319.556 381.688 ;
      RECT 0.500 383.800 2319.556 384.088 ;
      RECT 0.500 386.200 2319.556 386.488 ;
      RECT 0.500 388.600 2319.556 388.888 ;
      RECT 0.500 391.000 2319.556 391.288 ;
      RECT 0.500 393.400 2319.556 393.688 ;
      RECT 0.500 395.800 2319.556 396.088 ;
      RECT 0.500 398.200 2319.556 398.488 ;
      RECT 0.500 400.600 2319.556 400.888 ;
      RECT 0.500 403.000 2319.556 403.288 ;
      RECT 0.500 405.400 2319.556 405.688 ;
      RECT 0.500 407.800 2319.556 408.088 ;
      RECT 0.500 410.200 2319.556 410.488 ;
      RECT 0.500 412.600 2319.556 412.888 ;
      RECT 0.500 415.000 2319.556 415.288 ;
      RECT 0.500 417.400 2319.556 417.688 ;
      RECT 0.500 419.800 2319.556 420.088 ;
      RECT 0.500 422.200 2319.556 422.488 ;
      RECT 0.500 424.600 2319.556 424.888 ;
      RECT 0.500 427.000 2319.556 427.288 ;
      RECT 0.500 429.400 2319.556 429.688 ;
      RECT 0.500 431.800 2319.556 432.088 ;
      RECT 0.500 434.200 2319.556 434.488 ;
      RECT 0.500 436.600 2319.556 436.888 ;
      RECT 0.500 439.000 2319.556 439.288 ;
      RECT 0.500 441.400 2319.556 441.688 ;
      RECT 0.500 443.800 2319.556 444.088 ;
      RECT 0.500 446.200 2319.556 446.488 ;
      RECT 0.500 448.600 2319.556 448.888 ;
      RECT 0.500 451.000 2319.556 451.288 ;
      RECT 0.500 453.400 2319.556 453.688 ;
      RECT 0.500 455.800 2319.556 456.088 ;
      RECT 0.500 458.200 2319.556 458.488 ;
      RECT 0.500 460.600 2319.556 460.888 ;
      RECT 0.500 463.000 2319.556 463.288 ;
      RECT 0.500 465.400 2319.556 465.688 ;
      RECT 0.500 467.800 2319.556 468.088 ;
      RECT 0.500 470.200 2319.556 470.488 ;
      RECT 0.500 472.600 2319.556 472.888 ;
      RECT 0.500 475.000 2319.556 475.288 ;
      RECT 0.500 477.400 2319.556 477.688 ;
      RECT 0.500 479.800 2319.556 480.088 ;
      RECT 0.500 482.200 2319.556 482.488 ;
      RECT 0.500 484.600 2319.556 484.888 ;
      RECT 0.500 487.000 2319.556 487.288 ;
      RECT 0.500 489.400 2319.556 489.688 ;
      RECT 0.500 491.800 2319.556 492.088 ;
      RECT 0.500 494.200 2319.556 494.488 ;
      RECT 0.500 496.600 2319.556 496.888 ;
      RECT 0.500 499.000 2319.556 499.288 ;
      RECT 0.500 501.400 2319.556 501.688 ;
      RECT 0.500 503.800 2319.556 504.088 ;
      RECT 0.500 506.200 2319.556 506.488 ;
      RECT 0.500 508.600 2319.556 508.888 ;
      RECT 0.500 511.000 2319.556 511.288 ;
      RECT 0.500 513.400 2319.556 513.688 ;
      RECT 0.500 515.800 2319.556 516.088 ;
      RECT 0.500 518.200 2319.556 518.488 ;
      RECT 0.500 520.600 2319.556 520.888 ;
      RECT 0.500 523.000 2319.556 523.288 ;
      RECT 0.500 525.400 2319.556 525.688 ;
      RECT 0.500 527.800 2319.556 528.088 ;
      RECT 0.500 530.200 2319.556 530.488 ;
      RECT 0.500 532.600 2319.556 532.888 ;
      RECT 0.500 535.000 2319.556 535.288 ;
      RECT 0.500 537.400 2319.556 537.688 ;
      RECT 0.500 539.800 2319.556 540.088 ;
      RECT 0.500 542.200 2319.556 542.488 ;
      RECT 0.500 544.600 2319.556 544.888 ;
      RECT 0.500 547.000 2319.556 547.288 ;
      RECT 0.500 549.400 2319.556 549.688 ;
      RECT 0.500 551.800 2319.556 552.088 ;
      RECT 0.500 554.200 2319.556 554.488 ;
      RECT 0.500 556.600 2319.556 556.888 ;
      RECT 0.500 559.000 2319.556 559.288 ;
      RECT 0.500 561.400 2319.556 561.688 ;
      RECT 0.500 563.800 2319.556 564.088 ;
      RECT 0.500 566.200 2319.556 566.488 ;
      RECT 0.500 568.600 2319.556 568.888 ;
      RECT 0.500 571.000 2319.556 571.288 ;
      RECT 0.500 573.400 2319.556 573.688 ;
      RECT 0.500 575.800 2319.556 576.088 ;
      RECT 0.500 578.200 2319.556 578.488 ;
      RECT 0.500 580.600 2319.556 580.888 ;
      RECT 0.500 583.000 2319.556 583.288 ;
      RECT 0.500 585.400 2319.556 585.688 ;
      RECT 0.500 587.800 2319.556 588.088 ;
      RECT 0.500 590.200 2319.556 590.488 ;
      RECT 0.500 592.600 2319.556 592.888 ;
      RECT 0.500 595.000 2319.556 595.288 ;
      RECT 0.500 597.400 2319.556 597.688 ;
      RECT 0.500 599.800 2319.556 600.088 ;
      RECT 0.500 602.200 2319.556 602.488 ;
      RECT 0.500 604.600 2319.556 604.888 ;
      RECT 0.500 607.000 2319.556 607.288 ;
      RECT 0.500 609.400 2319.556 609.688 ;
      RECT 0.500 611.800 2319.556 612.088 ;
      RECT 0.500 614.200 2319.556 614.488 ;
      RECT 0.500 616.600 2319.556 616.888 ;
      RECT 0.500 619.000 2319.556 619.288 ;
      RECT 0.500 621.400 2319.556 621.688 ;
      RECT 0.500 623.800 2319.556 624.088 ;
      RECT 0.500 626.200 2319.556 626.488 ;
      RECT 0.500 628.600 2319.556 628.888 ;
      RECT 0.500 631.000 2319.556 631.288 ;
      RECT 0.500 633.400 2319.556 633.688 ;
      RECT 0.500 635.800 2319.556 636.088 ;
      RECT 0.500 638.200 2319.556 638.488 ;
      RECT 0.500 640.600 2319.556 640.888 ;
      RECT 0.500 643.000 2319.556 643.288 ;
      RECT 0.500 645.400 2319.556 645.688 ;
      RECT 0.500 647.800 2319.556 648.088 ;
      RECT 0.500 650.200 2319.556 650.488 ;
      RECT 0.500 652.600 2319.556 652.888 ;
      RECT 0.500 655.000 2319.556 655.288 ;
      RECT 0.500 657.400 2319.556 657.688 ;
      RECT 0.500 659.800 2319.556 660.088 ;
      RECT 0.500 662.200 2319.556 662.488 ;
      RECT 0.500 664.600 2319.556 664.888 ;
      RECT 0.500 667.000 2319.556 667.288 ;
      RECT 0.500 669.400 2319.556 669.688 ;
      RECT 0.500 671.800 2319.556 672.088 ;
      RECT 0.500 674.200 2319.556 674.488 ;
      RECT 0.500 676.600 2319.556 676.888 ;
      RECT 0.500 679.000 2319.556 679.288 ;
      RECT 0.500 681.400 2319.556 681.688 ;
      RECT 0.500 683.800 2319.556 684.088 ;
      RECT 0.500 686.200 2319.556 686.488 ;
      RECT 0.500 688.600 2319.556 688.888 ;
      RECT 0.500 691.000 2319.556 691.288 ;
      RECT 0.500 693.400 2319.556 693.688 ;
      RECT 0.500 695.800 2319.556 696.088 ;
      RECT 0.500 698.200 2319.556 698.488 ;
      RECT 0.500 700.600 2319.556 700.888 ;
      RECT 0.500 703.000 2319.556 703.288 ;
      RECT 0.500 705.400 2319.556 705.688 ;
      RECT 0.500 707.800 2319.556 708.088 ;
      RECT 0.500 710.200 2319.556 710.488 ;
      RECT 0.500 712.600 2319.556 712.888 ;
      RECT 0.500 715.000 2319.556 715.288 ;
      RECT 0.500 717.400 2319.556 717.688 ;
      RECT 0.500 719.800 2319.556 720.088 ;
      RECT 0.500 722.200 2319.556 722.488 ;
      RECT 0.500 724.600 2319.556 724.888 ;
      RECT 0.500 727.000 2319.556 727.288 ;
      RECT 0.500 729.400 2319.556 729.688 ;
      RECT 0.500 731.800 2319.556 732.088 ;
      RECT 0.500 734.200 2319.556 734.488 ;
      RECT 0.500 736.600 2319.556 736.888 ;
      RECT 0.500 739.000 2319.556 739.288 ;
      RECT 0.500 741.400 2319.556 741.688 ;
      RECT 0.500 743.800 2319.556 744.088 ;
      RECT 0.500 746.200 2319.556 746.488 ;
      RECT 0.500 748.600 2319.556 748.888 ;
      RECT 0.500 751.000 2319.556 751.288 ;
      RECT 0.500 753.400 2319.556 753.688 ;
      RECT 0.500 755.800 2319.556 756.088 ;
      RECT 0.500 758.200 2319.556 758.488 ;
      RECT 0.500 760.600 2319.556 760.888 ;
      RECT 0.500 763.000 2319.556 763.288 ;
      RECT 0.500 765.400 2319.556 765.688 ;
      RECT 0.500 767.800 2319.556 768.088 ;
      RECT 0.500 770.200 2319.556 770.488 ;
      RECT 0.500 772.600 2319.556 772.888 ;
      RECT 0.500 775.000 2319.556 775.288 ;
      RECT 0.500 777.400 2319.556 777.688 ;
      RECT 0.500 779.800 2319.556 780.088 ;
      RECT 0.500 782.200 2319.556 782.488 ;
      RECT 0.500 784.600 2319.556 784.888 ;
      RECT 0.500 787.000 2319.556 787.288 ;
      RECT 0.500 789.400 2319.556 789.688 ;
      RECT 0.500 791.800 2319.556 792.088 ;
      RECT 0.500 794.200 2319.556 794.488 ;
      RECT 0.500 796.600 2319.556 796.888 ;
      RECT 0.500 799.000 2319.556 799.288 ;
      RECT 0.500 801.400 2319.556 801.688 ;
      RECT 0.500 803.800 2319.556 804.088 ;
      RECT 0.500 806.200 2319.556 806.488 ;
      RECT 0.500 808.600 2319.556 808.888 ;
      RECT 0.500 811.000 2319.556 811.288 ;
      RECT 0.500 813.400 2319.556 813.688 ;
      RECT 0.500 815.800 2319.556 816.088 ;
      RECT 0.500 818.200 2319.556 818.488 ;
      RECT 0.500 820.600 2319.556 820.888 ;
      RECT 0.500 823.000 2319.556 823.288 ;
      RECT 0.500 825.400 2319.556 825.688 ;
      RECT 0.500 827.800 2319.556 828.088 ;
      RECT 0.500 830.200 2319.556 830.488 ;
      RECT 0.500 832.600 2319.556 832.888 ;
      RECT 0.500 835.000 2319.556 835.288 ;
      RECT 0.500 837.400 2319.556 837.688 ;
      RECT 0.500 839.800 2319.556 840.088 ;
      RECT 0.500 842.200 2319.556 842.488 ;
      RECT 0.500 844.600 2319.556 844.888 ;
      RECT 0.500 847.000 2319.556 847.288 ;
      RECT 0.500 849.400 2319.556 849.688 ;
      RECT 0.500 851.800 2319.556 852.088 ;
      RECT 0.500 854.200 2319.556 854.488 ;
      RECT 0.500 856.600 2319.556 856.888 ;
      RECT 0.500 859.000 2319.556 859.288 ;
      RECT 0.500 861.400 2319.556 861.688 ;
      RECT 0.500 863.800 2319.556 864.088 ;
      RECT 0.500 866.200 2319.556 866.488 ;
      RECT 0.500 868.600 2319.556 868.888 ;
      RECT 0.500 871.000 2319.556 871.288 ;
      RECT 0.500 873.400 2319.556 873.688 ;
      RECT 0.500 875.800 2319.556 876.088 ;
      RECT 0.500 878.200 2319.556 878.488 ;
      RECT 0.500 880.600 2319.556 880.888 ;
      RECT 0.500 883.000 2319.556 883.288 ;
      RECT 0.500 885.400 2319.556 885.688 ;
      RECT 0.500 887.800 2319.556 888.088 ;
      RECT 0.500 890.200 2319.556 890.488 ;
      RECT 0.500 892.600 2319.556 892.888 ;
      RECT 0.500 895.000 2319.556 895.288 ;
      RECT 0.500 897.400 2319.556 897.688 ;
      RECT 0.500 899.800 2319.556 900.088 ;
      RECT 0.500 902.200 2319.556 902.488 ;
      RECT 0.500 904.600 2319.556 904.888 ;
      RECT 0.500 907.000 2319.556 907.288 ;
      RECT 0.500 909.400 2319.556 909.688 ;
      RECT 0.500 911.800 2319.556 912.088 ;
      RECT 0.500 914.200 2319.556 914.488 ;
      RECT 0.500 916.600 2319.556 916.888 ;
      RECT 0.500 919.000 2319.556 919.288 ;
      RECT 0.500 921.400 2319.556 921.688 ;
      RECT 0.500 923.800 2319.556 924.088 ;
      RECT 0.500 926.200 2319.556 926.488 ;
      RECT 0.500 928.600 2319.556 928.888 ;
      RECT 0.500 931.000 2319.556 931.288 ;
      RECT 0.500 933.400 2319.556 933.688 ;
      RECT 0.500 935.800 2319.556 936.088 ;
      RECT 0.500 938.200 2319.556 938.488 ;
      RECT 0.500 940.600 2319.556 940.888 ;
      RECT 0.500 943.000 2319.556 943.288 ;
      RECT 0.500 945.400 2319.556 945.688 ;
      RECT 0.500 947.800 2319.556 948.088 ;
      RECT 0.500 950.200 2319.556 950.488 ;
      RECT 0.500 952.600 2319.556 952.888 ;
      RECT 0.500 955.000 2319.556 955.288 ;
      RECT 0.500 957.400 2319.556 957.688 ;
      RECT 0.500 959.800 2319.556 960.088 ;
      RECT 0.500 962.200 2319.556 962.488 ;
      RECT 0.500 964.600 2319.556 964.888 ;
      RECT 0.500 967.000 2319.556 967.288 ;
      RECT 0.500 969.400 2319.556 969.688 ;
      RECT 0.500 971.800 2319.556 972.088 ;
      RECT 0.500 974.200 2319.556 974.488 ;
      RECT 0.500 976.600 2319.556 976.888 ;
      RECT 0.500 979.000 2319.556 979.288 ;
      RECT 0.500 981.400 2319.556 981.688 ;
      RECT 0.500 983.800 2319.556 984.088 ;
      RECT 0.500 986.200 2319.556 986.488 ;
      RECT 0.500 988.600 2319.556 988.888 ;
      RECT 0.500 991.000 2319.556 991.288 ;
      RECT 0.500 993.400 2319.556 993.688 ;
      RECT 0.500 995.800 2319.556 996.088 ;
      RECT 0.500 998.200 2319.556 998.488 ;
      RECT 0.500 1000.600 2319.556 1000.888 ;
      RECT 0.500 1003.000 2319.556 1003.288 ;
      RECT 0.500 1005.400 2319.556 1005.688 ;
      RECT 0.500 1007.800 2319.556 1008.088 ;
      RECT 0.500 1010.200 2319.556 1010.488 ;
      RECT 0.500 1012.600 2319.556 1012.888 ;
      RECT 0.500 1015.000 2319.556 1015.288 ;
      RECT 0.500 1017.400 2319.556 1017.688 ;
      RECT 0.500 1019.800 2319.556 1020.088 ;
      RECT 0.500 1022.200 2319.556 1022.488 ;
      RECT 0.500 1024.600 2319.556 1024.888 ;
      RECT 0.500 1027.000 2319.556 1027.288 ;
      RECT 0.500 1029.400 2319.556 1029.688 ;
      RECT 0.500 1031.800 2319.556 1032.088 ;
      RECT 0.500 1034.200 2319.556 1034.488 ;
      RECT 0.500 1036.600 2319.556 1036.888 ;
      RECT 0.500 1039.000 2319.556 1039.288 ;
      RECT 0.500 1041.400 2319.556 1041.688 ;
      RECT 0.500 1043.800 2319.556 1044.088 ;
      RECT 0.500 1046.200 2319.556 1046.488 ;
      RECT 0.500 1048.600 2319.556 1048.888 ;
      RECT 0.500 1051.000 2319.556 1051.288 ;
      RECT 0.500 1053.400 2319.556 1053.688 ;
      RECT 0.500 1055.800 2319.556 1056.088 ;
      RECT 0.500 1058.200 2319.556 1058.488 ;
      RECT 0.500 1060.600 2319.556 1060.888 ;
      RECT 0.500 1063.000 2319.556 1063.288 ;
      RECT 0.500 1065.400 2319.556 1065.688 ;
      RECT 0.500 1067.800 2319.556 1068.088 ;
      RECT 0.500 1070.200 2319.556 1070.488 ;
      RECT 0.500 1072.600 2319.556 1072.888 ;
      RECT 0.500 1075.000 2319.556 1075.288 ;
      RECT 0.500 1077.400 2319.556 1077.688 ;
      RECT 0.500 1079.800 2319.556 1080.088 ;
      RECT 0.500 1082.200 2319.556 1082.488 ;
      RECT 0.500 1084.600 2319.556 1084.888 ;
      RECT 0.500 1087.000 2319.556 1087.288 ;
      RECT 0.500 1089.400 2319.556 1089.688 ;
      RECT 0.500 1091.800 2319.556 1092.088 ;
      RECT 0.500 1094.200 2319.556 1094.488 ;
      RECT 0.500 1096.600 2319.556 1096.888 ;
      RECT 0.500 1099.000 2319.556 1099.288 ;
      RECT 0.500 1101.400 2319.556 1101.688 ;
      RECT 0.500 1103.800 2319.556 1104.088 ;
      RECT 0.500 1106.200 2319.556 1106.488 ;
      RECT 0.500 1108.600 2319.556 1108.888 ;
      RECT 0.500 1111.000 2319.556 1111.288 ;
      RECT 0.500 1113.400 2319.556 1113.688 ;
      RECT 0.500 1115.800 2319.556 1116.088 ;
      RECT 0.500 1118.200 2319.556 1118.488 ;
      RECT 0.500 1120.600 2319.556 1120.888 ;
      RECT 0.500 1123.000 2319.556 1123.288 ;
      RECT 0.500 1125.400 2319.556 1125.688 ;
      RECT 0.500 1127.800 2319.556 1128.088 ;
      RECT 0.500 1130.200 2319.556 1130.488 ;
      RECT 0.500 1132.600 2319.556 1132.888 ;
      RECT 0.500 1135.000 2319.556 1135.288 ;
      RECT 0.500 1137.400 2319.556 1137.688 ;
      RECT 0.500 1139.800 2319.556 1140.088 ;
      RECT 0.500 1142.200 2319.556 1142.488 ;
      RECT 0.500 1144.600 2319.556 1144.888 ;
      RECT 0.500 1147.000 2319.556 1147.288 ;
      RECT 0.500 1149.400 2319.556 1149.688 ;
      RECT 0.500 1151.800 2319.556 1152.088 ;
      RECT 0.500 1154.200 2319.556 1154.488 ;
      RECT 0.500 1156.600 2319.556 1156.888 ;
      RECT 0.500 1159.000 2319.556 1159.288 ;
      RECT 0.500 1161.400 2319.556 1161.688 ;
      RECT 0.500 1163.800 2319.556 1164.088 ;
      RECT 0.500 1166.200 2319.556 1166.488 ;
      RECT 0.500 1168.600 2319.556 1168.888 ;
      RECT 0.500 1171.000 2319.556 1171.288 ;
      RECT 0.500 1173.400 2319.556 1173.688 ;
      RECT 0.500 1175.800 2319.556 1176.088 ;
      RECT 0.500 1178.200 2319.556 1178.488 ;
      RECT 0.500 1180.600 2319.556 1180.888 ;
      RECT 0.500 1183.000 2319.556 1183.288 ;
      RECT 0.500 1185.400 2319.556 1185.688 ;
      RECT 0.500 1187.800 2319.556 1188.088 ;
      RECT 0.500 1190.200 2319.556 1190.488 ;
      RECT 0.500 1192.600 2319.556 1192.888 ;
      RECT 0.500 1195.000 2319.556 1195.288 ;
      RECT 0.500 1197.400 2319.556 1197.688 ;
      RECT 0.500 1199.800 2319.556 1200.088 ;
      RECT 0.500 1202.200 2319.556 1202.488 ;
      RECT 0.500 1204.600 2319.556 1204.888 ;
      RECT 0.500 1207.000 2319.556 1207.288 ;
      RECT 0.500 1209.400 2319.556 1209.688 ;
      RECT 0.500 1211.800 2319.556 1212.088 ;
      RECT 0.500 1214.200 2319.556 1214.488 ;
      RECT 0.500 1216.600 2319.556 1216.888 ;
      RECT 0.500 1219.000 2319.556 1219.288 ;
      RECT 0.500 1221.400 2319.556 1221.688 ;
      RECT 0.500 1223.800 2319.556 1224.088 ;
      RECT 0.500 1226.200 2319.556 1226.488 ;
      RECT 0.500 1228.600 2319.556 1228.888 ;
      RECT 0.500 1231.000 2319.556 1231.288 ;
      RECT 0.500 1233.400 2319.556 1233.688 ;
      RECT 0.500 1235.800 2319.556 1236.088 ;
      RECT 0.500 1238.200 2319.556 1238.488 ;
      RECT 0.500 1240.600 2319.556 1240.888 ;
      RECT 0.500 1243.000 2319.556 1243.288 ;
      RECT 0.500 1245.400 2319.556 1245.688 ;
      RECT 0.500 1247.800 2319.556 1248.088 ;
      RECT 0.500 1250.200 2319.556 1250.488 ;
      RECT 0.500 1252.600 2319.556 1252.888 ;
      RECT 0.500 1255.000 2319.556 1255.288 ;
      RECT 0.500 1257.400 2319.556 1257.688 ;
      RECT 0.500 1259.800 2319.556 1260.088 ;
      RECT 0.500 1262.200 2319.556 1262.488 ;
      RECT 0.500 1264.600 2319.556 1264.888 ;
      RECT 0.500 1267.000 2319.556 1267.288 ;
      RECT 0.500 1269.400 2319.556 1269.688 ;
      RECT 0.500 1271.800 2319.556 1272.088 ;
      RECT 0.500 1274.200 2319.556 1274.488 ;
      RECT 0.500 1276.600 2319.556 1276.888 ;
      RECT 0.500 1279.000 2319.556 1279.288 ;
      RECT 0.500 1281.400 2319.556 1281.688 ;
      RECT 0.500 1283.800 2319.556 1284.088 ;
      RECT 0.500 1286.200 2319.556 1286.488 ;
      RECT 0.500 1288.600 2319.556 1288.888 ;
      RECT 0.500 1291.000 2319.556 1291.288 ;
      RECT 0.500 1293.400 2319.556 1293.688 ;
      RECT 0.500 1295.800 2319.556 1296.088 ;
      RECT 0.500 1298.200 2319.556 1298.488 ;
      RECT 0.500 1300.600 2319.556 1300.888 ;
      RECT 0.500 1303.000 2319.556 1303.288 ;
      RECT 0.500 1305.400 2319.556 1305.688 ;
      RECT 0.500 1307.800 2319.556 1308.088 ;
      RECT 0.500 1310.200 2319.556 1310.488 ;
      RECT 0.500 1312.600 2319.556 1312.888 ;
      RECT 0.500 1315.000 2319.556 1315.288 ;
      RECT 0.500 1317.400 2319.556 1317.688 ;
      RECT 0.500 1319.800 2319.556 1320.088 ;
      RECT 0.500 1322.200 2319.556 1322.488 ;
      RECT 0.500 1324.600 2319.556 1324.888 ;
      RECT 0.500 1327.000 2319.556 1327.288 ;
      RECT 0.500 1329.400 2319.556 1329.688 ;
      RECT 0.500 1331.800 2319.556 1332.088 ;
      RECT 0.500 1334.200 2319.556 1334.488 ;
      RECT 0.500 1336.600 2319.556 1336.888 ;
      RECT 0.500 1339.000 2319.556 1339.288 ;
      RECT 0.500 1341.400 2319.556 1341.688 ;
      RECT 0.500 1343.800 2319.556 1344.088 ;
      RECT 0.500 1346.200 2319.556 1346.488 ;
      RECT 0.500 1348.600 2319.556 1348.888 ;
      RECT 0.500 1351.000 2319.556 1351.288 ;
      RECT 0.500 1353.400 2319.556 1353.688 ;
      RECT 0.500 1355.800 2319.556 1356.088 ;
      RECT 0.500 1358.200 2319.556 1358.488 ;
      RECT 0.500 1360.600 2319.556 1360.888 ;
      RECT 0.500 1363.000 2319.556 1363.288 ;
      RECT 0.500 1365.400 2319.556 1365.688 ;
      RECT 0.500 1367.800 2319.556 1368.088 ;
      RECT 0.500 1370.200 2319.556 1370.488 ;
      RECT 0.500 1372.600 2319.556 1372.888 ;
      RECT 0.500 1375.000 2319.556 1375.288 ;
      RECT 0.500 1377.400 2319.556 1377.688 ;
      RECT 0.500 1379.800 2319.556 1380.088 ;
      RECT 0.500 1382.200 2319.556 1382.488 ;
      RECT 0.500 1384.600 2319.556 1384.888 ;
      RECT 0.500 1387.000 2319.556 1387.288 ;
      RECT 0.500 1389.400 2319.556 1389.688 ;
      RECT 0.500 1391.800 2319.556 1392.088 ;
      RECT 0.500 1394.200 2319.556 1394.488 ;
      RECT 0.500 1396.600 2319.556 1396.888 ;
      RECT 0.500 1399.000 2319.556 1399.288 ;
      RECT 0.500 1401.400 2319.556 1401.688 ;
      RECT 0.500 1403.800 2319.556 1404.088 ;
      RECT 0.500 1406.200 2319.556 1406.488 ;
      RECT 0.500 1408.600 2319.556 1408.888 ;
      RECT 0.500 1411.000 2319.556 1411.288 ;
      RECT 0.500 1413.400 2319.556 1413.688 ;
      RECT 0.500 1415.800 2319.556 1416.088 ;
      RECT 0.500 1418.200 2319.556 1418.488 ;
      RECT 0.500 1420.600 2319.556 1420.888 ;
      RECT 0.500 1423.000 2319.556 1423.288 ;
      RECT 0.500 1425.400 2319.556 1425.688 ;
      RECT 0.500 1427.800 2319.556 1428.088 ;
      RECT 0.500 1430.200 2319.556 1430.488 ;
      RECT 0.500 1432.600 2319.556 1432.888 ;
      RECT 0.500 1435.000 2319.556 1435.288 ;
      RECT 0.500 1437.400 2319.556 1437.688 ;
      RECT 0.500 1439.800 2319.556 1440.088 ;
      RECT 0.500 1442.200 2319.556 1442.488 ;
      RECT 0.500 1444.600 2319.556 1444.888 ;
      RECT 0.500 1447.000 2319.556 1447.288 ;
      RECT 0.500 1449.400 2319.556 1449.688 ;
      RECT 0.500 1451.800 2319.556 1452.088 ;
      RECT 0.500 1454.200 2319.556 1454.488 ;
      RECT 0.500 1456.600 2319.556 1456.888 ;
      RECT 0.500 1459.000 2319.556 1459.288 ;
      RECT 0.500 1461.400 2319.556 1461.688 ;
      RECT 0.500 1463.800 2319.556 1464.088 ;
      RECT 0.500 1466.200 2319.556 1466.488 ;
      RECT 0.500 1468.600 2319.556 1468.888 ;
      RECT 0.500 1471.000 2319.556 1471.288 ;
      RECT 0.500 1473.400 2319.556 1473.688 ;
      RECT 0.500 1475.800 2319.556 1476.088 ;
      RECT 0.500 1478.200 2319.556 1478.488 ;
      RECT 0.500 1480.600 2319.556 1480.888 ;
      RECT 0.500 1483.000 2319.556 1483.288 ;
      RECT 0.500 1485.400 2319.556 1485.688 ;
      RECT 0.500 1487.800 2319.556 1488.088 ;
      RECT 0.500 1490.200 2319.556 1490.488 ;
      RECT 0.500 1492.600 2319.556 1492.888 ;
      RECT 0.500 1495.000 2319.556 1495.288 ;
      RECT 0.500 1497.400 2319.556 1497.688 ;
      RECT 0.500 1499.800 2319.556 1500.088 ;
      RECT 0.500 1502.200 2319.556 1502.488 ;
      RECT 0.500 1504.600 2319.556 1504.888 ;
      RECT 0.500 1507.000 2319.556 1507.288 ;
      RECT 0.500 1509.400 2319.556 1509.688 ;
      RECT 0.500 1511.800 2319.556 1512.088 ;
      RECT 0.500 1514.200 2319.556 1514.488 ;
      RECT 0.500 1516.600 2319.556 1516.888 ;
      RECT 0.500 1519.000 2319.556 1519.288 ;
      RECT 0.500 1521.400 2319.556 1521.688 ;
      RECT 0.500 1523.800 2319.556 1524.088 ;
      RECT 0.500 1526.200 2319.556 1526.488 ;
      RECT 0.500 1528.600 2319.556 1528.888 ;
      RECT 0.500 1531.000 2319.556 1531.288 ;
      RECT 0.500 1533.400 2319.556 1533.688 ;
      RECT 0.500 1535.800 2319.556 1536.088 ;
      RECT 0.500 1538.200 2319.556 1538.488 ;
      RECT 0.500 1540.600 2319.556 1540.888 ;
      RECT 0.500 1543.000 2319.556 1543.288 ;
      RECT 0.500 1545.400 2319.556 1545.688 ;
      RECT 0.500 1547.800 2319.556 1548.088 ;
      RECT 0.500 1550.200 2319.556 1550.488 ;
      RECT 0.500 1552.600 2319.556 1552.888 ;
      RECT 0.500 1555.000 2319.556 1555.288 ;
      RECT 0.500 1557.400 2319.556 1557.688 ;
      RECT 0.500 1559.800 2319.556 1560.088 ;
      RECT 0.500 1562.200 2319.556 1562.488 ;
    END
  END VSS
  OBS
    LAYER M1 ;
    RECT 0 0 2320.056 1563.570 ;
    LAYER M2 ;
    RECT 0 0 2320.056 1563.570 ;
    LAYER M3 ;
    RECT 0 0 2320.056 1563.570 ;
    LAYER M4 ;
    RECT 0.400 0 2320.056 1563.570 ;
    LAYER M5 ;
    RECT 0.400 0 2320.056 1563.170 ;
  END
END ot_qfd_serdes_112g_x12_phy_s597

END LIBRARY
